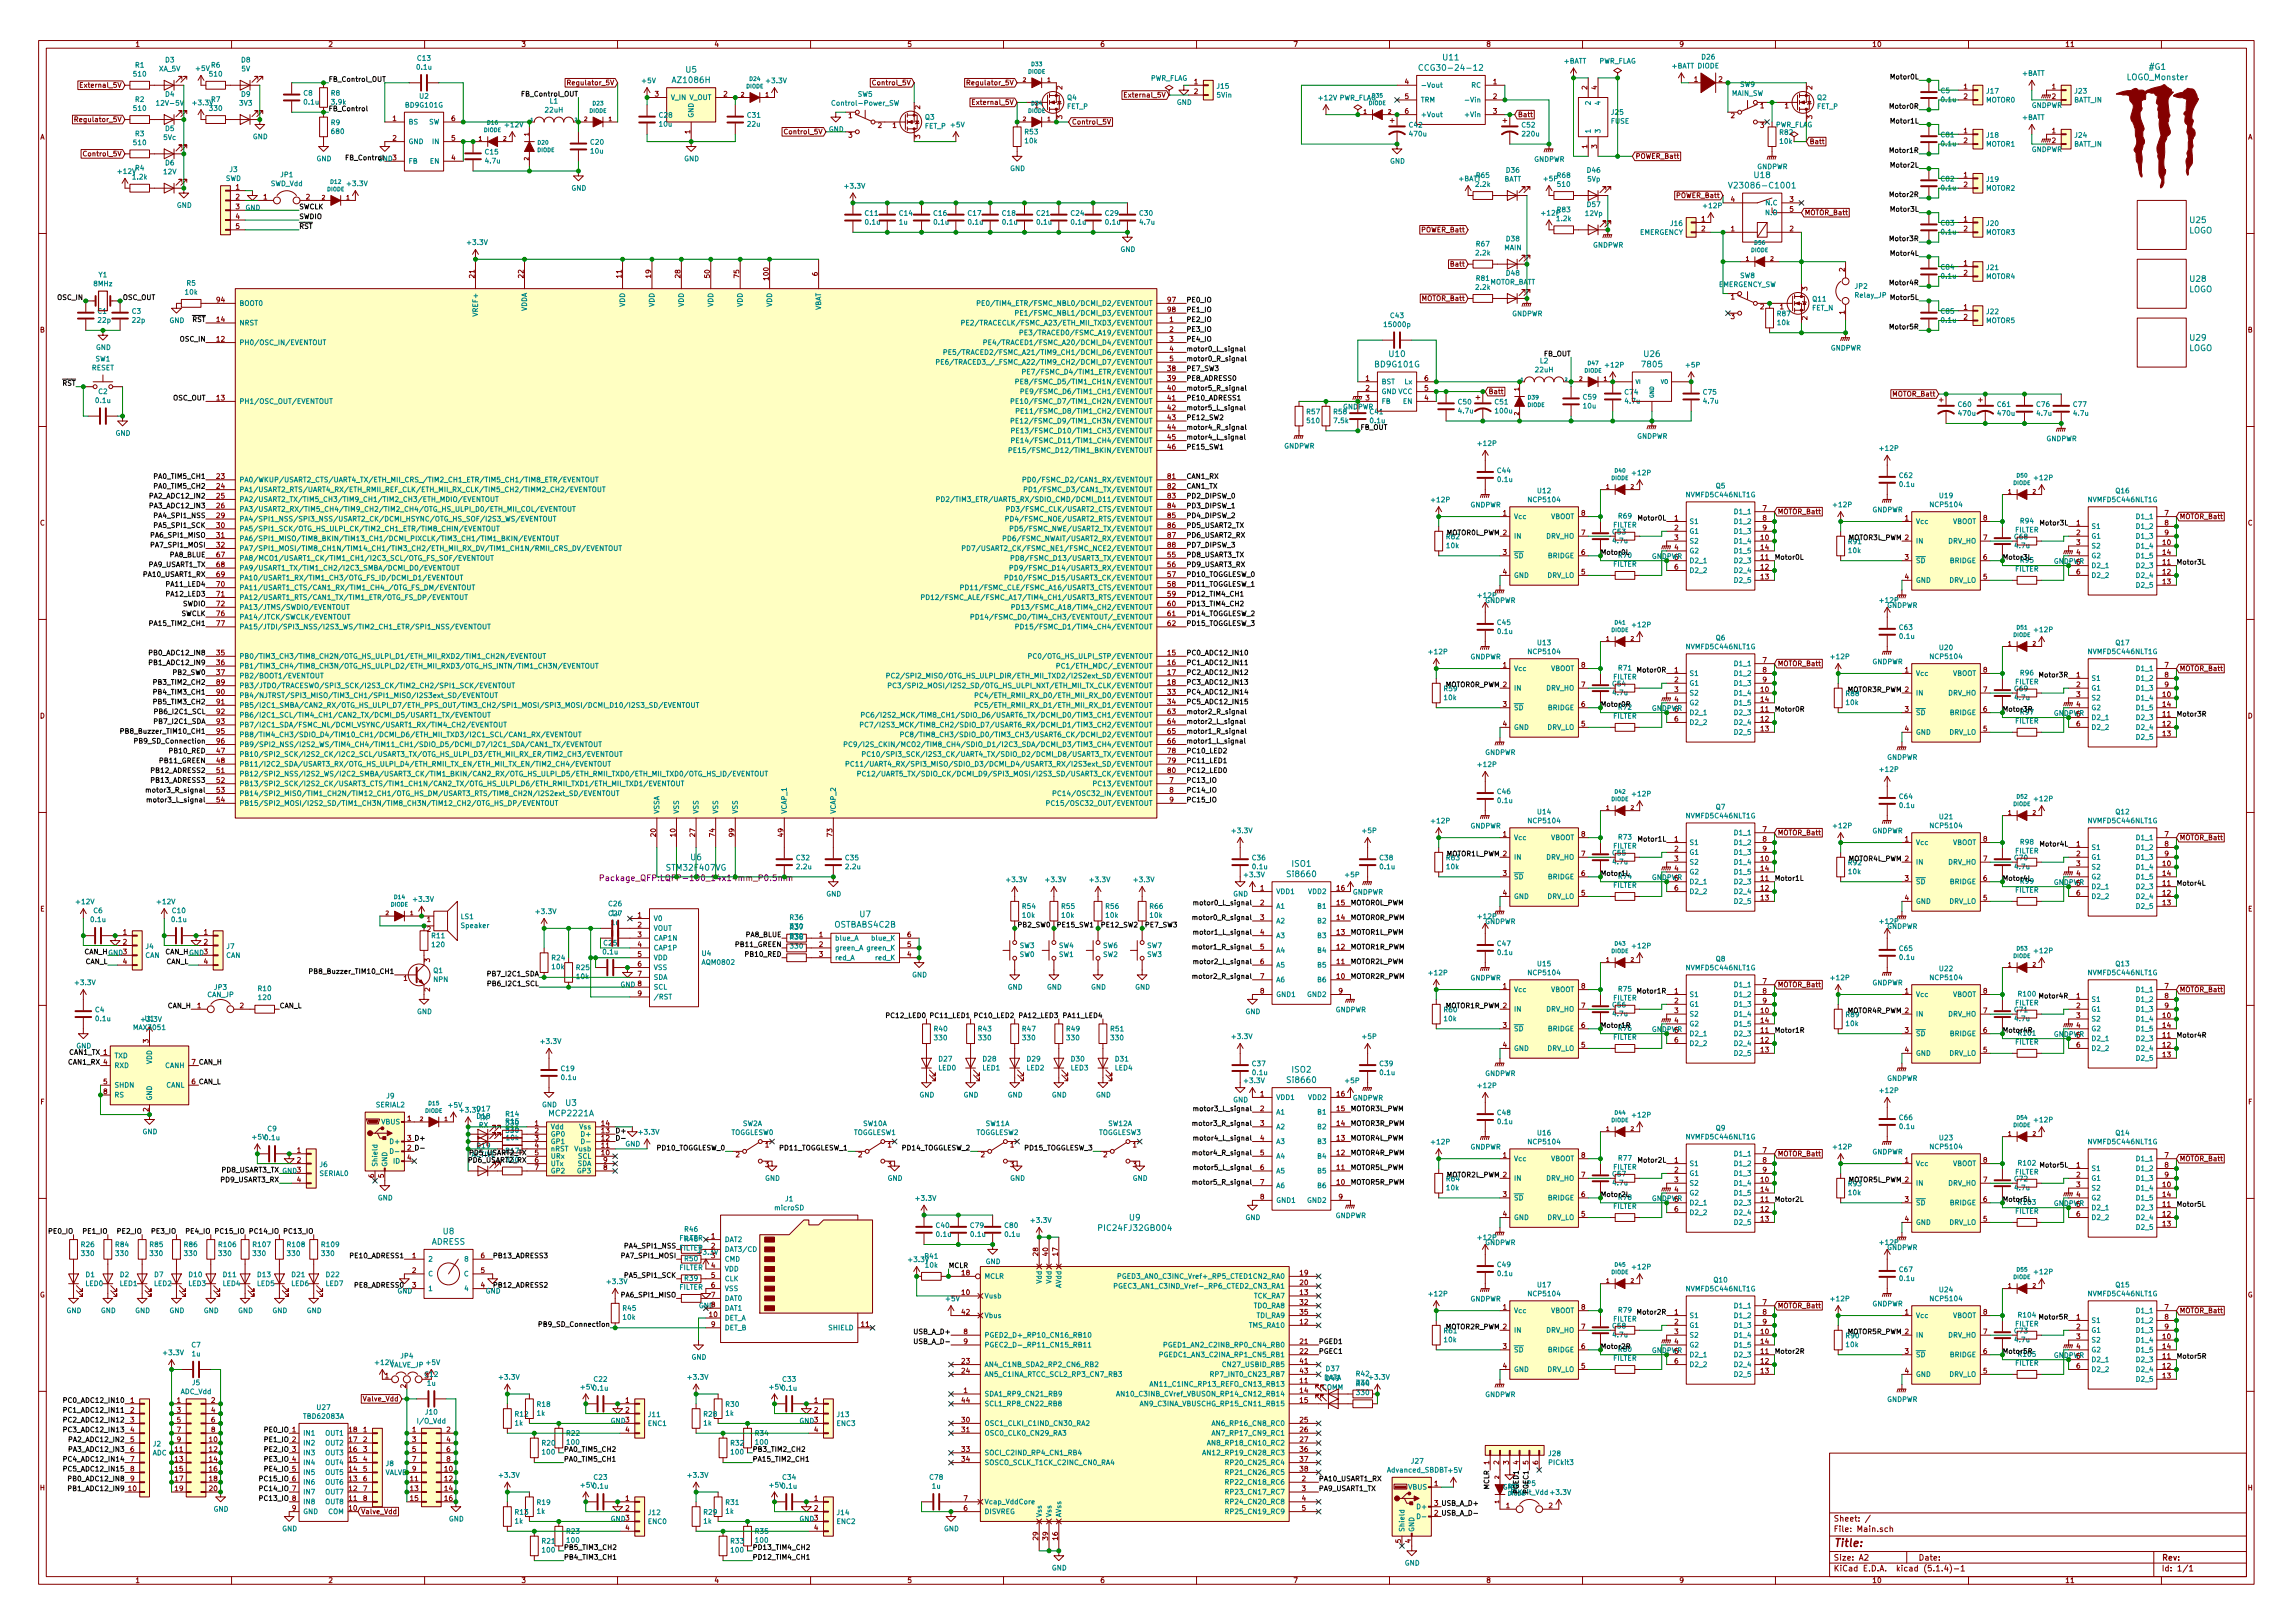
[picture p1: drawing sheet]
<svg xmlns="http://www.w3.org/2000/svg" width="297mm" height="210mm" viewBox="0 0 297 210" stroke-linecap="round" stroke-linejoin="round" font-family="sans-serif">
<defs><g id="words">
<text font-size="1.4" fill="#840000" x="237.5" y="200.4">Title:</text>
<g font-size="1.1" fill="#008484">
<text x="87.3" y="10.8">AZ1086H</text>
<text x="88.9" y="9.4">U5</text>
<text x="184.6" y="9.2">CCG30-24-12</text>
<text x="187" y="7.8">U11</text>
<text x="275.6" y="10.4">LOGO_Monster</text>
<text x="278.5" y="9">#G1</text>
<text x="227.3" y="23.1">U18</text>
<text x="224.7" y="24.4">V23086-C1001</text>
<text x="283.8" y="28.9">U25</text>
<text x="283.5" y="30.2">LOGO</text>
<text x="283.5" y="37.9">LOGO</text>
<text x="283.8" y="36.5">U28</text>
<text x="178.2" y="47.6">BD9G101G</text>
<text x="180" y="46.2">U10</text>
<text x="212.8" y="47.6">7805</text>
<text x="213" y="46.2">U26</text>
<text x="283.5" y="45.5">LOGO</text>
<text x="283.8" y="44.1">U29</text>
<text x="86.5" y="112.8">STM32F407VG</text>
<text x="89.5" y="111.4">U6</text>
<text x="166.9" y="113.6">Si8660</text>
<text x="167.4" y="112.3">ISO1</text>
<text x="111.4" y="118.8">U7</text>
<text x="108.1" y="120.2">OSTBABS4C2B</text>
<text x="73.3" y="143.3">U3</text>
<text x="166.9" y="140.3">Si8660</text>
<text x="167.4" y="138.9">ISO2</text>
<text x="71.2" y="144.6">MCP2221A</text>
<text x="55.9" y="161.2">ADRESS</text>
<text x="57.4" y="159.9">U8</text>
<text x="142.6" y="159.5">PIC24FJ32GB004</text>
<text x="146.3" y="158.1">U9</text>
</g>
<text font-size="1.1" fill="#008400" x="78.9" y="114.1">Package_QFP:LQFP-100_14x14mm_P0.5mm</text>
<g font-size="1" fill="#840000">
<text x="237.5" y="197.1">Sheet: /</text>
<text x="237.5" y="203.6">KiCad E.D.A. kicad (5.1.4)-1</text>
<text x="237.5" y="202.2">Size: A2</text>
<text x="237.5" y="198.5">File: Main.sch</text>
<text x="248.5" y="202.2">Date:</text>
<text x="280" y="202.2">Rev:</text>
<text x="280" y="203.6">Id: 1/1</text>
</g>
<g font-size=".9" fill="#840000">
<text x="10.7" y="11.4">External_5V</text>
<text x="17.5" y="6.1">1</text>
<text x="42.5" y="6.1">2</text>
<text x="67.5" y="6.1">3</text>
<text x="73.9" y="11">Regulator_5V</text>
<text x="92.5" y="6.1">4</text>
<text x="113.3" y="11">Control_5V</text>
<text x="117.5" y="6.1">5</text>
<text x="125.7" y="11">Regulator_5V</text>
<text x="137.6" y="11.6" transform="rotate(-90 137.6 11.6)">2</text>
<text x="142.5" y="6.1">6</text>
<text x="154.7" y="10.9">1</text>
<text x="167.5" y="6.1">7</text>
<text x="182" y="10.9">4</text>
<text x="192.5" y="6.1">8</text>
<text x="193.4" y="10.9">1</text>
<text x="205.6" y="11.6" transform="rotate(-90 205.6 11.6)">2</text>
<text x="206.9" y="11.6" transform="rotate(-90 206.9 11.6)">4</text>
<text x="217.5" y="6.1">9</text>
<text x="219.5" y="10.6">1</text>
<text x="222.6" y="10.6">2</text>
<text x="234.8" y="11.6" transform="rotate(-90 234.8 11.6)">2</text>
<text x="242.5" y="6.1">10</text>
<text x="254.4" y="11.6">1</text>
<text x="265.8" y="11.6">1</text>
<text x="267.5" y="6.1">11</text>
<text x="10.1" y="15.8">Regulator_5V</text>
<text x="50.9" y="15.7">1</text>
<text x="58.5" y="15.7">6</text>
<text x="84.8" y="12.5">3</text>
<text x="89.4" y="17.3" transform="rotate(-90 89.4 17.3)">1</text>
<text x="93.7" y="12.5">2</text>
<text x="101.9" y="17.4">Control_5V</text>
<text x="109.9" y="15.3">1</text>
<text x="109.9" y="17.8">3</text>
<text x="113.7" y="16.6">2</text>
<text x="115.6" y="16.6">1</text>
<text x="119.2" y="18" transform="rotate(-90 119.2 18)">3</text>
<text x="119.2" y="14.1" transform="rotate(-90 119.2 14.1)">2</text>
<text x="126.3" y="13.6">External_5V</text>
<text x="137.6" y="15.4" transform="rotate(-90 137.6 15.4)">3</text>
<text x="138.8" y="16.1">Control_5V</text>
<text x="146" y="12.6">External_5V</text>
<text x="154.7" y="12.2">2</text>
<text x="182" y="12.8">5</text>
<text x="182" y="14.7">6</text>
<text x="193.4" y="12.8">2</text>
<text x="193.4" y="14.7">3</text>
<text x="196.6" y="15.2">Batt</text>
<text x="224.2" y="15.3">2</text>
<text x="228" y="14">1</text>
<text x="228" y="16.6">3</text>
<text x="231.2" y="14">1</text>
<text x="234.8" y="15.4" transform="rotate(-90 234.8 15.4)">3</text>
<text x="254.4" y="12.8">2</text>
<text x="254.4" y="17.3">1</text>
<text x="265.8" y="12.8">2</text>
<text x="265.8" y="17.3">1</text>
<text x="5.2" y="18.1">A</text>
<text x="11.1" y="20.3">Control_5V</text>
<text x="50.9" y="18.2">2</text>
<text x="58.5" y="20.8">4</text>
<text x="58.5" y="18.2">5</text>
<text x="205.6" y="19.2" transform="rotate(-90 205.6 19.2)">1</text>
<text x="206.9" y="19.2" transform="rotate(-90 206.9 19.2)">3</text>
<text x="211.8" y="20.6">POWER_Batt</text>
<text x="234.4" y="18.7">Batt</text>
<text x="254.4" y="18.5">2</text>
<text x="254.4" y="23">1</text>
<text x="265.8" y="18.5">2</text>
<text x="291.2" y="18.1">A</text>
<text x="30.6" y="24.6">1</text>
<text x="30.6" y="25.8">2</text>
<text x="30.6" y="27.1">3</text>
<text x="30.6" y="28.4">4</text>
<text x="30.6" y="29.6">5</text>
<text x="34.1" y="25.8">1</text>
<text x="39.7" y="25.8">2</text>
<text x="217.3" y="25.6">POWER_Batt</text>
<text x="220.4" y="28.7">1</text>
<text x="220.4" y="30">2</text>
<text x="224.2" y="30">1</text>
<text x="224.2" y="26.2">4</text>
<text x="231.9" y="30">2</text>
<text x="231.9" y="26.2">3</text>
<text x="231.9" y="27.4">5</text>
<text x="233.8" y="27.9">MOTOR_Batt</text>
<text x="254.4" y="24.3">2</text>
<text x="254.4" y="28.7">1</text>
<text x="254.4" y="30">2</text>
<text x="61.5" y="36" transform="rotate(-90 61.5 36)">21</text>
<text x="67.8" y="36" transform="rotate(-90 67.8 36)">22</text>
<text x="80.5" y="36" transform="rotate(-90 80.5 36)">11</text>
<text x="84.3" y="36" transform="rotate(-90 84.3 36)">19</text>
<text x="88.1" y="36" transform="rotate(-90 88.1 36)">28</text>
<text x="91.9" y="36" transform="rotate(-90 91.9 36)">50</text>
<text x="95.8" y="36" transform="rotate(-90 95.8 36)">75</text>
<text x="105.9" y="35.7" transform="rotate(-90 105.9 35.7)">6</text>
<text x="184.2" y="30.1">POWER_Batt</text>
<text x="188.1" y="34.5">Batt</text>
<text x="239" y="35.2" transform="rotate(-90 239 35.2)">2</text>
<text x="254.4" y="34.4">1</text>
<text x="254.4" y="35.7">2</text>
<text x="28.1" y="41.7">14</text>
<text x="28.1" y="39.2">94</text>
<text x="99.6" y="36.2" transform="rotate(-90 99.6 36.2)">100</text>
<text x="151.3" y="39.2">97</text>
<text x="151.3" y="40.4">98</text>
<text x="151.5" y="41.7">1</text>
<text x="184.3" y="39">MOTOR_Batt</text>
<text x="224.2" y="38.8">1</text>
<text x="224.2" y="41.3">3</text>
<text x="228" y="40.1">2</text>
<text x="230.6" y="40.1">1</text>
<text x="234.1" y="41.4" transform="rotate(-90 234.1 41.4)">2</text>
<text x="234.1" y="37.6" transform="rotate(-90 234.1 37.6)">3</text>
<text x="239" y="40.7" transform="rotate(-90 239 40.7)">1</text>
<text x="254.4" y="40.1">1</text>
<text x="254.4" y="41.4">2</text>
<text x="5.2" y="43.1">B</text>
<text x="28.1" y="44.3">12</text>
<text x="151.5" y="43">2</text>
<text x="151.5" y="44.3">3</text>
<text x="151.5" y="45.5">4</text>
<text x="151.5" y="46.8">5</text>
<text x="291.2" y="43.1">B</text>
<text x="28.1" y="51.9">13</text>
<text x="151.3" y="48.1">38</text>
<text x="151.3" y="49.3">39</text>
<text x="151.3" y="50.6">40</text>
<text x="151.3" y="51.9">41</text>
<text x="151.3" y="53.1">42</text>
<text x="176.9" y="49.3">1</text>
<text x="176.9" y="50.6">2</text>
<text x="176.9" y="51.9">3</text>
<text x="184.5" y="51.9">4</text>
<text x="184.5" y="50.6">5</text>
<text x="184.5" y="49.3">6</text>
<text x="192.8" y="51">Batt</text>
<text x="245.2" y="51.4">MOTOR_Batt</text>
<text x="151.3" y="54.4">43</text>
<text x="151.3" y="55.7">44</text>
<text x="151.3" y="57">45</text>
<text x="151.3" y="58.2">46</text>
<text x="28.1" y="62">23</text>
<text x="28.1" y="63.3">24</text>
<text x="28.1" y="64.6">25</text>
<text x="28.1" y="65.8">26</text>
<text x="151.3" y="62">81</text>
<text x="151.3" y="63.3">82</text>
<text x="151.3" y="64.6">83</text>
<text x="151.3" y="65.8">84</text>
<text x="5.2" y="68.1">C</text>
<text x="28.1" y="67.1">29</text>
<text x="28.1" y="68.4">30</text>
<text x="28.1" y="69.7">31</text>
<text x="28.1" y="70.9">32</text>
<text x="151.3" y="67.1">85</text>
<text x="151.3" y="68.4">86</text>
<text x="151.3" y="69.7">87</text>
<text x="151.3" y="70.9">88</text>
<text x="194.7" y="66.8">1</text>
<text x="194.7" y="71.9">3</text>
<text x="204.9" y="71.9">6</text>
<text x="204.9" y="69.3">7</text>
<text x="204.9" y="66.8">8</text>
<text x="216.9" y="67.4">1</text>
<text x="216.9" y="68.7">2</text>
<text x="216.9" y="70">3</text>
<text x="216.9" y="71.2">4</text>
<text x="228.1" y="70">10</text>
<text x="228.1" y="71.2">14</text>
<text x="228.4" y="66.2">7</text>
<text x="228.4" y="67.4">8</text>
<text x="228.4" y="68.7">9</text>
<text x="230.3" y="66.6">MOTOR_Batt</text>
<text x="246.8" y="67.4">1</text>
<text x="256.9" y="70">7</text>
<text x="256.9" y="67.4">8</text>
<text x="269" y="68.1">1</text>
<text x="269" y="69.3">2</text>
<text x="269" y="70.6">3</text>
<text x="269" y="71.9">4</text>
<text x="280.2" y="70.6">10</text>
<text x="280.2" y="71.9">14</text>
<text x="280.4" y="66.8">7</text>
<text x="280.4" y="68.1">8</text>
<text x="280.4" y="69.3">9</text>
<text x="282.3" y="67.2">MOTOR_Batt</text>
<text x="291.2" y="68.1">C</text>
<text x="28.1" y="72.2">67</text>
<text x="28.1" y="73.5">68</text>
<text x="28.1" y="74.7">69</text>
<text x="28.1" y="76">70</text>
<text x="28.1" y="77.3">71</text>
<text x="151.3" y="72.2">55</text>
<text x="151.3" y="73.5">56</text>
<text x="151.3" y="74.7">57</text>
<text x="151.3" y="76">58</text>
<text x="151.3" y="77.3">59</text>
<text x="194.7" y="74.4">4</text>
<text x="204.9" y="74.4">5</text>
<text x="216.9" y="72.5">5</text>
<text x="216.9" y="73.8">6</text>
<text x="228.1" y="72.5">11</text>
<text x="228.1" y="73.8">12</text>
<text x="228.1" y="75.1">13</text>
<text x="246.8" y="72.5">3</text>
<text x="246.8" y="75.1">4</text>
<text x="256.9" y="75.1">5</text>
<text x="256.9" y="72.5">6</text>
<text x="269" y="73.1">5</text>
<text x="269" y="74.4">6</text>
<text x="280.2" y="73.1">11</text>
<text x="280.2" y="74.4">12</text>
<text x="280.2" y="75.7">13</text>
<text x="28.1" y="78.5">72</text>
<text x="28.1" y="79.8">76</text>
<text x="28.1" y="81.1">77</text>
<text x="151.3" y="78.5">60</text>
<text x="151.3" y="79.8">61</text>
<text x="151.3" y="81.1">62</text>
<text x="28.1" y="84.9">35</text>
<text x="28.1" y="86.2">36</text>
<text x="28.1" y="87.4">37</text>
<text x="28.1" y="88.7">89</text>
<text x="28.1" y="90">90</text>
<text x="151.3" y="84.9">15</text>
<text x="151.3" y="86.2">16</text>
<text x="151.3" y="87.4">17</text>
<text x="151.3" y="88.7">18</text>
<text x="151.3" y="90">33</text>
<text x="194.7" y="86.5">1</text>
<text x="204.9" y="89">7</text>
<text x="204.9" y="86.5">8</text>
<text x="216.9" y="87.1">1</text>
<text x="216.9" y="88.4">2</text>
<text x="216.9" y="89.7">3</text>
<text x="228.1" y="89.7">10</text>
<text x="228.4" y="85.8">7</text>
<text x="228.4" y="87.1">8</text>
<text x="228.4" y="88.4">9</text>
<text x="230.3" y="86.3">MOTOR_Batt</text>
<text x="246.8" y="87.1">1</text>
<text x="256.9" y="89.7">7</text>
<text x="256.9" y="87.1">8</text>
<text x="269" y="87.8">1</text>
<text x="269" y="89">2</text>
<text x="280.4" y="86.5">7</text>
<text x="280.4" y="87.8">8</text>
<text x="280.4" y="89">9</text>
<text x="282.3" y="86.9">MOTOR_Batt</text>
<text x="5.2" y="93.1">D</text>
<text x="28.1" y="91.2">91</text>
<text x="28.1" y="92.5">92</text>
<text x="28.1" y="93.8">93</text>
<text x="28.1" y="95.1">95</text>
<text x="151.3" y="91.2">34</text>
<text x="151.3" y="92.5">63</text>
<text x="151.3" y="93.8">64</text>
<text x="151.3" y="95.1">65</text>
<text x="194.7" y="91.6">3</text>
<text x="194.7" y="94.1">4</text>
<text x="204.9" y="94.1">5</text>
<text x="204.9" y="91.6">6</text>
<text x="216.9" y="90.9">4</text>
<text x="216.9" y="92.2">5</text>
<text x="216.9" y="93.5">6</text>
<text x="228.1" y="92.2">11</text>
<text x="228.1" y="93.5">12</text>
<text x="228.1" y="94.7">13</text>
<text x="228.1" y="90.9">14</text>
<text x="246.8" y="92.2">3</text>
<text x="246.8" y="94.7">4</text>
<text x="256.9" y="94.7">5</text>
<text x="256.9" y="92.2">6</text>
<text x="269" y="90.3">3</text>
<text x="269" y="91.6">4</text>
<text x="269" y="92.8">5</text>
<text x="269" y="94.1">6</text>
<text x="280.2" y="90.3">10</text>
<text x="280.2" y="92.8">11</text>
<text x="280.2" y="94.1">12</text>
<text x="280.2" y="95.4">13</text>
<text x="280.2" y="91.6">14</text>
<text x="291.2" y="93.1">D</text>
<text x="28.1" y="97.6">47</text>
<text x="28.1" y="98.9">48</text>
<text x="28.1" y="100.1">51</text>
<text x="28.1" y="101.4">52</text>
<text x="28.1" y="96.3">96</text>
<text x="151.3" y="96.3">66</text>
<text x="151.3" y="97.6">78</text>
<text x="151.3" y="98.9">79</text>
<text x="151.3" y="100.1">80</text>
<text x="151.5" y="101.4">7</text>
<text x="28.1" y="102.7">53</text>
<text x="28.1" y="103.9">54</text>
<text x="151.5" y="102.7">8</text>
<text x="151.5" y="103.9">9</text>
<text x="228.4" y="107.8">7</text>
<text x="85" y="108.4" transform="rotate(-90 85 108.4)">20</text>
<text x="87.5" y="108.4" transform="rotate(-90 87.5 108.4)">10</text>
<text x="90" y="108.4" transform="rotate(-90 90 108.4)">27</text>
<text x="92.6" y="108.4" transform="rotate(-90 92.6 108.4)">74</text>
<text x="95.1" y="108.4" transform="rotate(-90 95.1 108.4)">99</text>
<text x="101.5" y="108.4" transform="rotate(-90 101.5 108.4)">49</text>
<text x="107.8" y="108.4" transform="rotate(-90 107.8 108.4)">73</text>
<text x="194.7" y="108.4">1</text>
<text x="194.7" y="113.5">3</text>
<text x="204.9" y="113.5">6</text>
<text x="204.9" y="110.9">7</text>
<text x="204.9" y="108.4">8</text>
<text x="216.9" y="109">1</text>
<text x="216.9" y="110.3">2</text>
<text x="216.9" y="111.6">3</text>
<text x="216.9" y="112.8">4</text>
<text x="228.1" y="111.6">10</text>
<text x="228.1" y="112.8">14</text>
<text x="228.4" y="109">8</text>
<text x="228.4" y="110.3">9</text>
<text x="230.3" y="108.2">MOTOR_Batt</text>
<text x="246.8" y="109">1</text>
<text x="256.9" y="111.6">7</text>
<text x="256.9" y="109">8</text>
<text x="269" y="109.7">1</text>
<text x="269" y="110.9">2</text>
<text x="269" y="112.2">3</text>
<text x="269" y="113.5">4</text>
<text x="280.2" y="112.2">10</text>
<text x="280.2" y="113.5">14</text>
<text x="280.4" y="108.4">7</text>
<text x="280.4" y="109.7">8</text>
<text x="280.4" y="110.9">9</text>
<text x="282.3" y="108.8">MOTOR_Batt</text>
<text x="5.2" y="118.1">E</text>
<text x="55.3" y="119.4">1</text>
<text x="82.6" y="118.9">1</text>
<text x="163.3" y="115.4">1</text>
<text x="163.3" y="117.3">2</text>
<text x="163.3" y="119.2">3</text>
<text x="173.2" y="119.2">14</text>
<text x="173.2" y="117.3">15</text>
<text x="173.2" y="115.4">16</text>
<text x="194.7" y="116">4</text>
<text x="204.9" y="116">5</text>
<text x="216.9" y="114.1">5</text>
<text x="216.9" y="115.4">6</text>
<text x="228.1" y="114.1">11</text>
<text x="228.1" y="115.4">12</text>
<text x="228.1" y="116.6">13</text>
<text x="246.8" y="114.1">3</text>
<text x="246.8" y="116.6">4</text>
<text x="256.9" y="116.6">5</text>
<text x="256.9" y="114.1">6</text>
<text x="269" y="114.7">5</text>
<text x="269" y="116">6</text>
<text x="280.2" y="114.7">11</text>
<text x="280.2" y="116">12</text>
<text x="280.2" y="117.3">13</text>
<text x="291.2" y="118.1">E</text>
<text x="16" y="121.1">1</text>
<text x="16" y="122.4">2</text>
<text x="16" y="124.9">4</text>
<text x="26.4" y="121.1">1</text>
<text x="26.4" y="122.4">2</text>
<text x="26.4" y="124.9">4</text>
<text x="55.3" y="120.7">2</text>
<text x="55.7" y="124.6" transform="rotate(-90 55.7 124.6)">3</text>
<text x="82.6" y="120.1">2</text>
<text x="82.6" y="121.4">3</text>
<text x="82.6" y="122.7">4</text>
<text x="82.6" y="123.9">5</text>
<text x="82.6" y="125.2">6</text>
<text x="106.1" y="121.4">1</text>
<text x="106.1" y="122.7">2</text>
<text x="106.1" y="123.9">3</text>
<text x="117.6" y="123.9">4</text>
<text x="117.6" y="122.7">5</text>
<text x="117.6" y="121.4">6</text>
<text x="163.3" y="121.1">4</text>
<text x="163.3" y="123">5</text>
<text x="163.3" y="124.9">6</text>
<text x="173.2" y="124.9">11</text>
<text x="173.2" y="123">12</text>
<text x="173.2" y="121.1">13</text>
<text x="25.6" y="130.6">1</text>
<text x="31.1" y="130.6">2</text>
<text x="52.3" y="127.1">1</text>
<text x="55.7" y="128.4" transform="rotate(-90 55.7 128.4)">2</text>
<text x="82.6" y="126.5">7</text>
<text x="82.6" y="129">9</text>
<text x="163.3" y="126.8">7</text>
<text x="163.3" y="128.7">8</text>
<text x="173.2" y="126.8">10</text>
<text x="173.4" y="128.7">9</text>
<text x="194.7" y="128.1">1</text>
<text x="204.9" y="130.6">7</text>
<text x="204.9" y="128.1">8</text>
<text x="216.9" y="128.7">1</text>
<text x="216.9" y="130">2</text>
<text x="216.9" y="131.2">3</text>
<text x="228.1" y="131.2">10</text>
<text x="228.4" y="127.4">7</text>
<text x="228.4" y="128.7">8</text>
<text x="228.4" y="130">9</text>
<text x="230.3" y="127.9">MOTOR_Batt</text>
<text x="246.8" y="128.7">1</text>
<text x="256.9" y="131.2">7</text>
<text x="256.9" y="128.7">8</text>
<text x="269" y="129.3">1</text>
<text x="269" y="130.6">2</text>
<text x="269" y="131.9">3</text>
<text x="280.2" y="131.9">10</text>
<text x="280.4" y="128.1">7</text>
<text x="280.4" y="129.3">8</text>
<text x="280.4" y="130.6">9</text>
<text x="282.3" y="128.5">MOTOR_Batt</text>
<text x="19.2" y="135.1" transform="rotate(-90 19.2 135.1)">3</text>
<text x="194.7" y="133.2">3</text>
<text x="194.7" y="135.7">4</text>
<text x="204.9" y="135.7">5</text>
<text x="204.9" y="133.2">6</text>
<text x="216.9" y="132.5">4</text>
<text x="216.9" y="133.8">5</text>
<text x="216.9" y="135.1">6</text>
<text x="228.1" y="133.8">11</text>
<text x="228.1" y="135.1">12</text>
<text x="228.1" y="136.3">13</text>
<text x="228.1" y="132.5">14</text>
<text x="246.8" y="133.8">3</text>
<text x="246.8" y="136.3">4</text>
<text x="256.9" y="136.3">5</text>
<text x="256.9" y="133.8">6</text>
<text x="269" y="133.2">4</text>
<text x="269" y="134.4">5</text>
<text x="269" y="135.7">6</text>
<text x="280.2" y="134.4">11</text>
<text x="280.2" y="135.7">12</text>
<text x="280.2" y="137">13</text>
<text x="280.2" y="133.2">14</text>
<text x="5.2" y="143.1">F</text>
<text x="13.4" y="140.5">5</text>
<text x="13.4" y="141.7">8</text>
<text x="19.2" y="144" transform="rotate(-90 19.2 144)">2</text>
<text x="163.3" y="142">1</text>
<text x="163.3" y="143.9">2</text>
<text x="173.2" y="143.9">15</text>
<text x="173.2" y="142">16</text>
<text x="291.2" y="143.1">F</text>
<text x="38.5" y="149.3">1</text>
<text x="52.8" y="145.2">1</text>
<text x="61.8" y="148.7">D19</text>
<text x="69.3" y="145.9">1</text>
<text x="69.3" y="146.8">2</text>
<text x="69.3" y="147.8">3</text>
<text x="69.3" y="148.7">4</text>
<text x="69.3" y="149.7">5</text>
<text x="77.9" y="149.7">10</text>
<text x="77.9" y="148.7">11</text>
<text x="77.9" y="147.8">12</text>
<text x="77.9" y="146.8">13</text>
<text x="77.9" y="145.9">14</text>
<text x="95.3" y="149.9">2</text>
<text x="99.1" y="148.6">1</text>
<text x="111.2" y="149.9">2</text>
<text x="115" y="148.6">1</text>
<text x="127.1" y="149.9">2</text>
<text x="130.9" y="148.6">1</text>
<text x="143" y="149.9">2</text>
<text x="146.8" y="148.6">1</text>
<text x="163.3" y="145.9">3</text>
<text x="163.3" y="147.8">4</text>
<text x="163.3" y="149.7">5</text>
<text x="173.2" y="149.7">12</text>
<text x="173.2" y="147.8">13</text>
<text x="173.2" y="145.9">14</text>
<text x="194.7" y="150">1</text>
<text x="204.9" y="150">8</text>
<text x="228.4" y="149.3">7</text>
<text x="230.3" y="149.8">MOTOR_Batt</text>
<text x="280.4" y="150">7</text>
<text x="38.5" y="150.6">2</text>
<text x="38.5" y="153.2">4</text>
<text x="48.5" y="152.6" transform="rotate(-90 48.5 152.6)">6</text>
<text x="49.7" y="152.6" transform="rotate(-90 49.7 152.6)">5</text>
<text x="52.8" y="150.3">4</text>
<text x="69.3" y="150.6">6</text>
<text x="69.3" y="151.6">7</text>
<text x="78.2" y="151.6">8</text>
<text x="78.2" y="150.6">9</text>
<text x="99.1" y="151.2">3</text>
<text x="115" y="151.2">3</text>
<text x="130.9" y="151.2">3</text>
<text x="146.8" y="151.2">3</text>
<text x="163.3" y="151.6">6</text>
<text x="163.3" y="153.5">7</text>
<text x="163.3" y="155.4">8</text>
<text x="173.2" y="153.5">10</text>
<text x="173.2" y="151.6">11</text>
<text x="173.4" y="155.4">9</text>
<text x="194.7" y="155.1">3</text>
<text x="204.9" y="155.1">6</text>
<text x="204.9" y="152.5">7</text>
<text x="216.9" y="150.6">1</text>
<text x="216.9" y="151.9">2</text>
<text x="216.9" y="153.2">3</text>
<text x="216.9" y="154.4">4</text>
<text x="216.9" y="155.7">5</text>
<text x="228.1" y="153.2">10</text>
<text x="228.1" y="155.7">11</text>
<text x="228.1" y="154.4">14</text>
<text x="228.4" y="150.6">8</text>
<text x="228.4" y="151.9">9</text>
<text x="246.8" y="150.6">1</text>
<text x="246.8" y="155.7">3</text>
<text x="256.9" y="155.7">6</text>
<text x="256.9" y="153.2">7</text>
<text x="256.9" y="150.6">8</text>
<text x="269" y="151.3">1</text>
<text x="269" y="152.5">2</text>
<text x="269" y="153.8">3</text>
<text x="269" y="155.1">4</text>
<text x="280.2" y="153.8">10</text>
<text x="280.2" y="155.1">14</text>
<text x="280.4" y="151.3">8</text>
<text x="280.4" y="152.5">9</text>
<text x="282.3" y="150.4">MOTOR_Batt</text>
<text x="92.2" y="160.5">1</text>
<text x="92.2" y="161.7">2</text>
<text x="194.7" y="157.6">4</text>
<text x="204.9" y="157.6">5</text>
<text x="216.9" y="157">6</text>
<text x="228.1" y="157">12</text>
<text x="228.1" y="158.2">13</text>
<text x="246.8" y="158.2">4</text>
<text x="256.9" y="158.2">5</text>
<text x="269" y="156.3">5</text>
<text x="269" y="157.6">6</text>
<text x="280.2" y="156.3">11</text>
<text x="280.2" y="157.6">12</text>
<text x="280.2" y="158.9">13</text>
<text x="53.4" y="163">1</text>
<text x="53.4" y="164.9">2</text>
<text x="53.4" y="166.8">3</text>
<text x="62.3" y="166.8">4</text>
<text x="62.3" y="164.9">5</text>
<text x="62.3" y="163">6</text>
<text x="92.2" y="163">3</text>
<text x="92.2" y="164.3">4</text>
<text x="92.2" y="165.5">5</text>
<text x="92.2" y="166.8">6</text>
<text x="124.6" y="167.8">10</text>
<text x="124.6" y="165.2">18</text>
<text x="134.5" y="162.7" transform="rotate(-90 134.5 162.7)">28</text>
<text x="135.8" y="162.7" transform="rotate(-90 135.8 162.7)">40</text>
<text x="137" y="162.7" transform="rotate(-90 137 162.7)">17</text>
<text x="168.4" y="167.8">13</text>
<text x="168.4" y="165.2">19</text>
<text x="168.4" y="166.5">20</text>
<text x="5.2" y="168.1">G</text>
<text x="91.9" y="170.6">10</text>
<text x="92.2" y="168.1">7</text>
<text x="92.2" y="171.9">9</text>
<text x="111.6" y="171.9">11</text>
<text x="124.6" y="170.3">42</text>
<text x="124.9" y="172.8">8</text>
<text x="168.4" y="171.6">12</text>
<text x="168.4" y="169">32</text>
<text x="168.4" y="170.3">35</text>
<text x="194.7" y="169.7">1</text>
<text x="204.9" y="172.2">7</text>
<text x="204.9" y="169.7">8</text>
<text x="216.9" y="170.3">1</text>
<text x="216.9" y="171.6">2</text>
<text x="216.9" y="172.8">3</text>
<text x="228.1" y="172.8">10</text>
<text x="228.4" y="169">7</text>
<text x="228.4" y="170.3">8</text>
<text x="228.4" y="171.6">9</text>
<text x="230.3" y="169.5">MOTOR_Batt</text>
<text x="246.8" y="170.3">1</text>
<text x="256.9" y="172.8">7</text>
<text x="256.9" y="170.3">8</text>
<text x="269" y="170.9">1</text>
<text x="269" y="172.2">2</text>
<text x="269" y="173.5">3</text>
<text x="280.2" y="173.5">10</text>
<text x="280.4" y="169.7">7</text>
<text x="280.4" y="170.9">8</text>
<text x="280.4" y="172.2">9</text>
<text x="282.3" y="170.1">MOTOR_Batt</text>
<text x="291.2" y="168.1">G</text>
<text x="49.9" y="178.6">1</text>
<text x="52.6" y="179.8" transform="rotate(-90 52.6 179.8)">2</text>
<text x="55" y="178.6">3</text>
<text x="124.6" y="176.7">23</text>
<text x="124.6" y="177.9">24</text>
<text x="124.9" y="174.1">9</text>
<text x="168.4" y="179.2">11</text>
<text x="168.4" y="174.1">21</text>
<text x="168.4" y="175.4">22</text>
<text x="168.4" y="176.7">41</text>
<text x="168.4" y="177.9">43</text>
<text x="194.7" y="174.7">3</text>
<text x="194.7" y="177.3">4</text>
<text x="204.9" y="177.3">5</text>
<text x="204.9" y="174.7">6</text>
<text x="216.9" y="174.1">4</text>
<text x="216.9" y="175.4">5</text>
<text x="216.9" y="176.7">6</text>
<text x="228.1" y="175.4">11</text>
<text x="228.1" y="176.7">12</text>
<text x="228.1" y="177.9">13</text>
<text x="228.1" y="174.1">14</text>
<text x="246.8" y="175.4">3</text>
<text x="246.8" y="177.9">4</text>
<text x="256.9" y="177.9">5</text>
<text x="256.9" y="175.4">6</text>
<text x="269" y="174.7">4</text>
<text x="269" y="176">5</text>
<text x="269" y="177.3">6</text>
<text x="280.2" y="176">11</text>
<text x="280.2" y="177.3">12</text>
<text x="280.2" y="178.6">13</text>
<text x="280.2" y="174.7">14</text>
<text x="16.9" y="181.7">1</text>
<text x="16.9" y="183">2</text>
<text x="16.9" y="184.3">3</text>
<text x="16.9" y="185.5">4</text>
<text x="22.9" y="181.7">1</text>
<text x="22.9" y="183">3</text>
<text x="22.9" y="184.3">5</text>
<text x="22.9" y="185.5">7</text>
<text x="27.4" y="181.7">2</text>
<text x="27.4" y="183">4</text>
<text x="27.4" y="184.3">6</text>
<text x="27.4" y="185.5">8</text>
<text x="45.2" y="185.5">18</text>
<text x="47.1" y="185.5">1</text>
<text x="47.2" y="181.5">Valve_Vdd</text>
<text x="53.4" y="185.5">1</text>
<text x="57.9" y="185.5">2</text>
<text x="81" y="181.7">1</text>
<text x="81" y="183">2</text>
<text x="81" y="185.5">4</text>
<text x="105.5" y="181.7">1</text>
<text x="105.5" y="183">2</text>
<text x="105.5" y="185.5">4</text>
<text x="124.6" y="184.3">30</text>
<text x="124.6" y="185.5">31</text>
<text x="124.6" y="181.7">44</text>
<text x="124.9" y="180.5">1</text>
<text x="168.4" y="180.5">14</text>
<text x="168.4" y="181.7">15</text>
<text x="168.4" y="184.3">25</text>
<text x="168.4" y="185.5">26</text>
<text x="171.2" y="180.1">COMM</text>
<text x="16.9" y="186.8">5</text>
<text x="16.9" y="188.1">6</text>
<text x="16.9" y="189.4">7</text>
<text x="16.9" y="190.6">8</text>
<text x="16.9" y="191.9">9</text>
<text x="22.7" y="188.1">11</text>
<text x="22.7" y="189.4">13</text>
<text x="22.7" y="190.6">15</text>
<text x="22.7" y="191.9">17</text>
<text x="22.9" y="186.8">9</text>
<text x="27.1" y="186.8">10</text>
<text x="27.1" y="188.1">12</text>
<text x="27.1" y="189.4">14</text>
<text x="27.1" y="190.6">16</text>
<text x="27.1" y="191.9">18</text>
<text x="45.2" y="191.9">13</text>
<text x="45.2" y="190.6">14</text>
<text x="45.2" y="189.4">15</text>
<text x="45.2" y="188.1">16</text>
<text x="45.2" y="186.8">17</text>
<text x="47.1" y="186.8">2</text>
<text x="47.1" y="188.1">3</text>
<text x="47.1" y="189.4">4</text>
<text x="47.1" y="190.6">5</text>
<text x="47.1" y="191.9">6</text>
<text x="53.2" y="191.9">11</text>
<text x="53.4" y="186.8">3</text>
<text x="53.4" y="188.1">5</text>
<text x="53.4" y="189.4">7</text>
<text x="53.4" y="190.6">9</text>
<text x="57.6" y="190.6">10</text>
<text x="57.6" y="191.9">12</text>
<text x="57.9" y="186.8">4</text>
<text x="57.9" y="188.1">6</text>
<text x="57.9" y="189.4">8</text>
<text x="124.6" y="188.1">33</text>
<text x="124.6" y="189.4">34</text>
<text x="168.4" y="186.8">27</text>
<text x="168.4" y="188.1">36</text>
<text x="168.4" y="189.4">37</text>
<text x="168.4" y="190.6">38</text>
<text x="168.7" y="191.9">2</text>
<text x="192.9" y="189.7" transform="rotate(-90 192.9 189.7)">1</text>
<text x="194.2" y="189.7" transform="rotate(-90 194.2 189.7)">2</text>
<text x="195.5" y="189.7" transform="rotate(-90 195.5 189.7)">3</text>
<text x="196.7" y="189.7" transform="rotate(-90 196.7 189.7)">4</text>
<text x="198" y="189.7" transform="rotate(-90 198 189.7)">5</text>
<text x="199.3" y="189.7" transform="rotate(-90 199.3 189.7)">6</text>
<text x="5.2" y="193.1">H</text>
<text x="16.7" y="193.2">10</text>
<text x="22.7" y="193.2">19</text>
<text x="27.1" y="193.2">20</text>
<text x="37.9" y="195.7">9</text>
<text x="45.2" y="195.7">10</text>
<text x="45.2" y="194.4">11</text>
<text x="45.2" y="193.2">12</text>
<text x="46.7" y="196.1">Valve_Vdd</text>
<text x="47.1" y="193.2">7</text>
<text x="47.1" y="194.4">8</text>
<text x="53.2" y="193.2">13</text>
<text x="53.2" y="194.4">15</text>
<text x="57.6" y="193.2">14</text>
<text x="57.6" y="194.4">16</text>
<text x="81" y="194.4">1</text>
<text x="81" y="195.7">2</text>
<text x="105.5" y="194.4">1</text>
<text x="105.5" y="195.7">2</text>
<text x="124.9" y="195.7">6</text>
<text x="124.9" y="194.4">7</text>
<text x="168.7" y="193.2">3</text>
<text x="168.7" y="194.4">4</text>
<text x="168.7" y="195.7">5</text>
<text x="185.8" y="192.5">1</text>
<text x="195.1" y="195.4">1</text>
<text x="200.6" y="195.4">2</text>
<text x="291.2" y="193.1">H</text>
<text x="81" y="198.2">4</text>
<text x="105.5" y="198.2">4</text>
<text x="134.5" y="199.5" transform="rotate(-90 134.5 199.5)">29</text>
<text x="135.8" y="199.5" transform="rotate(-90 135.8 199.5)">39</text>
<text x="137" y="199.5" transform="rotate(-90 137 199.5)">16</text>
<text x="181.5" y="199.9" transform="rotate(-90 181.5 199.9)">5</text>
<text x="182.8" y="199.9" transform="rotate(-90 182.8 199.9)">4</text>
<text x="17.5" y="205.1">1</text>
<text x="42.5" y="205.1">2</text>
<text x="67.5" y="205.1">3</text>
<text x="92.5" y="205.1">4</text>
<text x="117.5" y="205.1">5</text>
<text x="142.5" y="205.1">6</text>
<text x="167.5" y="205.1">7</text>
<text x="192.5" y="205.1">8</text>
<text x="217.5" y="205.1">9</text>
<text x="242.5" y="205.1">10</text>
<text x="267.5" y="205.1">11</text>
</g>
<g font-size=".9" fill="#008484">
<text x="17.4" y="9.9">510</text>
<text x="17.5" y="8.8">R1</text>
<text x="20.6" y="9.2">XA_5V</text>
<text x="21.4" y="8.1">D3</text>
<text x="25.4" y="9.2">+5V</text>
<text x="27.2" y="9.9">510</text>
<text x="27.4" y="8.8">R6</text>
<text x="31.3" y="8.1">D8</text>
<text x="31.3" y="9.2">5V</text>
<text x="54.1" y="9">0.1u</text>
<text x="54.1" y="7.9">C13</text>
<text x="83.2" y="10.8">+5V</text>
<text x="99.4" y="10.8">+3.3V</text>
<text x="149" y="10.5">PWR_FLAG</text>
<text x="157.7" y="11.5">J15</text>
<text x="184" y="11.4">-Vout</text>
<text x="190.6" y="11.4">RC</text>
<text x="202.6" y="8.2">+BATT</text>
<text x="207.1" y="8.2">PWR_FLAG</text>
<text x="216.6" y="8.9">+BATT DIODE</text>
<text x="220.5" y="7.7">D26</text>
<text x="225.4" y="11.3">SW9</text>
<text x="262" y="9.8">+BATT</text>
<text x="17.4" y="14.4">510</text>
<text x="17.5" y="17.6">R3</text>
<text x="17.5" y="13.2">R2</text>
<text x="20.5" y="13.7">12V-5V</text>
<text x="21.4" y="17">D5</text>
<text x="21.4" y="12.5">D4</text>
<text x="25.1" y="13.6">+3.3V</text>
<text x="27.2" y="14.4">330</text>
<text x="27.4" y="13.2">R7</text>
<text x="31.1" y="13.7">3V3</text>
<text x="31.3" y="12.5">D9</text>
<text x="39.3" y="12.4">C8</text>
<text x="39.4" y="13.5">0.1u</text>
<text x="42.9" y="12.4">R8</text>
<text x="42.9" y="16.2">R9</text>
<text x="43" y="13.5">3.9k</text>
<text x="43" y="17.4">680</text>
<text x="52.6" y="13.9">BD9G101G</text>
<text x="52.9" y="16.1">BS</text>
<text x="54.4" y="12.8">U2</text>
<text x="55.5" y="16.1">SW</text>
<text x="65.5" y="16.5">+12V</text>
<text x="70.7" y="14.6">22uH</text>
<text x="71.2" y="13.4">L1</text>
<text x="85.4" y="15.2">C28</text>
<text x="85.4" y="16.4">10u</text>
<text x="86.9" y="12.9">V_IN V_OUT</text>
<text x="89.9" y="15.3" transform="rotate(-90 89.9 15.3)">GND</text>
<text x="96.9" y="15.2">C31</text>
<text x="96.9" y="16.4">22u</text>
<text x="107.4" y="17.1">GND</text>
<text x="108.1" y="13.7">Control-Power_SW</text>
<text x="111.1" y="12.5">SW5</text>
<text x="119.8" y="16.7">FET_P</text>
<text x="119.9" y="15.5">Q3</text>
<text x="123.2" y="16.5">+5V</text>
<text x="132.8" y="17.4">R53</text>
<text x="134.1" y="14">1</text>
<text x="138.2" y="14.1">FET_P</text>
<text x="138.3" y="13">Q4</text>
<text x="152.4" y="13.6">GND</text>
<text x="157.7" y="12.6">5Vin</text>
<text x="170.9" y="13">+12V PWR_FLAG</text>
<text x="182.6" y="16.5">C42</text>
<text x="182.7" y="17.7">470u</text>
<text x="184" y="13.3">TRM</text>
<text x="184" y="15.2">+Vout</text>
<text x="190" y="15.2">+Vin</text>
<text x="190.2" y="13.3">-Vin</text>
<text x="197.2" y="16.5">C52</text>
<text x="197.3" y="17.7">220u</text>
<text x="206.1" y="17.3" transform="rotate(-90 206.1 17.3)">1</text>
<text x="206.1" y="13.5" transform="rotate(-90 206.1 13.5)">2</text>
<text x="207.3" y="17.3" transform="rotate(-90 207.3 17.3)">3</text>
<text x="207.3" y="13.5" transform="rotate(-90 207.3 13.5)">4</text>
<text x="208.7" y="16">FUSE</text>
<text x="208.8" y="14.9">J25</text>
<text x="224.3" y="12.4">MAIN_SW</text>
<text x="229.9" y="16.5">PWR_FLAG</text>
<text x="230.6" y="17.5">R82</text>
<text x="235.4" y="14.1">FET_P</text>
<text x="235.4" y="13">Q2</text>
<text x="251.4" y="12.1">C5</text>
<text x="251.5" y="17.8">C81</text>
<text x="251.5" y="13.2">0.1u</text>
<text x="257.3" y="13.3">MOTOR0</text>
<text x="257.4" y="12.1">J17</text>
<text x="257.4" y="17.8">J18</text>
<text x="262" y="15.5">+BATT</text>
<text x="263.2" y="14">GNDPWR</text>
<text x="268.6" y="13.3">BATT_IN</text>
<text x="268.8" y="12.1">J23</text>
<text x="268.8" y="17.8">J24</text>
<text x="15.3" y="22.5">+12V</text>
<text x="17.2" y="23.2">1.2k</text>
<text x="17.4" y="18.8">510</text>
<text x="17.5" y="22.1">R4</text>
<text x="21.2" y="18.1">5Vc</text>
<text x="21.2" y="22.6">12V</text>
<text x="21.4" y="21.4">D6</text>
<text x="29.2" y="23.4">SWD</text>
<text x="29.8" y="22.3">J3</text>
<text x="32.7" y="18">GND</text>
<text x="36.4" y="23">JP1</text>
<text x="41" y="20.9">GND</text>
<text x="52.9" y="18.7">GND</text>
<text x="52.9" y="21.2">FB</text>
<text x="55.7" y="21.2">EN</text>
<text x="56.1" y="18.7">IN</text>
<text x="62.9" y="20">C15</text>
<text x="62.9" y="21.2">4.7u</text>
<text x="76.5" y="18.7">C20</text>
<text x="76.6" y="19.9">10u</text>
<text x="88.6" y="20.9">GND</text>
<text x="130.8" y="22.2">GND</text>
<text x="132.8" y="18.6">10k</text>
<text x="180.1" y="21.2">GND</text>
<text x="188.9" y="23.5">+BATT</text>
<text x="191.3" y="23">R65</text>
<text x="194.8" y="23.5">BATT</text>
<text x="195.2" y="22.4">D36</text>
<text x="198.7" y="21">GNDPWR</text>
<text x="200.1" y="23.5">+5P</text>
<text x="201.8" y="23">R68</text>
<text x="205.6" y="22.4">D46</text>
<text x="205.7" y="23.5">5Vp</text>
<text x="227.6" y="21.9">GNDPWR</text>
<text x="230.6" y="18.6">10k</text>
<text x="251.5" y="23.5">C82</text>
<text x="251.5" y="18.9">0.1u</text>
<text x="257.3" y="19">MOTOR1</text>
<text x="257.4" y="23.6">J19</text>
<text x="263.2" y="19.7">GNDPWR</text>
<text x="268.6" y="19">BATT_IN</text>
<text x="22.9" y="26.9">GND</text>
<text x="31.8" y="27.2">GND</text>
<text x="35" y="24.1">SWD_Vdd</text>
<text x="45.1" y="24.1">+3.3V</text>
<text x="74" y="24.7">GND</text>
<text x="109.5" y="24.4">+3.3V</text>
<text x="112.1" y="27.9">C11</text>
<text x="112.2" y="29.1">0.1u</text>
<text x="116.5" y="29.1">1u</text>
<text x="116.5" y="27.9">C14</text>
<text x="121" y="27.9">C16</text>
<text x="121" y="29.1">0.1u</text>
<text x="125.4" y="27.9">C17</text>
<text x="125.5" y="29.1">0.1u</text>
<text x="129.9" y="27.9">C18</text>
<text x="129.9" y="29.1">0.1u</text>
<text x="134.3" y="27.9">C21</text>
<text x="134.4" y="29.1">0.1u</text>
<text x="138.8" y="27.9">C24</text>
<text x="138.8" y="29.1">0.1u</text>
<text x="143.2" y="27.9">C29</text>
<text x="143.3" y="29.1">0.1u</text>
<text x="147.7" y="27.9">C30</text>
<text x="147.7" y="29.1">4.7u</text>
<text x="191.2" y="24.2">2.2k</text>
<text x="199.8" y="27.9">+12P</text>
<text x="201.7" y="28.6">1.2k</text>
<text x="201.8" y="27.5">R83</text>
<text x="201.8" y="24.2">510</text>
<text x="205.4" y="28">12Vp</text>
<text x="205.6" y="26.8">D57</text>
<text x="216.4" y="29.3">J16</text>
<text x="220.8" y="27">+12P</text>
<text x="228.7" y="27.9">N.O</text>
<text x="228.8" y="26.6">N.C</text>
<text x="251.5" y="29.2">C83</text>
<text x="251.5" y="24.7">0.1u</text>
<text x="257.3" y="24.7">MOTOR2</text>
<text x="257.4" y="29.3">J20</text>
<text x="12.8" y="35.9">Y1</text>
<text x="60.6" y="31.7">+3.3V</text>
<text x="145.1" y="32.6">GND</text>
<text x="191.2" y="33.1">2.2k</text>
<text x="191.3" y="31.9">R67</text>
<text x="194.9" y="32.4">MAIN</text>
<text x="195.2" y="35.7">D48</text>
<text x="195.2" y="31.3">D38</text>
<text x="206.3" y="32.1">GNDPWR</text>
<text x="212.4" y="30.4">EMERGENCY</text>
<text x="251.5" y="34.9">C84</text>
<text x="251.5" y="30.4">0.1u</text>
<text x="257.3" y="30.4">MOTOR3</text>
<text x="257.4" y="35">J21</text>
<text x="12.2" y="37.1">8MHz</text>
<text x="12.7" y="40.6">C1</text>
<text x="12.7" y="41.8">22p</text>
<text x="17.1" y="40.6">C3</text>
<text x="17.2" y="41.8">22p</text>
<text x="21.9" y="41.8">GND</text>
<text x="24" y="38.2">10k</text>
<text x="24.2" y="37">R5</text>
<text x="31" y="39.6">BOOT0</text>
<text x="61.9" y="40.8" transform="rotate(-90 61.9 40.8)">VREF+</text>
<text x="68.3" y="40.4" transform="rotate(-90 68.3 40.4)">VDDA</text>
<text x="81" y="39.8" transform="rotate(-90 81 39.8)">VDD</text>
<text x="84.8" y="39.8" transform="rotate(-90 84.8 39.8)">VDD</text>
<text x="88.6" y="39.8" transform="rotate(-90 88.6 39.8)">VDD</text>
<text x="92.4" y="39.8" transform="rotate(-90 92.4 39.8)">VDD</text>
<text x="96.2" y="39.8" transform="rotate(-90 96.2 39.8)">VDD</text>
<text x="100" y="39.8" transform="rotate(-90 100 39.8)">VDD</text>
<text x="106.4" y="40.3" transform="rotate(-90 106.4 40.3)">VBAT</text>
<text x="128.4" y="39.6">PE0/TIM4_ETR/FSMC_NBL0/DCMI_D2/EVENTOUT</text>
<text x="132.9" y="40.9">PE1/FSMC_NBL1/DCMI_D3/EVENTOUT</text>
<text x="180.2" y="41.2">C43</text>
<text x="191.2" y="37.5">2.2k</text>
<text x="191.3" y="36.4">R81</text>
<text x="192.9" y="36.9">MOTOR_BATT</text>
<text x="195.8" y="41">GNDPWR</text>
<text x="222.6" y="37.2">EMERGENCY_SW</text>
<text x="225.4" y="36">SW8</text>
<text x="230.3" y="41">R87</text>
<text x="234.7" y="40.2">FET_N</text>
<text x="234.8" y="39.1">Q11</text>
<text x="240.3" y="37.4">JP2</text>
<text x="240.3" y="38.6">Relay_JP</text>
<text x="251.5" y="40.6">C85</text>
<text x="251.5" y="36.1">0.1u</text>
<text x="251.5" y="41.8">0.1u</text>
<text x="257.3" y="36.1">MOTOR4</text>
<text x="257.3" y="41.9">MOTOR5</text>
<text x="257.4" y="40.7">J22</text>
<text x="11.9" y="48">RESET</text>
<text x="12.4" y="46.8">SW1</text>
<text x="12.4" y="45.3">GND</text>
<text x="31" y="44.7">PH0/OSC_IN/EVENTOUT</text>
<text x="31" y="42.2">NRST</text>
<text x="123.7" y="47.2">PE6/TRACED3_/_FSMC_A22/TIM9_CH2/DCMI_D7/EVENTOUT</text>
<text x="124.7" y="46">PE5/TRACED2/FSMC_A21/TIM9_CH1/DCMI_D6/EVENTOUT</text>
<text x="126.2" y="42.2">PE2/TRACECLK/FSMC_A23/ETH_MII_TXD3/EVENTOUT</text>
<text x="129.2" y="44.7">PE4/TRACED1/FSMC_A20/DCMI_D4/EVENTOUT</text>
<text x="133.3" y="43.4">PE3/TRACED0/FSMC_A19/EVENTOUT</text>
<text x="179.5" y="42.4">15000p</text>
<text x="199.5" y="47.1">L2</text>
<text x="208.1" y="47.6">+12P</text>
<text x="218.5" y="47.6">+5P</text>
<text x="230.3" y="42.1">10k</text>
<text x="237.1" y="45.4">GNDPWR</text>
<text x="12.5" y="52.2">0.1u</text>
<text x="12.8" y="51">C2</text>
<text x="31" y="52.3">PH1/OSC_OUT/EVENTOUT</text>
<text x="132.6" y="52.3">PE10/FSMC_D7/TIM1_CH2N/EVENTOUT</text>
<text x="133.1" y="49.8">PE8/FSMC_D5/TIM1_CH1N/EVENTOUT</text>
<text x="133.2" y="53.6">PE11/FSMC_D8/TIM1_CH2/EVENTOUT</text>
<text x="133.7" y="48.5">PE7/FSMC_D4/TIM1_ETR/EVENTOUT</text>
<text x="133.7" y="51">PE9/FSMC_D6/TIM1_CH1/EVENTOUT</text>
<text x="169.3" y="53.7">R57</text>
<text x="172.8" y="53.7">R58</text>
<text x="173.9" y="53">GNDPWR</text>
<text x="177.5" y="53.7">C41</text>
<text x="178.9" y="49.8">BST</text>
<text x="178.9" y="51">GND VCC</text>
<text x="178.9" y="52.3">FB</text>
<text x="181.8" y="52.3">EN</text>
<text x="182" y="49.8">Lx</text>
<text x="188.9" y="52.4">C50</text>
<text x="189" y="53.6">4.7u</text>
<text x="193.7" y="52.4">C51</text>
<text x="193.8" y="53.6">100u</text>
<text x="198.9" y="48.2">22uH</text>
<text x="205.1" y="51.8">C59</text>
<text x="205.1" y="52.9">10u</text>
<text x="210.5" y="51.1">C74</text>
<text x="210.6" y="52.3">4.7u</text>
<text x="220.7" y="51.1">C75</text>
<text x="220.7" y="52.3">4.7u</text>
<text x="253.7" y="52.7">C60</text>
<text x="253.8" y="53.9">470u</text>
<text x="258.8" y="52.7">C61</text>
<text x="258.9" y="53.9">470u</text>
<text x="263.9" y="52.7">C76</text>
<text x="263.9" y="53.9">4.7u</text>
<text x="268.6" y="52.7">C77</text>
<text x="268.7" y="53.9">4.7u</text>
<text x="15" y="56.4">GND</text>
<text x="132.3" y="58.7">PE15/FSMC_D12/TIM1_BKIN/EVENTOUT</text>
<text x="132.6" y="54.9">PE12/FSMC_D9/TIM1_CH3N/EVENTOUT</text>
<text x="132.7" y="56.1">PE13/FSMC_D10/TIM1_CH3/EVENTOUT</text>
<text x="132.7" y="57.4">PE14/FSMC_D11/TIM1_CH4/EVENTOUT</text>
<text x="166.3" y="58.1">GNDPWR</text>
<text x="169.4" y="54.8">510</text>
<text x="172.8" y="54.8">7.5k</text>
<text x="177.6" y="54.8">0.1u</text>
<text x="191.6" y="57.8">+12P</text>
<text x="212" y="56.8">GNDPWR</text>
<text x="243.6" y="58.4">+12P</text>
<text x="265.1" y="57.2">GNDPWR</text>
<text x="31" y="62.5">PA0/WKUP/USART2_CTS/UART4_TX/ETH_MII_CRS_/TIM2_CH1_ETR/TIM5_CH1/TIM8_ETR/EVENTOUT</text>
<text x="31" y="63.7">PA1/USART2_RTS/UART4_RX/ETH_RMII_REF_CLK/ETH_MII_RX_CLK/TIM5_CH2/TIMM2_CH2/EVENTOUT</text>
<text x="31" y="65">PA2/USART2_TX/TIM5_CH3/TIM9_CH1/TIM2_CH3/ETH_MDIO/EVENTOUT</text>
<text x="123.6" y="65">PD2/TIM3_ETR/UART5_RX/SDIO_CMD/DCMI_D11/EVENTOUT</text>
<text x="133.8" y="62.5">PD0/FSMC_D2/CAN1_RX/EVENTOUT</text>
<text x="133.9" y="63.7">PD1/FSMC_D3/CAN1_TX/EVENTOUT</text>
<text x="185.5" y="65.1">+12P</text>
<text x="190.4" y="65.7">GNDPWR</text>
<text x="194" y="61.3">C44</text>
<text x="194.1" y="62.4">0.1u</text>
<text x="198.1" y="65.1">NCP5104</text>
<text x="199.2" y="63.9">U12</text>
<text x="211.6" y="61.6">+12P</text>
<text x="218.6" y="64.4">NVMFD5C446NLT1G</text>
<text x="222.3" y="63.3">Q5</text>
<text x="237.6" y="65.7">+12P</text>
<text x="246.1" y="61.9">C62</text>
<text x="246.1" y="63.1">0.1u</text>
<text x="250.2" y="65.7">NCP5104</text>
<text x="251.3" y="64.5">U19</text>
<text x="263.6" y="62.2">+12P</text>
<text x="270.6" y="65.1">NVMFD5C446NLT1G</text>
<text x="274.1" y="63.9">Q16</text>
<text x="31" y="66.3">PA3/USART2_RX/TIM5_CH4/TIM9_CH2/TIM2_CH4/OTG_HS_ULPI_D0/ETH_MII_COL/EVENTOUT</text>
<text x="31" y="67.6">PA4/SPI1_NSS/SPI3_NSS/USART2_CK/DCMI_HSYNC/OTG_HS_SOF/I2S3_WS/EVENTOUT</text>
<text x="31" y="68.8">PA5/SPI1_SCK/OTG_HS_ULPI_CK/TIM2_CH1_ETR/TIM8_CHIN/EVENTOUT</text>
<text x="31" y="70.1">PA6/SPI1_MISO/TIM8_BKIN/TIM13_CH1/DCMI_PIXCLK/TIM3_CH1/TIM1_BKIN/EVENTOUT</text>
<text x="31" y="71.4">PA7/SPI1_MOSI/TIM8_CH1N/TIM14_CH1/TIM3_CH2/ETH_MII_RX_DV/TIM1_CH1N/RMII_CRS_DV/EVENTOUT</text>
<text x="126.5" y="71.4">PD7/USART2_CK/FSMC_NE1/FSMC_NCE2/EVENTOUT</text>
<text x="130.9" y="70.1">PD6/FSMC_NWAIT/USART2_RX/EVENTOUT</text>
<text x="131.4" y="67.6">PD4/FSMC_NOE/USART2_RTS/EVENTOUT</text>
<text x="131.5" y="66.3">PD3/FSMC_CLK/USART2_CTS/EVENTOUT</text>
<text x="131.9" y="68.8">PD5/FSMC_NWE/USART2_TX/EVENTOUT</text>
<text x="187.4" y="69.9">R62</text>
<text x="187.4" y="71">10k</text>
<text x="196.1" y="67.2">Vcc</text>
<text x="196.1" y="69.8">IN</text>
<text x="200.3" y="69.8">DRV_HO</text>
<text x="200.8" y="67.2">VBOOT</text>
<text x="208.9" y="69.2">C53</text>
<text x="209" y="68.3">FILTER</text>
<text x="209" y="70.4">4.7u</text>
<text x="209.7" y="67.2">R69</text>
<text x="218.8" y="67.9">S1</text>
<text x="218.8" y="69.1">G1</text>
<text x="218.8" y="70.4">S2</text>
<text x="218.8" y="71.7">G2</text>
<text x="224.8" y="70.4">D1_4</text>
<text x="224.8" y="66.6">D1_1</text>
<text x="224.8" y="67.9">D1_2</text>
<text x="224.8" y="69.1">D1_3</text>
<text x="224.8" y="71.7">D1_5</text>
<text x="239.5" y="70.5">R91</text>
<text x="239.5" y="71.6">10k</text>
<text x="242.5" y="66.4">GNDPWR</text>
<text x="248.2" y="67.9">Vcc</text>
<text x="248.2" y="70.4">IN</text>
<text x="252.3" y="70.4">DRV_HO</text>
<text x="252.9" y="67.9">VBOOT</text>
<text x="261" y="69.9">C68</text>
<text x="261" y="69">FILTER</text>
<text x="261.1" y="71">4.7u</text>
<text x="261.8" y="67.8">R94</text>
<text x="270.9" y="68.5">S1</text>
<text x="270.9" y="69.8">G1</text>
<text x="270.9" y="71.1">S2</text>
<text x="276.9" y="71.1">D1_4</text>
<text x="276.9" y="67.2">D1_1</text>
<text x="276.9" y="68.5">D1_2</text>
<text x="276.9" y="69.8">D1_3</text>
<text x="31" y="72.6">PA8/MCO1/USART1_CK/TIM1_CH1/I2C3_SCL/OTG_FS_SOF/EVENTOUT</text>
<text x="31" y="73.9">PA9/USART1_TX/TIM1_CH2/I2C3_SMBA/DCMI_D0/EVENTOUT</text>
<text x="31" y="75.2">PA10/USART1_RX/TIM1_CH3/OTG_FS_ID/DCMI_D1/EVENTOUT</text>
<text x="31" y="76.4">PA11/USART1_CTS/CAN1_RX/TIM1_CH4_/OTG_FS_DM/EVENTOUT</text>
<text x="31" y="77.7">PA12/USART1_RTS/CAN1_TX/TIM1_ETR/OTG_FS_DP/EVENTOUT</text>
<text x="121.6" y="77.7">PD12/FSMC_ALE/FSMC_A17/TIM4_CH1/USART3_RTS/EVENTOUT</text>
<text x="126.2" y="76.4">PD11/FSMC_CLE/FSMC_A16/USART3_CTS/EVENTOUT</text>
<text x="131.7" y="75.2">PD10/FSMC_D15/USART3_CK/EVENTOUT</text>
<text x="132.2" y="73.9">PD9/FSMC_D14/USART3_RX/EVENTOUT</text>
<text x="132.3" y="72.6">PD8/FSMC_D13/USART3_TX/EVENTOUT</text>
<text x="191.6" y="77.5">+12P</text>
<text x="196.1" y="72.3">SD</text>
<text x="196.1" y="74.9">GND</text>
<text x="200.4" y="74.9">DRV_LO</text>
<text x="200.5" y="72.3">BRIDGE</text>
<text x="209" y="73.4">FILTER</text>
<text x="213.9" y="72.4">GNDPWR</text>
<text x="218.8" y="73">D2_1</text>
<text x="218.8" y="74.2">D2_2</text>
<text x="224.8" y="73">D2_3</text>
<text x="224.8" y="74.2">D2_4</text>
<text x="224.8" y="75.5">D2_5</text>
<text x="248.2" y="73">SD</text>
<text x="248.2" y="75.5">GND</text>
<text x="252.5" y="75.5">DRV_LO</text>
<text x="252.6" y="73">BRIDGE</text>
<text x="261" y="74">FILTER</text>
<text x="266" y="73">GNDPWR</text>
<text x="270.9" y="72.3">G2</text>
<text x="270.9" y="73.6">D2_1</text>
<text x="270.9" y="74.9">D2_2</text>
<text x="276.9" y="73.6">D2_3</text>
<text x="276.9" y="74.9">D2_4</text>
<text x="276.9" y="76.1">D2_5</text>
<text x="276.9" y="72.3">D1_5</text>
<text x="31" y="79">PA13/JTMS/SWDIO/EVENTOUT</text>
<text x="31" y="80.3">PA14/JTCK/SWCLK/EVENTOUT</text>
<text x="31" y="81.5">PA15/JTDI/SPI3_NSS/I2S3_WS/TIM2_CH1_ETR/SPI1_NSS/EVENTOUT</text>
<text x="127.6" y="80.3">PD14/FSMC_D0/TIM4_CH3/EVENTOUT/_EVENTOUT</text>
<text x="132.7" y="79">PD13/FSMC_A18/TIM4_CH2/EVENTOUT</text>
<text x="133.2" y="81.5">PD15/FSMC_D1/TIM4_CH4/EVENTOUT</text>
<text x="192.4" y="78.1">GNDPWR</text>
<text x="194" y="81">C45</text>
<text x="194.1" y="82.1">0.1u</text>
<text x="199.2" y="83.6">U13</text>
<text x="211.6" y="81.3">+12P</text>
<text x="222.3" y="83">Q6</text>
<text x="243.6" y="78.1">+12P</text>
<text x="244.4" y="78.7">GNDPWR</text>
<text x="246.1" y="81.6">C63</text>
<text x="246.1" y="82.8">0.1u</text>
<text x="263.6" y="81.9">+12P</text>
<text x="274.1" y="83.6">Q17</text>
<text x="31" y="85.3">PB0/TIM3_CH3/TIM8_CH2N/OTG_HS_ULPI_D1/ETH_MII_RXD2/TIM1_CH2N/EVENTOUT</text>
<text x="31" y="86.6">PB1/TIM3_CH4/TIM8_CH3N/OTG_HS_ULPI_D2/ETH_MII_RXD3/OTG_HS_INTN/TIM1_CH3N/EVENTOUT</text>
<text x="31" y="87.9">PB2/BOOT1/EVENTOUT</text>
<text x="31" y="89.1">PB3/JTDO/TRACESWO/SPI3_SCK/I2S3_CK/TIM2_CH2/SPI1_SCK/EVENTOUT</text>
<text x="117.6" y="89.1">PC3/SPI2_MOSI/I2S2_SD/OTG_HS_ULPI_NXT/ETH_MII_TX_CLK/EVENTOUT</text>
<text x="117.7" y="87.9">PC2/SPI2_MISO/OTG_HS_ULPI_DIR/ETH_MII_TXD2/I2S2ext_SD/EVENTOUT</text>
<text x="134" y="85.3">PC0/OTG_HS_ULPI_STP/EVENTOUT</text>
<text x="137.6" y="86.6">PC1/ETH_MDC/_EVENTOUT</text>
<text x="185.2" y="84.8">+12P</text>
<text x="187.1" y="89.5">R59</text>
<text x="190.4" y="85.4">GNDPWR</text>
<text x="196.1" y="86.9">Vcc</text>
<text x="196.1" y="89.5">IN</text>
<text x="198.1" y="84.7">NCP5104</text>
<text x="200.3" y="89.5">DRV_HO</text>
<text x="200.8" y="86.9">VBOOT</text>
<text x="208.9" y="88.9">C54</text>
<text x="209" y="88">FILTER</text>
<text x="209.7" y="86.9">R71</text>
<text x="218.6" y="84.1">NVMFD5C446NLT1G</text>
<text x="218.8" y="87.6">S1</text>
<text x="218.8" y="88.8">G1</text>
<text x="224.8" y="86.3">D1_1</text>
<text x="224.8" y="87.6">D1_2</text>
<text x="224.8" y="88.8">D1_3</text>
<text x="237.3" y="85.4">+12P</text>
<text x="242.5" y="86">GNDPWR</text>
<text x="248.2" y="87.6">Vcc</text>
<text x="250.2" y="85.4">NCP5104</text>
<text x="251.3" y="84.2">U20</text>
<text x="252.9" y="87.6">VBOOT</text>
<text x="261" y="89.5">C69</text>
<text x="261" y="88.7">FILTER</text>
<text x="261.8" y="87.5">R96</text>
<text x="270.6" y="84.7">NVMFD5C446NLT1G</text>
<text x="270.9" y="88.2">S1</text>
<text x="270.9" y="89.5">G1</text>
<text x="276.9" y="86.9">D1_1</text>
<text x="276.9" y="88.2">D1_2</text>
<text x="276.9" y="89.5">D1_3</text>
<text x="31" y="90.4">PB4/NJTRST/SPI3_MISO/TIM3_CH1/SPI1_MISO/I2S3ext_SD/EVENTOUT</text>
<text x="31" y="91.7">PB5/I2C1_SMBA/CAN2_RX/OTG_HS_ULPI_D7/ETH_PPS_OUT/TIM3_CH2/SPI1_MOSI/SPI3_MOSI/DCMI_D10/I2S3_SD/EVENTOUT</text>
<text x="31" y="93">PB6/I2C1_SCL/TIM4_CH1/CAN2_TX/DCMI_D5/USART1_TX/EVENTOUT</text>
<text x="31" y="94.2">PB7/I2C1_SDA/FSMC_NL/DCMI_VSYNC/USART1_RX/TIM4_CH2/EVENTOUT</text>
<text x="31" y="95.5">PB8/TIM4_CH3/SDIO_D4/TIM10_CH1/DCMI_D6/ETH_MII_TXD3/I2C1_SCL/CAN1_RX/EVENTOUT</text>
<text x="115.3" y="94.2">PC7/I2S3_MCK/TIM8_CH2/SDIO_D7/USART6_RX/DCMI_D1/TIM3_CH2/EVENTOUT</text>
<text x="115.4" y="93">PC6/I2S2_MCK/TIM8_CH1/SDIO_D6/USART6_TX/DCMI_D0/TIM3_CH1/EVENTOUT</text>
<text x="119.8" y="95.5">PC8/TIM8_CH3/SDIO_D0/TIM3_CH3/USART6_CK/DCMI_D2/EVENTOUT</text>
<text x="127.8" y="90.4">PC4/ETH_RMII_RX_D0/ETH_MII_RX_D0/EVENTOUT</text>
<text x="127.8" y="91.7">PC5/ETH_RMII_RX_D1/ETH_MII_RX_D1/EVENTOUT</text>
<text x="187.1" y="90.7">10k</text>
<text x="196.1" y="92">SD</text>
<text x="196.1" y="94.5">GND</text>
<text x="200.4" y="94.5">DRV_LO</text>
<text x="200.5" y="92">BRIDGE</text>
<text x="209" y="93.1">FILTER</text>
<text x="209" y="90.1">4.7u</text>
<text x="213.9" y="92.1">GNDPWR</text>
<text x="218.8" y="90.1">S2</text>
<text x="218.8" y="91.4">G2</text>
<text x="218.8" y="92.6">D2_1</text>
<text x="218.8" y="93.9">D2_2</text>
<text x="224.8" y="90.1">D1_4</text>
<text x="224.8" y="92.6">D2_3</text>
<text x="224.8" y="93.9">D2_4</text>
<text x="224.8" y="95.2">D2_5</text>
<text x="224.8" y="91.4">D1_5</text>
<text x="239.2" y="90.2">R88</text>
<text x="239.2" y="91.3">10k</text>
<text x="248.2" y="90.1">IN</text>
<text x="248.2" y="92.6">SD</text>
<text x="248.2" y="95.2">GND</text>
<text x="252.3" y="90.1">DRV_HO</text>
<text x="252.5" y="95.2">DRV_LO</text>
<text x="252.6" y="92.6">BRIDGE</text>
<text x="261" y="93.7">FILTER</text>
<text x="261.1" y="90.7">4.7u</text>
<text x="266" y="92.7">GNDPWR</text>
<text x="270.9" y="90.7">S2</text>
<text x="270.9" y="92">G2</text>
<text x="270.9" y="93.3">D2_1</text>
<text x="270.9" y="94.5">D2_2</text>
<text x="276.9" y="90.7">D1_4</text>
<text x="276.9" y="93.3">D2_3</text>
<text x="276.9" y="94.5">D2_4</text>
<text x="276.9" y="95.8">D2_5</text>
<text x="276.9" y="92">D1_5</text>
<text x="31" y="98">PB10/SPI2_SCK/I2S2_CK/I2C2_SCL/USART3_TX/OTG_HS_ULPI_D3/ETH_MII_RX_ER/TIM2_CH3/EVENTOUT</text>
<text x="31" y="99.3">PB11/I2C2_SDA/USART3_RX/OTG_HS_ULPI_D4/ETH_RMII_TX_EN/ETH_MII_TX_EN/TIM2_CH4/EVENTOUT</text>
<text x="31" y="100.6">PB12/SPI2_NSS/I2S2_WS/I2C2_SMBA/USART3_CK/TIM1_BKIN/CAN2_RX/OTG_HS_ULPI_D5/ETH_RMII_TXD0/ETH_MII_TXD0/OTG_HS_ID/EVENTOUT</text>
<text x="31" y="101.8">PB13/SPI2_SCK/I2S2_CK/USART3_CTS/TIM1_CH1N/CAN2_TX/OTG_HS_ULPI_D6/ETH_RMII_TXD1/ETH_MII_TXD1/EVENTOUT</text>
<text x="31" y="96.8">PB9/SPI2_NSS/I2S2_WS/TIM4_CH4/TIM11_CH1/SDIO_D5/DCMI_D7/I2C1_SDA/CAN1_TX/EVENTOUT</text>
<text x="113.5" y="99.3">PC11/UART4_RX/SPI3_MISO/SDIO_D3/DCMI_D4/USART3_RX/I2S3ext_SD/EVENTOUT</text>
<text x="113.9" y="96.8">PC9/I2S_CKIN/MCO2/TIM8_CH4/SDIO_D1/I2C3_SDA/DCMI_D3/TIM3_CH4/EVENTOUT</text>
<text x="114.7" y="100.6">PC12/UART5_TX/SDIO_CK/DCMI_D9/SPI3_MOSI/I2S3_SD/USART3_CK/EVENTOUT</text>
<text x="115.3" y="98">PC10/SPI3_SCK/I2S3_CK/UART4_TX/SDIO_D2/DCMI_D8/USART3_TX/EVENTOUT</text>
<text x="142.1" y="101.8">PC13/EVENTOUT</text>
<text x="191.6" y="99.4">+12P</text>
<text x="192.4" y="97.8">GNDPWR</text>
<text x="243.6" y="100">+12P</text>
<text x="244.4" y="98.4">GNDPWR</text>
<text x="31" y="103.1">PB14/SPI2_MISO/TIM1_CH2N/TIM12_CH1/OTG_HS_DM/USART3_RTS/TIM8_CH2N/I2S2ext_SD/EVENTOUT</text>
<text x="31" y="104.4">PB15/SPI2_MOSI/I2S2_SD/TIM1_CH3N/TIM8_CH3N/TIM12_CH2/OTG_HS_DP/EVENTOUT</text>
<text x="85.4" y="105.5" transform="rotate(-90 85.4 105.5)">VSSA</text>
<text x="87.9" y="105.5" transform="rotate(-90 87.9 105.5)">VSS</text>
<text x="90.5" y="105.5" transform="rotate(-90 90.5 105.5)">VSS</text>
<text x="93" y="105.5" transform="rotate(-90 93 105.5)">VSS</text>
<text x="95.6" y="105.5" transform="rotate(-90 95.6 105.5)">VSS</text>
<text x="101.9" y="105.5" transform="rotate(-90 101.9 105.5)">VCAP_1</text>
<text x="108.3" y="105.5" transform="rotate(-90 108.3 105.5)">VCAP_2</text>
<text x="136.6" y="104.4">PC15/OSC32_OUT/EVENTOUT</text>
<text x="137.6" y="103.1">PC14/OSC32_IN/EVENTOUT</text>
<text x="159.7" y="107.9">+3.3V</text>
<text x="176.6" y="107.9">+5P</text>
<text x="185.5" y="106.7">+12P</text>
<text x="190.4" y="107.3">GNDPWR</text>
<text x="194" y="102.9">C46</text>
<text x="194.1" y="104">0.1u</text>
<text x="198.1" y="106.6">NCP5104</text>
<text x="199.2" y="105.5">U14</text>
<text x="211.6" y="103.2">+12P</text>
<text x="218.6" y="106">NVMFD5C446NLT1G</text>
<text x="222.3" y="104.9">Q7</text>
<text x="237.6" y="107.3">+12P</text>
<text x="242.5" y="108">GNDPWR</text>
<text x="246.1" y="103.5">C64</text>
<text x="246.1" y="104.7">0.1u</text>
<text x="250.2" y="107.3">NCP5104</text>
<text x="251.3" y="106.1">U21</text>
<text x="263.6" y="103.8">+12P</text>
<text x="270.6" y="106.6">NVMFD5C446NLT1G</text>
<text x="274.1" y="105.5">Q12</text>
<text x="103.2" y="111.4">C32</text>
<text x="103.3" y="112.6">2.2u</text>
<text x="109.6" y="111.4">C35</text>
<text x="109.6" y="112.6">2.2u</text>
<text x="161.3" y="113.6">+3.3V</text>
<text x="162.3" y="111.4">C36</text>
<text x="162.3" y="112.6">0.1u</text>
<text x="174.3" y="113.6">+5P</text>
<text x="178.8" y="111.4">C38</text>
<text x="178.8" y="112.6">0.1u</text>
<text x="187.4" y="111.4">R63</text>
<text x="187.4" y="112.6">10k</text>
<text x="196.1" y="108.8">Vcc</text>
<text x="196.1" y="111.4">IN</text>
<text x="196.1" y="113.9">SD</text>
<text x="200.3" y="111.4">DRV_HO</text>
<text x="200.5" y="113.9">BRIDGE</text>
<text x="200.8" y="108.8">VBOOT</text>
<text x="208.9" y="110.8">C55</text>
<text x="209" y="109.9">FILTER</text>
<text x="209" y="112">4.7u</text>
<text x="209.7" y="108.8">R73</text>
<text x="213.9" y="114">GNDPWR</text>
<text x="218.8" y="109.5">S1</text>
<text x="218.8" y="110.7">G1</text>
<text x="218.8" y="112">S2</text>
<text x="218.8" y="113.3">G2</text>
<text x="224.8" y="112">D1_4</text>
<text x="224.8" y="108.2">D1_1</text>
<text x="224.8" y="109.5">D1_2</text>
<text x="224.8" y="110.7">D1_3</text>
<text x="224.8" y="113.3">D1_5</text>
<text x="239.5" y="112.1">R92</text>
<text x="239.5" y="113.2">10k</text>
<text x="248.2" y="109.5">Vcc</text>
<text x="248.2" y="112">IN</text>
<text x="252.3" y="112">DRV_HO</text>
<text x="252.9" y="109.5">VBOOT</text>
<text x="261" y="111.4">C70</text>
<text x="261" y="110.6">FILTER</text>
<text x="261.1" y="112.6">4.7u</text>
<text x="261.8" y="109.4">R98</text>
<text x="270.9" y="110.1">S1</text>
<text x="270.9" y="111.4">G1</text>
<text x="270.9" y="112.6">S2</text>
<text x="270.9" y="113.9">G2</text>
<text x="276.9" y="112.6">D1_4</text>
<text x="276.9" y="108.8">D1_1</text>
<text x="276.9" y="110.1">D1_2</text>
<text x="276.9" y="111.4">D1_3</text>
<text x="276.9" y="113.9">D1_5</text>
<text x="9.9" y="117.1">+12V</text>
<text x="11.8" y="119.5">0.1u</text>
<text x="12.1" y="118.3">C6</text>
<text x="20.4" y="117.1">+12V</text>
<text x="22.3" y="119.5">0.1u</text>
<text x="22.4" y="118.3">C10</text>
<text x="53.6" y="116.8">+3.3V</text>
<text x="59.7" y="119.1">LS1</text>
<text x="69.5" y="118.4">+3.3V</text>
<text x="78.9" y="118.7">C27</text>
<text x="78.9" y="117.4">C26</text>
<text x="79.2" y="119.8">1u</text>
<text x="79.2" y="118.6">1u</text>
<text x="84.6" y="119.3">V0</text>
<text x="102.4" y="119.2">R36</text>
<text x="107" y="116.1">GND</text>
<text x="130.5" y="114.3">+3.3V</text>
<text x="132.5" y="117.7">R54</text>
<text x="132.5" y="118.9">10k</text>
<text x="135.5" y="114.3">+3.3V</text>
<text x="137.6" y="117.7">R55</text>
<text x="137.6" y="118.9">10k</text>
<text x="141.3" y="114.3">+3.3V</text>
<text x="143.3" y="117.7">R56</text>
<text x="143.3" y="118.9">10k</text>
<text x="147" y="114.3">+3.3V</text>
<text x="149" y="117.7">R66</text>
<text x="149" y="118.9">10k</text>
<text x="159.7" y="116.1">GND</text>
<text x="165.3" y="115.8">VDD1</text>
<text x="165.3" y="117.7">A1</text>
<text x="165.3" y="119.6">A2</text>
<text x="169.5" y="115.8">VDD2</text>
<text x="170.8" y="119.6">B2</text>
<text x="170.8" y="117.7">B1</text>
<text x="175.2" y="115.9">GNDPWR</text>
<text x="191.6" y="119">+12P</text>
<text x="192.4" y="119.7">GNDPWR</text>
<text x="196.1" y="116.5">GND</text>
<text x="200.4" y="116.5">DRV_LO</text>
<text x="209" y="115">FILTER</text>
<text x="218.8" y="114.5">D2_1</text>
<text x="218.8" y="115.8">D2_2</text>
<text x="224.8" y="114.5">D2_3</text>
<text x="224.8" y="115.8">D2_4</text>
<text x="224.8" y="117.1">D2_5</text>
<text x="243.6" y="119.7">+12P</text>
<text x="248.2" y="114.5">SD</text>
<text x="248.2" y="117.1">GND</text>
<text x="252.5" y="117.1">DRV_LO</text>
<text x="252.6" y="114.5">BRIDGE</text>
<text x="261" y="115.6">FILTER</text>
<text x="266" y="114.6">GNDPWR</text>
<text x="270.9" y="115.2">D2_1</text>
<text x="270.9" y="116.5">D2_2</text>
<text x="276.9" y="115.2">D2_3</text>
<text x="276.9" y="116.5">D2_4</text>
<text x="276.9" y="117.7">D2_5</text>
<text x="18.8" y="124.1">CAN</text>
<text x="18.9" y="122.9">J4</text>
<text x="29.3" y="124.1">CAN</text>
<text x="29.4" y="122.9">J7</text>
<text x="56" y="121.5">R11</text>
<text x="56" y="122.7">120</text>
<text x="59.8" y="120.2">Speaker</text>
<text x="71.5" y="124.4">R24</text>
<text x="71.5" y="125.6">10k</text>
<text x="74.7" y="125.7">R25</text>
<text x="78.2" y="123.6">0.1u</text>
<text x="78.2" y="122.5">C25</text>
<text x="84.6" y="120.6">VOUT</text>
<text x="84.6" y="121.9">CAP1N</text>
<text x="84.6" y="123.1">CAP1P</text>
<text x="84.6" y="124.4">VDD</text>
<text x="84.6" y="125.7">VSS</text>
<text x="91" y="123.8">U4</text>
<text x="91" y="125">AQM0802</text>
<text x="102.4" y="120.3">330</text>
<text x="102.4" y="122.9">330</text>
<text x="102.4" y="121.6">330</text>
<text x="108.1" y="121.9">blue_A</text>
<text x="108.1" y="123.1">green_A</text>
<text x="108.1" y="124.4">red_A</text>
<text x="112.5" y="123.1">green_K</text>
<text x="113.1" y="121.9">blue_K</text>
<text x="113.5" y="124.4">red_K</text>
<text x="132.1" y="122.8">SW3</text>
<text x="132.1" y="124">SW0</text>
<text x="137.2" y="122.8">SW4</text>
<text x="137.2" y="124">SW1</text>
<text x="142.9" y="122.8">SW6</text>
<text x="142.9" y="124">SW2</text>
<text x="148.6" y="122.8">SW7</text>
<text x="148.6" y="124">SW3</text>
<text x="165.3" y="121.5">A3</text>
<text x="165.3" y="123.4">A4</text>
<text x="165.3" y="125.3">A5</text>
<text x="170.8" y="125.3">B5</text>
<text x="170.8" y="123.4">B4</text>
<text x="170.8" y="121.5">B3</text>
<text x="194" y="122.6">C47</text>
<text x="194.1" y="123.7">0.1u</text>
<text x="199.2" y="125.2">U15</text>
<text x="211.6" y="122.9">+12P</text>
<text x="218.6" y="125.7">NVMFD5C446NLT1G</text>
<text x="222.3" y="124.5">Q8</text>
<text x="244.4" y="120.3">GNDPWR</text>
<text x="246.1" y="123.2">C65</text>
<text x="246.1" y="124.4">0.1u</text>
<text x="251.3" y="125.8">U22</text>
<text x="263.6" y="123.5">+12P</text>
<text x="274.1" y="125.2">Q13</text>
<text x="9.8" y="127.6">+3.3V</text>
<text x="12.4" y="131.1">C4</text>
<text x="26.8" y="129.2">CAN_JP</text>
<text x="27.8" y="128.2">JP3</text>
<text x="33.5" y="128.4">R10</text>
<text x="33.5" y="129.5">120</text>
<text x="54" y="131.4">GND</text>
<text x="56.2" y="126.1">Q1</text>
<text x="56.2" y="127.2">NPN</text>
<text x="74.7" y="126.8">10k</text>
<text x="80.4" y="127.9">GND 8</text>
<text x="84.6" y="126.9">SDA</text>
<text x="84.6" y="128.2">SCL</text>
<text x="84.6" y="129.5">/RST</text>
<text x="118.1" y="126.6">GND</text>
<text x="130.5" y="128.2">GND</text>
<text x="135.6" y="128.2">GND</text>
<text x="141.3" y="128.2">GND</text>
<text x="147" y="128.2">GND</text>
<text x="161.3" y="131.4">GND</text>
<text x="165.3" y="127.2">A6</text>
<text x="165.3" y="129.2">GND1</text>
<text x="169.4" y="129.2">GND2</text>
<text x="170.8" y="127.2">B6</text>
<text x="173" y="131.1">GNDPWR</text>
<text x="185.2" y="126.3">+12P</text>
<text x="187.1" y="131.1">R60</text>
<text x="190.4" y="127">GNDPWR</text>
<text x="196.1" y="128.5">Vcc</text>
<text x="196.1" y="131.1">IN</text>
<text x="198.1" y="126.3">NCP5104</text>
<text x="200.3" y="131.1">DRV_HO</text>
<text x="200.8" y="128.5">VBOOT</text>
<text x="208.9" y="130.5">C56</text>
<text x="209" y="129.6">FILTER</text>
<text x="209" y="131.7">4.7u</text>
<text x="209.7" y="128.5">R75</text>
<text x="218.8" y="129.2">S1</text>
<text x="218.8" y="130.4">G1</text>
<text x="218.8" y="131.7">S2</text>
<text x="224.8" y="131.7">D1_4</text>
<text x="224.8" y="127.9">D1_1</text>
<text x="224.8" y="129.2">D1_2</text>
<text x="224.8" y="130.4">D1_3</text>
<text x="237.3" y="127">+12P</text>
<text x="239.2" y="131.8">R89</text>
<text x="242.5" y="127.6">GNDPWR</text>
<text x="248.2" y="129.2">Vcc</text>
<text x="248.2" y="131.7">IN</text>
<text x="250.2" y="127">NCP5104</text>
<text x="252.3" y="131.7">DRV_HO</text>
<text x="252.9" y="129.2">VBOOT</text>
<text x="261" y="131.1">C71</text>
<text x="261" y="130.2">FILTER</text>
<text x="261.5" y="129.1">R100</text>
<text x="270.6" y="126.3">NVMFD5C446NLT1G</text>
<text x="270.9" y="129.8">S1</text>
<text x="270.9" y="131.1">G1</text>
<text x="276.9" y="128.5">D1_1</text>
<text x="276.9" y="129.8">D1_2</text>
<text x="276.9" y="131.1">D1_3</text>
<text x="9.9" y="135.8">GND</text>
<text x="12.5" y="132.3">0.1u</text>
<text x="14.8" y="137.1">TXD</text>
<text x="17.4" y="133.4">MAX3051</text>
<text x="18.4" y="132.4">+3.3V</text>
<text x="18.8" y="132.3">U1</text>
<text x="19.7" y="137.9" transform="rotate(-90 19.7 137.9)">VDD</text>
<text x="70.1" y="135.2">+3.3V</text>
<text x="121" y="133.6">R40</text>
<text x="121.1" y="134.8">330</text>
<text x="121.7" y="137.5">D27</text>
<text x="126.8" y="133.6">R43</text>
<text x="126.8" y="134.8">330</text>
<text x="127.4" y="137.5">D28</text>
<text x="132.5" y="133.6">R47</text>
<text x="132.5" y="134.8">330</text>
<text x="133.1" y="137.5">D29</text>
<text x="138.2" y="133.6">R49</text>
<text x="138.3" y="134.8">330</text>
<text x="138.8" y="137.5">D30</text>
<text x="143.9" y="133.6">R51</text>
<text x="144" y="134.8">330</text>
<text x="144.5" y="137.5">D31</text>
<text x="159.7" y="134.6">+3.3V</text>
<text x="176.6" y="134.6">+5P</text>
<text x="187.1" y="132.3">10k</text>
<text x="196.1" y="133.6">SD</text>
<text x="196.1" y="136.1">GND</text>
<text x="200.4" y="136.1">DRV_LO</text>
<text x="200.5" y="133.6">BRIDGE</text>
<text x="209" y="134.7">FILTER</text>
<text x="213.9" y="133.7">GNDPWR</text>
<text x="218.8" y="133">G2</text>
<text x="218.8" y="134.2">D2_1</text>
<text x="218.8" y="135.5">D2_2</text>
<text x="224.8" y="134.2">D2_3</text>
<text x="224.8" y="135.5">D2_4</text>
<text x="224.8" y="136.8">D2_5</text>
<text x="224.8" y="133">D1_5</text>
<text x="239.2" y="132.9">10k</text>
<text x="248.2" y="134.2">SD</text>
<text x="248.2" y="136.8">GND</text>
<text x="252.5" y="136.8">DRV_LO</text>
<text x="252.6" y="134.2">BRIDGE</text>
<text x="261" y="135.3">FILTER</text>
<text x="261.1" y="132.3">4.7u</text>
<text x="266" y="134.3">GNDPWR</text>
<text x="270.9" y="132.3">S2</text>
<text x="270.9" y="133.6">G2</text>
<text x="270.9" y="134.9">D2_1</text>
<text x="270.9" y="136.1">D2_2</text>
<text x="276.9" y="132.3">D1_4</text>
<text x="276.9" y="134.9">D2_3</text>
<text x="276.9" y="136.1">D2_4</text>
<text x="276.9" y="137.4">D2_5</text>
<text x="276.9" y="133.6">D1_5</text>
<text x="14.8" y="138.4">RXD</text>
<text x="14.8" y="140.9">SHDN</text>
<text x="14.8" y="142.2">RS</text>
<text x="19.7" y="142.6" transform="rotate(-90 19.7 142.6)">GND</text>
<text x="21.4" y="138.4">CANH</text>
<text x="21.5" y="140.9">CANL</text>
<text x="48.7" y="143.5">SERIAL2</text>
<text x="50.1" y="142.3">J9</text>
<text x="58.1" y="143.5">+5V</text>
<text x="70.2" y="143.4">GND</text>
<text x="72.7" y="138.8">C19</text>
<text x="72.8" y="139.9">0.1u</text>
<text x="119.1" y="142.2">GND</text>
<text x="121.6" y="138.7">LED0</text>
<text x="124.8" y="142.2">GND</text>
<text x="127.3" y="138.7">LED1</text>
<text x="130.5" y="142.2">GND</text>
<text x="133" y="138.7">LED2</text>
<text x="136.2" y="142.2">GND</text>
<text x="138.7" y="138.7">LED3</text>
<text x="142" y="142.2">GND</text>
<text x="144.4" y="138.7">LED4</text>
<text x="159.7" y="142.8">GND</text>
<text x="161.3" y="140.3">+3.3V</text>
<text x="162.3" y="138.1">C37</text>
<text x="162.3" y="139.3">0.1u</text>
<text x="165.3" y="142.5">VDD1</text>
<text x="169.5" y="142.5">VDD2</text>
<text x="174.3" y="140.3">+5P</text>
<text x="175.2" y="142.6">GNDPWR</text>
<text x="178.8" y="138.1">C39</text>
<text x="178.8" y="139.3">0.1u</text>
<text x="191.6" y="141">+12P</text>
<text x="192.4" y="139.4">GNDPWR</text>
<text x="243.6" y="141.6">+12P</text>
<text x="244.4" y="140">GNDPWR</text>
<text x="18.5" y="146.9">GND</text>
<text x="32.7" y="147.6">+5V0.1u</text>
<text x="34.7" y="146.6">C9</text>
<text x="49.4" y="145.7">VBUS</text>
<text x="50.7" y="148.2">D+</text>
<text x="59.7" y="144.1">+3.3VD17</text>
<text x="62" y="146.1">RX</text>
<text x="62.1" y="145.1">TX</text>
<text x="65.5" y="144.6">R14</text>
<text x="65.6" y="147.7">10k</text>
<text x="65.6" y="146.8">330</text>
<text x="65.6" y="145.8">330</text>
<text x="71.3" y="146.3">Vdd</text>
<text x="71.3" y="147.3">GP0</text>
<text x="71.3" y="148.2">GP1</text>
<text x="71.3" y="149.2">nRST</text>
<text x="74.5" y="149.2">Vusb</text>
<text x="75.1" y="146.3">Vss</text>
<text x="75.5" y="147.3">D+</text>
<text x="81" y="148.5">GND</text>
<text x="82.8" y="147">+3.3V</text>
<text x="94.7" y="147">TOGGLESW0</text>
<text x="96.2" y="145.9">SW2A</text>
<text x="110.5" y="147">TOGGLESW1</text>
<text x="111.8" y="145.9">SW10A</text>
<text x="126.4" y="147">TOGGLESW2</text>
<text x="127.7" y="145.9">SW11A</text>
<text x="142.3" y="147">TOGGLESW3</text>
<text x="143.6" y="145.9">SW12A</text>
<text x="165.3" y="144.4">A1</text>
<text x="165.3" y="146.3">A2</text>
<text x="165.3" y="148.2">A3</text>
<text x="170.8" y="148.2">B3</text>
<text x="170.8" y="146.3">B2</text>
<text x="170.8" y="144.4">B1</text>
<text x="185.5" y="148.3">+12P</text>
<text x="190.4" y="148.9">GNDPWR</text>
<text x="194" y="144.5">C48</text>
<text x="194.1" y="145.6">0.1u</text>
<text x="198.1" y="148.2">NCP5104</text>
<text x="199.2" y="147.1">U16</text>
<text x="211.6" y="144.8">+12P</text>
<text x="218.6" y="147.6">NVMFD5C446NLT1G</text>
<text x="222.3" y="146.5">Q9</text>
<text x="224.8" y="149.8">D1_1</text>
<text x="237.6" y="148.9">+12P</text>
<text x="242.5" y="149.5">GNDPWR</text>
<text x="246.1" y="145.1">C66</text>
<text x="246.1" y="146.3">0.1u</text>
<text x="250.2" y="148.9">NCP5104</text>
<text x="251.3" y="147.7">U23</text>
<text x="263.6" y="145.4">+12P</text>
<text x="270.6" y="148.2">NVMFD5C446NLT1G</text>
<text x="274.1" y="147.1">Q14</text>
<text x="41.4" y="152.3">SERIAL0</text>
<text x="41.4" y="151.2">J6</text>
<text x="48.9" y="151.2" transform="rotate(-90 48.9 151.2)">Shield</text>
<text x="48.9" y="155.5">GND</text>
<text x="50.2" y="151.2" transform="rotate(-90 50.2 151.2)">GND</text>
<text x="51" y="150.7">ID</text>
<text x="71.3" y="150.1">URx</text>
<text x="71.3" y="151.1">UTx</text>
<text x="71.3" y="152">GP2</text>
<text x="74.8" y="151.1">SDA</text>
<text x="74.9" y="150.1">SCL</text>
<text x="74.9" y="152">GP3</text>
<text x="99.1" y="153">GND</text>
<text x="101.8" y="155.6">J1</text>
<text x="115" y="153">GND</text>
<text x="118.7" y="155.6">+3.3V</text>
<text x="130.8" y="153">GND</text>
<text x="146.7" y="153">GND</text>
<text x="165.3" y="150.1">A4</text>
<text x="165.3" y="152">A5</text>
<text x="165.3" y="153.9">A6</text>
<text x="165.3" y="155.8">GND1</text>
<text x="169.4" y="155.8">GND2</text>
<text x="170.8" y="153.9">B6</text>
<text x="170.8" y="152">B5</text>
<text x="170.8" y="150.1">B4</text>
<text x="187.4" y="153">R64</text>
<text x="187.4" y="154.2">10k</text>
<text x="196.1" y="150.4">Vcc</text>
<text x="196.1" y="153">IN</text>
<text x="196.1" y="155.5">SD</text>
<text x="200.3" y="153">DRV_HO</text>
<text x="200.5" y="155.5">BRIDGE</text>
<text x="200.8" y="150.4">VBOOT</text>
<text x="208.9" y="152.4">C57</text>
<text x="209" y="151.5">FILTER</text>
<text x="209" y="153.6">4.7u</text>
<text x="209.7" y="150.4">R77</text>
<text x="213.9" y="155.6">GNDPWR</text>
<text x="218.8" y="151.1">S1</text>
<text x="218.8" y="152.3">G1</text>
<text x="218.8" y="153.6">S2</text>
<text x="218.8" y="154.9">G2</text>
<text x="224.8" y="153.6">D1_4</text>
<text x="224.8" y="151.1">D1_2</text>
<text x="224.8" y="152.3">D1_3</text>
<text x="224.8" y="154.9">D1_5</text>
<text x="239.5" y="153.7">R93</text>
<text x="239.5" y="154.8">10k</text>
<text x="248.2" y="151.1">Vcc</text>
<text x="248.2" y="153.6">IN</text>
<text x="252.3" y="153.6">DRV_HO</text>
<text x="252.9" y="151.1">VBOOT</text>
<text x="261" y="153">C72</text>
<text x="261" y="152.2">FILTER</text>
<text x="261.1" y="154.2">4.7u</text>
<text x="261.5" y="151">R102</text>
<text x="270.9" y="151.7">S1</text>
<text x="270.9" y="153">G1</text>
<text x="270.9" y="154.2">S2</text>
<text x="270.9" y="155.5">G2</text>
<text x="276.9" y="154.2">D1_4</text>
<text x="276.9" y="150.4">D1_1</text>
<text x="276.9" y="151.7">D1_2</text>
<text x="276.9" y="153">D1_3</text>
<text x="276.9" y="155.5">D1_5</text>
<text x="10.6" y="161.6">R26</text>
<text x="15" y="161.6">R84</text>
<text x="19.4" y="161.6">R85</text>
<text x="23.9" y="161.6">R86</text>
<text x="28.4" y="161.6">R106</text>
<text x="32.8" y="161.6">R107</text>
<text x="37.3" y="161.6">R108</text>
<text x="41.7" y="161.6">R109</text>
<text x="88" y="160.7">FILTER</text>
<text x="88" y="162">FILTER</text>
<text x="88.7" y="159.6">R46</text>
<text x="88.7" y="160.8">R48</text>
<text x="93.9" y="160.9">DAT2</text>
<text x="100.4" y="156.8">microSD</text>
<text x="121.3" y="159.1">C40</text>
<text x="121.4" y="160.2">0.1u</text>
<text x="125.7" y="159.1">C79</text>
<text x="125.8" y="160.2">0.1u</text>
<text x="130.2" y="159.1">C80</text>
<text x="130.3" y="160.2">0.1u</text>
<text x="133.6" y="158.4">+3.3V</text>
<text x="161.3" y="158">GND</text>
<text x="173" y="157.8">GNDPWR</text>
<text x="191.6" y="160.6">+12P</text>
<text x="192.4" y="161.3">GNDPWR</text>
<text x="196.1" y="158">GND</text>
<text x="200.4" y="158">DRV_LO</text>
<text x="209" y="156.6">FILTER</text>
<text x="218.8" y="156.1">D2_1</text>
<text x="218.8" y="157.4">D2_2</text>
<text x="224.8" y="156.1">D2_3</text>
<text x="224.8" y="157.4">D2_4</text>
<text x="224.8" y="158.7">D2_5</text>
<text x="243.6" y="161.3">+12P</text>
<text x="244.4" y="161.9">GNDPWR</text>
<text x="248.2" y="156.1">SD</text>
<text x="248.2" y="158.7">GND</text>
<text x="252.5" y="158.7">DRV_LO</text>
<text x="252.6" y="156.1">BRIDGE</text>
<text x="261" y="157.2">FILTER</text>
<text x="266" y="156.2">GNDPWR</text>
<text x="270.9" y="156.8">D2_1</text>
<text x="270.9" y="158">D2_2</text>
<text x="276.9" y="156.8">D2_3</text>
<text x="276.9" y="158">D2_4</text>
<text x="276.9" y="159.3">D2_5</text>
<text x="10.6" y="162.7">330</text>
<text x="11.1" y="166.6">LED0</text>
<text x="11.1" y="165.4">D1</text>
<text x="15.1" y="162.7">330</text>
<text x="15.5" y="166.6">LED1</text>
<text x="15.6" y="165.4">D2</text>
<text x="19.5" y="162.7">330</text>
<text x="20" y="166.6">LED2</text>
<text x="20" y="165.4">D7</text>
<text x="24" y="162.7">330</text>
<text x="24.4" y="166.6">LED3</text>
<text x="24.5" y="165.4">D10</text>
<text x="28.4" y="162.7">330</text>
<text x="28.9" y="166.6">LED4</text>
<text x="28.9" y="165.4">D11</text>
<text x="32.8" y="162.7">330</text>
<text x="33.3" y="166.6">LED5</text>
<text x="33.4" y="165.4">D13</text>
<text x="37.3" y="162.7">330</text>
<text x="37.8" y="166.6">LED6</text>
<text x="37.8" y="165.4">D21</text>
<text x="41.7" y="162.7">330</text>
<text x="42.2" y="166.6">LED7</text>
<text x="42.3" y="165.4">D22</text>
<text x="51.5" y="167.6">GND</text>
<text x="55.4" y="163.4">2</text>
<text x="55.4" y="165.3">C</text>
<text x="55.4" y="167.3">1</text>
<text x="60.1" y="165.3">C</text>
<text x="60.3" y="167.3">4</text>
<text x="60.3" y="163.4">8</text>
<text x="62.9" y="167.6">GND</text>
<text x="78.7" y="166.4">+3.3V</text>
<text x="88" y="167.1">FILTER</text>
<text x="88" y="164.5">FILTER</text>
<text x="88.7" y="165.9">R39</text>
<text x="88.7" y="163.4">R50</text>
<text x="90.5" y="162.5">+3.3V</text>
<text x="93.9" y="162.2">DAT3/CD</text>
<text x="93.9" y="163.4">CMD</text>
<text x="93.9" y="164.7">VDD</text>
<text x="93.9" y="166">CLK</text>
<text x="93.9" y="167.3">VSS</text>
<text x="117.8" y="163.5">+3.3V</text>
<text x="119.8" y="163.1">R41</text>
<text x="119.9" y="164.2">10k</text>
<text x="127.5" y="165.7">MCLR</text>
<text x="127.7" y="163.8">GND</text>
<text x="134.9" y="166.3" transform="rotate(-90 134.9 166.3)">Vdd</text>
<text x="136.2" y="166.3" transform="rotate(-90 136.2 166.3)">Vdd</text>
<text x="137.5" y="166.9" transform="rotate(-90 137.5 166.9)">AVdd</text>
<text x="145.5" y="166.9">PGEC3_AN1_C3IND_Vref-_RP6_CTED2_CN3_RA1</text>
<text x="145.7" y="165.7">PGED3_AN0_C3INC_Vref+_RP5_CTED1CN2_RA0</text>
<text x="185.2" y="167.9">+12P</text>
<text x="194" y="164.2">C49</text>
<text x="194.1" y="165.3">0.1u</text>
<text x="198.1" y="167.9">NCP5104</text>
<text x="199.2" y="166.8">U17</text>
<text x="211.6" y="164.4">+12P</text>
<text x="218.6" y="167.3">NVMFD5C446NLT1G</text>
<text x="222" y="166.1">Q10</text>
<text x="246.1" y="164.8">C67</text>
<text x="246.1" y="165.9">0.1u</text>
<text x="251.3" y="167.4">U24</text>
<text x="263.6" y="165.1">+12P</text>
<text x="270.6" y="167.9">NVMFD5C446NLT1G</text>
<text x="274.1" y="166.8">Q15</text>
<text x="8.6" y="170.1">GND</text>
<text x="13.1" y="170.1">GND</text>
<text x="17.5" y="170.1">GND</text>
<text x="21.9" y="170.1">GND</text>
<text x="26.4" y="170.1">GND</text>
<text x="30.8" y="170.1">GND</text>
<text x="35.3" y="170.1">GND</text>
<text x="39.7" y="170.1">GND</text>
<text x="80.7" y="169.8">R45</text>
<text x="80.7" y="171">10k</text>
<text x="93.9" y="171.1">DET_A</text>
<text x="93.9" y="168.5">DAT0</text>
<text x="93.9" y="169.8">DAT1</text>
<text x="93.9" y="172.3">DET_B</text>
<text x="107.4" y="172.3">SHIELD</text>
<text x="122.6" y="168.6">+5V</text>
<text x="127.5" y="168.2">Vusb</text>
<text x="127.5" y="170.7">Vbus</text>
<text x="127.5" y="173.3">PGED2_D+_RP10_CN16_RB10</text>
<text x="161.9" y="172">TMS_RA10</text>
<text x="162.4" y="169.5">TDO_RA8</text>
<text x="162.4" y="168.2">TCK_RA7</text>
<text x="162.8" y="170.7">TDI_RA9</text>
<text x="187.1" y="172.7">R61</text>
<text x="187.1" y="173.9">10k</text>
<text x="190.4" y="168.6">GNDPWR</text>
<text x="196.1" y="170.1">Vcc</text>
<text x="196.1" y="172.7">IN</text>
<text x="200.3" y="172.7">DRV_HO</text>
<text x="200.8" y="170.1">VBOOT</text>
<text x="208.9" y="172.1">C58</text>
<text x="209" y="171.2">FILTER</text>
<text x="209" y="173.2">4.7u</text>
<text x="209.7" y="170">R79</text>
<text x="218.8" y="170.7">S1</text>
<text x="218.8" y="172">G1</text>
<text x="218.8" y="173.3">S2</text>
<text x="224.8" y="173.3">D1_4</text>
<text x="224.8" y="169.5">D1_1</text>
<text x="224.8" y="170.7">D1_2</text>
<text x="224.8" y="172">D1_3</text>
<text x="237.3" y="168.6">+12P</text>
<text x="239.2" y="173.4">R90</text>
<text x="242.5" y="169.2">GNDPWR</text>
<text x="248.2" y="170.7">Vcc</text>
<text x="248.2" y="173.3">IN</text>
<text x="250.2" y="168.6">NCP5104</text>
<text x="252.3" y="173.3">DRV_HO</text>
<text x="252.9" y="170.7">VBOOT</text>
<text x="261" y="172.7">C73</text>
<text x="261" y="171.8">FILTER</text>
<text x="261.1" y="173.9">4.7u</text>
<text x="261.5" y="170.7">R104</text>
<text x="270.9" y="171.4">S1</text>
<text x="270.9" y="172.7">G1</text>
<text x="270.9" y="173.9">S2</text>
<text x="276.9" y="173.9">D1_4</text>
<text x="276.9" y="170.1">D1_1</text>
<text x="276.9" y="171.4">D1_2</text>
<text x="276.9" y="172.7">D1_3</text>
<text x="21.2" y="175.6">+3.3V</text>
<text x="24.8" y="174.6">C7</text>
<text x="24.9" y="175.7">1u</text>
<text x="24.9" y="179.4">J5</text>
<text x="48.7" y="176.8">+12V</text>
<text x="50.4" y="177.1">VALVE_JP</text>
<text x="51.9" y="176">JP4</text>
<text x="55.1" y="178.4">C12</text>
<text x="55.3" y="176.8">+5V</text>
<text x="55.4" y="179.5">1u</text>
<text x="64.7" y="178.7">+3.3V</text>
<text x="77" y="179">C22</text>
<text x="89.2" y="178.7">+3.3V</text>
<text x="89.6" y="176.1">GND</text>
<text x="101.4" y="179">C33</text>
<text x="127.5" y="177.1">AN4_C1NB_SDA2_RP2_CN6_RB2</text>
<text x="127.5" y="178.4">AN5_C1INA_RTCC_SCL2_RP3_CN7_RB3</text>
<text x="127.5" y="174.6">PGEC2_D-_RP11_CN15_RB11</text>
<text x="149.9" y="179.6">AN11_C1INC_RP13_REFO_CN13_RB13</text>
<text x="150.7" y="175.8">PGEDC1_AN3_C2INA_RP1_CN5_RB1</text>
<text x="151.4" y="174.6">PGED1_AN2_C2INB_RP0_CN4_RB0</text>
<text x="157.4" y="178.4">RP7_INT0_CN23_RB7</text>
<text x="158.7" y="177.1">CN27_USBID_RB5</text>
<text x="171.8" y="178.9">D49</text>
<text x="171.8" y="177.6">D37</text>
<text x="175.7" y="178.3">R42</text>
<text x="175.8" y="179.5">330</text>
<text x="177.5" y="178.7">+3.3V</text>
<text x="196.1" y="175.2">SD</text>
<text x="196.1" y="177.7">GND</text>
<text x="200.4" y="177.7">DRV_LO</text>
<text x="200.5" y="175.2">BRIDGE</text>
<text x="209" y="176.3">FILTER</text>
<text x="213.9" y="175.3">GNDPWR</text>
<text x="218.8" y="174.6">G2</text>
<text x="218.8" y="175.8">D2_1</text>
<text x="218.8" y="177.1">D2_2</text>
<text x="224.8" y="175.8">D2_3</text>
<text x="224.8" y="177.1">D2_4</text>
<text x="224.8" y="178.4">D2_5</text>
<text x="224.8" y="174.6">D1_5</text>
<text x="239.2" y="174.5">10k</text>
<text x="248.2" y="175.8">SD</text>
<text x="248.2" y="178.4">GND</text>
<text x="252.5" y="178.4">DRV_LO</text>
<text x="252.6" y="175.8">BRIDGE</text>
<text x="261" y="176.9">FILTER</text>
<text x="266" y="175.9">GNDPWR</text>
<text x="270.9" y="175.2">G2</text>
<text x="270.9" y="176.5">D2_1</text>
<text x="270.9" y="177.7">D2_2</text>
<text x="276.9" y="176.5">D2_3</text>
<text x="276.9" y="177.7">D2_4</text>
<text x="276.9" y="179">D2_5</text>
<text x="276.9" y="175.2">D1_5</text>
<text x="23.4" y="180.6">ADC_Vdd</text>
<text x="39.2" y="186">IN1</text>
<text x="39.5" y="183.8">TBD62083A</text>
<text x="41.1" y="182.6">U27</text>
<text x="42.2" y="186">OUT1</text>
<text x="54.2" y="184.4">I/O_Vdd</text>
<text x="55.1" y="183.3">J10</text>
<text x="66.7" y="184.7">1k</text>
<text x="66.8" y="183.5">R12</text>
<text x="69.6" y="183.4">1k</text>
<text x="69.6" y="182.3">R18</text>
<text x="73.4" y="186">R22</text>
<text x="75.3" y="180">+5V0.1u</text>
<text x="79.1" y="184.4">GND3</text>
<text x="84" y="184.7">ENC1</text>
<text x="84" y="183.6">J11</text>
<text x="91.2" y="184.7">1k</text>
<text x="91.2" y="183.5">R28</text>
<text x="94" y="183.4">1k</text>
<text x="94.1" y="182.3">R30</text>
<text x="97.9" y="186">R34</text>
<text x="99.7" y="180">+5V0.1u</text>
<text x="103.5" y="184.4">GND3</text>
<text x="108.4" y="184.7">ENC3</text>
<text x="108.5" y="183.6">J13</text>
<text x="127.5" y="180.9">SDA1_RP9_CN21_RB9</text>
<text x="127.5" y="184.7">OSC1_CLKI_C1IND_CN30_RA2</text>
<text x="127.5" y="186">OSC0_CLK0_CN29_RA3</text>
<text x="127.5" y="182.2">SCL1_RP8_CN22_RB8</text>
<text x="145.8" y="180.9">AN10_C3INB_CVref_VBUSON_RP14_CN12_RB14</text>
<text x="148.5" y="182.2">AN9_C3INA_VBUSCHG_RP15_CN11_RB15</text>
<text x="157.5" y="184.7">AN6_RP16_CN8_RC0</text>
<text x="157.5" y="186">AN7_RP17_CN9_RC1</text>
<text x="175.8" y="180.7">330</text>
<text x="192.4" y="181">GNDPWR</text>
<text x="244.4" y="181.6">GNDPWR</text>
<text x="19.7" y="188.5">ADC</text>
<text x="19.9" y="187.4">J2</text>
<text x="39.2" y="187.3">IN2</text>
<text x="39.2" y="188.5">IN3</text>
<text x="39.2" y="189.8">IN4</text>
<text x="39.2" y="191.1">IN5</text>
<text x="42.2" y="191.1">OUT5</text>
<text x="42.2" y="189.8">OUT4</text>
<text x="42.2" y="188.5">OUT3</text>
<text x="42.2" y="187.3">OUT2</text>
<text x="49.8" y="191.1">VALVE</text>
<text x="50" y="189.9">J8</text>
<text x="64.7" y="191.4">+3.3V</text>
<text x="70.2" y="187.3">R20</text>
<text x="70.3" y="188.4">100</text>
<text x="73.5" y="187.2">100</text>
<text x="77" y="191.7">C23</text>
<text x="89.2" y="191.4">+3.3V</text>
<text x="94.7" y="187.3">R32</text>
<text x="94.8" y="188.4">100</text>
<text x="97.9" y="187.2">100</text>
<text x="101.4" y="191.7">C34</text>
<text x="120.5" y="191.7">C78</text>
<text x="127.5" y="188.5">SOCI_C2IND_RP4_CN1_RB4</text>
<text x="127.5" y="189.8">SOSCO_SCLK_T1CK_C2INC_CN0_RA4</text>
<text x="156.5" y="188.5">AN12_RP19_CN28_RC3</text>
<text x="157" y="187.3">AN8_RP18_CN10_RC2</text>
<text x="159.3" y="189.8">RP20_CN25_RC4</text>
<text x="159.3" y="191.1">RP21_CN26_RC5</text>
<text x="179.7" y="190.8">Advanced_SBDBT +5V</text>
<text x="182.9" y="189.6">J27</text>
<text x="200.6" y="188.6">J28</text>
<text x="200.7" y="189.8">PICkit3</text>
<text x="27.7" y="195.8">GND</text>
<text x="39.2" y="192.3">IN6</text>
<text x="39.2" y="193.6">IN7</text>
<text x="39.2" y="194.9">IN8</text>
<text x="39.2" y="196.1">GND</text>
<text x="42.2" y="194.9">OUT8</text>
<text x="42.2" y="193.6">OUT7</text>
<text x="42.2" y="192.3">OUT6</text>
<text x="42.5" y="196.1">COM</text>
<text x="58.1" y="197.1">GND</text>
<text x="66.7" y="197.4">1k</text>
<text x="66.8" y="196.2">R13</text>
<text x="69.6" y="196.1">1k</text>
<text x="69.6" y="195">R19</text>
<text x="75.3" y="192.7">+5V0.1u</text>
<text x="79.1" y="197.1">GND3</text>
<text x="84" y="197.4">ENC0</text>
<text x="84" y="196.3">J12</text>
<text x="91.2" y="197.4">1k</text>
<text x="91.2" y="196.2">R29</text>
<text x="94" y="196.1">1k</text>
<text x="94.1" y="195">R31</text>
<text x="99.7" y="192.7">+5V0.1u</text>
<text x="103.5" y="197.1">GND3</text>
<text x="108.4" y="197.4">ENC2</text>
<text x="108.5" y="196.3">J14</text>
<text x="120.8" y="192.9">1u</text>
<text x="127.5" y="196.1">DISVREG</text>
<text x="127.5" y="194.9">Vcap_VddCore</text>
<text x="134.9" y="196.6" transform="rotate(-90 134.9 196.6)">Vss</text>
<text x="136.2" y="196.6" transform="rotate(-90 136.2 196.6)">Vss</text>
<text x="137.5" y="196.6" transform="rotate(-90 137.5 196.6)">AVss</text>
<text x="159.3" y="192.3">RP22_CN18_RC6</text>
<text x="159.3" y="193.6">RP23_CN17_RC7</text>
<text x="159.3" y="194.9">RP24_CN20_RC8</text>
<text x="159.3" y="196.1">RP25_CN19_RC9</text>
<text x="182.5" y="193">VBUS</text>
<text x="183.8" y="195.5">D+</text>
<text x="195.8" y="193.7">PIKkit_Vdd</text>
<text x="201" y="193.7">+3.3V</text>
<text x="36.6" y="198.4">GND</text>
<text x="70.2" y="200">R21</text>
<text x="70.3" y="201.1">100</text>
<text x="73.4" y="198.7">R23</text>
<text x="73.5" y="199.9">100</text>
<text x="94.7" y="200">R33</text>
<text x="94.8" y="201.1">100</text>
<text x="97.9" y="198.7">R35</text>
<text x="97.9" y="199.9">100</text>
<text x="122.3" y="198.4">GND</text>
<text x="136.2" y="203.4">GND</text>
<text x="181.9" y="198.5" transform="rotate(-90 181.9 198.5)">Shield</text>
<text x="182" y="202.8">GND</text>
<text x="183.2" y="198.5" transform="rotate(-90 183.2 198.5)">GND</text>
</g>
<g font-size=".9">
<text x="42.5" y="10.6">FB_Control_OUT</text>
<text x="245.1" y="10.3">Motor0L</text>
<text x="42.5" y="14.4">FB_Control</text>
<text x="67.8" y="12.5">FB_Control_OUT</text>
<text x="245" y="14.1">Motor0R</text>
<text x="245.1" y="16">Motor1L</text>
<text x="45" y="20.8">FB_Control</text>
<text x="48.9" y="20.9">GND3</text>
<text x="245" y="19.8">Motor1R</text>
<text x="245.1" y="21.7">Motor2L</text>
<text x="38.7" y="29.6">RST</text>
<text x="38.7" y="28.4">SWDIO</text>
<text x="38.7" y="27.1">SWCLK</text>
<text x="245" y="25.5">Motor2R</text>
<text x="245.1" y="27.4">Motor3L</text>
<text x="245" y="31.2">Motor3R</text>
<text x="245.1" y="33.1">Motor4L</text>
<text x="7.5" y="38.9">OSC_IN</text>
<text x="15.9" y="38.9">OSC_OUT</text>
<text x="24.9" y="41.7">RST</text>
<text x="153.7" y="41.7">PE2_IO</text>
<text x="153.7" y="40.4">PE1_IO</text>
<text x="153.7" y="39.2">PE0_IO</text>
<text x="245" y="37">Motor4R</text>
<text x="245.1" y="38.9">Motor5L</text>
<text x="23.4" y="44.3">OSC_IN</text>
<text x="153.7" y="43">PE3_IO</text>
<text x="153.7" y="46.8">motor0_R_signal</text>
<text x="153.7" y="45.5">motor0_L_signal</text>
<text x="153.7" y="44.3">PE4_IO</text>
<text x="200" y="46.2">FB_OUT</text>
<text x="245" y="42.7">Motor5R</text>
<text x="8.1" y="50">RST</text>
<text x="22.4" y="51.9">OSC_OUT</text>
<text x="153.7" y="51.9">PE10_ADRESS1</text>
<text x="153.7" y="49.3">PE8_ADRESS0</text>
<text x="153.7" y="48.1">PE7_SW3</text>
<text x="153.7" y="53.1">motor5_L_signal</text>
<text x="153.7" y="50.6">motor5_R_signal</text>
<text x="153.7" y="54.4">PE12_SW2</text>
<text x="153.7" y="58.2">PE15_SW1</text>
<text x="153.7" y="57">motor4_L_signal</text>
<text x="153.7" y="55.7">motor4_R_signal</text>
<text x="176.2" y="55.7">FB_OUT</text>
<text x="19.7" y="64.6">PA2_ADC12_IN2</text>
<text x="19.7" y="65.8">PA3_ADC12_IN3</text>
<text x="20.2" y="63.3">PA0_TIM5_CH2</text>
<text x="20.2" y="62">PA0_TIM5_CH1</text>
<text x="153.7" y="63.3">CAN1_TX</text>
<text x="153.7" y="62">CAN1_RX</text>
<text x="153.7" y="64.6">PD2_DIPSW_0</text>
<text x="153.7" y="65.8">PD3_DIPSW_1</text>
<text x="19.8" y="69.7">PA6_SPI1_MISO</text>
<text x="19.8" y="70.9">PA7_SPI1_MOSI</text>
<text x="20.2" y="68.4">PA5_SPI1_SCK</text>
<text x="20.2" y="67.1">PA4_SPI1_NSS</text>
<text x="153.7" y="68.4">PD5_USART2_TX</text>
<text x="153.7" y="69.7">PD6_USART2_RX</text>
<text x="153.7" y="67.1">PD4_DIPSW_2</text>
<text x="153.7" y="70.9">PD7_DIPSW_3</text>
<text x="187.3" y="69.3">MOTOR0L_PWM 2</text>
<text x="207.3" y="71.9">Motor0L</text>
<text x="212.4" y="67.4">Motor0L</text>
<text x="239.4" y="70">MOTOR3L_PWM 2</text>
<text x="264.5" y="68.1">Motor3L</text>
<text x="18.7" y="74.7">PA10_USART1_RX</text>
<text x="19.3" y="73.5">PA9_USART1_TX</text>
<text x="21.7" y="76">PA11_LED4</text>
<text x="21.7" y="77.3">PA12_LED3</text>
<text x="22" y="72.2">PA8_BLUE</text>
<text x="153.7" y="74.7">PD10_TOGGLESW_0</text>
<text x="153.7" y="76">PD11_TOGGLESW_1</text>
<text x="153.7" y="72.2">PD8_USART3_TX</text>
<text x="153.7" y="73.5">PD9_USART3_RX</text>
<text x="153.7" y="77.3">PD12_TIM4_CH1</text>
<text x="209.7" y="72.3">R70</text>
<text x="229.9" y="72.5">Motor0L</text>
<text x="259.4" y="72.5">Motor3L</text>
<text x="261.8" y="72.9">R95</text>
<text x="281.9" y="73.1">Motor3L</text>
<text x="19.7" y="81.1">PA15_TIM2_CH1</text>
<text x="23.4" y="79.8">SWCLK</text>
<text x="23.7" y="78.5">SWDIO</text>
<text x="153.7" y="81.1">PD15_TOGGLESW_3</text>
<text x="153.7" y="79.8">PD14_TOGGLESW_2</text>
<text x="153.7" y="78.5">PD13_TIM4_CH2</text>
<text x="19.7" y="84.9">PB0_ADC12_IN8</text>
<text x="19.7" y="86.2">PB1_ADC12_IN9</text>
<text x="20.2" y="88.7">PB3_TIM2_CH2</text>
<text x="20.2" y="90">PB4_TIM3_CH1</text>
<text x="22.5" y="87.4">PB2_SW0</text>
<text x="153.7" y="84.9">PC0_ADC12_IN10</text>
<text x="153.7" y="86.2">PC1_ADC12_IN11</text>
<text x="153.7" y="87.4">PC2_ADC12_IN12</text>
<text x="153.7" y="88.7">PC3_ADC12_IN13</text>
<text x="153.7" y="90">PC4_ADC12_IN14</text>
<text x="187.2" y="89">MOTOR0R_PWM 2</text>
<text x="212.3" y="87.1">Motor0R</text>
<text x="239.3" y="89.7">MOTOR3R_PWM 2</text>
<text x="264.4" y="87.8">Motor3R</text>
<text x="16.3" y="95.1">PB8_Buzzer_TIM10_CH1</text>
<text x="20.2" y="91.2">PB5_TIM3_CH2</text>
<text x="20.2" y="93.8">PB7_I2C1_SDA</text>
<text x="20.3" y="92.5">PB6_I2C1_SCL</text>
<text x="153.7" y="91.2">PC5_ADC12_IN15</text>
<text x="153.7" y="95.1">motor1_R_signal</text>
<text x="153.7" y="92.5">motor2_R_signal</text>
<text x="153.7" y="93.8">motor2_L_signal</text>
<text x="207.3" y="91.6">Motor0R</text>
<text x="209.7" y="91.9">R72</text>
<text x="229.9" y="92.2">Motor0R</text>
<text x="259.4" y="92.2">Motor3R</text>
<text x="261.8" y="92.6">R97</text>
<text x="281.9" y="92.8">Motor3R</text>
<text x="17.9" y="96.3">PB9_SD_Connection</text>
<text x="19.8" y="100.1">PB12_ADRESS2</text>
<text x="19.8" y="101.4">PB13_ADRESS3</text>
<text x="20.8" y="98.9">PB11_GREEN</text>
<text x="22.1" y="97.6">PB10_RED</text>
<text x="153.7" y="101.4">PC13_IO</text>
<text x="153.7" y="98.9">PC11_LED1</text>
<text x="153.7" y="100.1">PC12_LED0</text>
<text x="153.7" y="97.6">PC10_LED2</text>
<text x="153.7" y="96.3">motor1_L_signal</text>
<text x="19.5" y="102.7">motor3_R_signal</text>
<text x="19.6" y="103.9">motor3_L_signal</text>
<text x="153.7" y="103.9">PC15_IO</text>
<text x="153.7" y="102.7">PC14_IO</text>
<text x="187.3" y="110.9">MOTOR1L_PWM 2</text>
<text x="207.3" y="113.5">Motor1L</text>
<text x="209.7" y="113.8">R74</text>
<text x="212.4" y="109">Motor1L</text>
<text x="239.4" y="111.6">MOTOR4L_PWM 2</text>
<text x="264.5" y="109.7">Motor4L</text>
<text x="155.1" y="119.2">motor0_R_signal</text>
<text x="155.2" y="117.3">motor0_L_signal</text>
<text x="174.9" y="117.3">MOTOR0L_PWM</text>
<text x="174.9" y="119.2">MOTOR0R_PWM</text>
<text x="229.9" y="114.1">Motor1L</text>
<text x="259.4" y="114.1">Motor4L</text>
<text x="261.8" y="114.5">R99</text>
<text x="281.9" y="114.7">Motor4L</text>
<text x="10.9" y="123.6">CAN_HGND3</text>
<text x="11" y="124.9">CAN_L</text>
<text x="21.4" y="123.6">CAN_HGND3</text>
<text x="21.5" y="124.9">CAN_L</text>
<text x="95.4" y="122.7">PB11_GREEN</text>
<text x="96.7" y="121.4">PA8_BLUE</text>
<text x="96.7" y="123.9">PB10_RED</text>
<text x="131.8" y="120.1">PB2_SW0</text>
<text x="136.8" y="120.1">PE15_SW1</text>
<text x="142.6" y="120.1">PE12_SW2</text>
<text x="148.3" y="120.1">PE7_SW3</text>
<text x="155.1" y="123">motor1_R_signal</text>
<text x="155.2" y="121.1">motor1_L_signal</text>
<text x="155.2" y="124.9">motor2_L_signal</text>
<text x="174.9" y="121.1">MOTOR1L_PWM</text>
<text x="174.9" y="123">MOTOR1R_PWM</text>
<text x="174.9" y="124.9">MOTOR2L_PWM</text>
<text x="21.7" y="130.6">CAN_H</text>
<text x="36.2" y="130.6">CAN_L</text>
<text x="40.7" y="126.2">PB8_Buzzer_TIM10_CH1</text>
<text x="63.4" y="126.5">PB7_I2C1_SDA</text>
<text x="63.5" y="127.8">PB6_I2C1_SCL</text>
<text x="115" y="131.9">PC12_LED0</text>
<text x="120.8" y="131.9">PC11_LED1</text>
<text x="126.5" y="131.9">PC10_LED2</text>
<text x="132.2" y="131.9">PA12_LED3</text>
<text x="137.9" y="131.9">PA11_LED4</text>
<text x="155.1" y="126.8">motor2_R_signal</text>
<text x="174.9" y="126.8">MOTOR2R_PWM</text>
<text x="187.2" y="130.6">MOTOR1R_PWM 2</text>
<text x="212.3" y="128.7">Motor1R</text>
<text x="239.3" y="131.2">MOTOR4R_PWM 2</text>
<text x="264.4" y="129.3">Motor4R</text>
<text x="8.9" y="137.9">CAN1_RX 4</text>
<text x="9" y="136.6">CAN1_TX 1</text>
<text x="24.8" y="137.9">7 CAN_H</text>
<text x="207.3" y="133.2">Motor1R</text>
<text x="209.7" y="133.5">R76</text>
<text x="229.9" y="133.8">Motor1R</text>
<text x="259.4" y="133.8">Motor4R</text>
<text x="261.5" y="134.2">R101</text>
<text x="281.9" y="134.4">Motor4R</text>
<text x="24.8" y="140.5">6 CAN_L</text>
<text x="155.2" y="143.9">motor3_L_signal</text>
<text x="174.9" y="143.9">MOTOR3L_PWM</text>
<text x="52.8" y="149">2 D-</text>
<text x="52.8" y="147.8">3 D+</text>
<text x="60.9" y="149.7">PD5_USART2_TX</text>
<text x="61" y="149.9">ACTIVE</text>
<text x="65.5" y="149.4">R17</text>
<text x="79.7" y="146.8">D+</text>
<text x="85.1" y="149">PD10_TOGGLESW_0</text>
<text x="101" y="149">PD11_TOGGLESW_1</text>
<text x="116.9" y="149">PD14_TOGGLESW_2</text>
<text x="132.8" y="149">PD15_TOGGLESW_3</text>
<text x="155.1" y="145.9">motor3_R_signal</text>
<text x="155.1" y="149.7">motor4_R_signal</text>
<text x="155.2" y="147.8">motor4_L_signal</text>
<text x="174.9" y="149.7">MOTOR4R_PWM</text>
<text x="174.9" y="145.9">MOTOR3R_PWM</text>
<text x="174.9" y="147.8">MOTOR4L_PWM</text>
<text x="28.7" y="153.2">PD9_USART3_RX</text>
<text x="28.8" y="151.9">PD8_USART3_TX GND3</text>
<text x="60.8" y="150.6">PD6_USART2_RX</text>
<text x="65.6" y="150.6">330</text>
<text x="155.1" y="153.5">motor5_R_signal</text>
<text x="155.2" y="151.6">motor5_L_signal</text>
<text x="174.9" y="151.6">MOTOR5L_PWM</text>
<text x="174.9" y="153.5">MOTOR5R_PWM</text>
<text x="187.3" y="152.5">MOTOR2L_PWM 2</text>
<text x="207.3" y="155.1">Motor2L</text>
<text x="209.7" y="155.4">R78</text>
<text x="212.4" y="150.6">Motor2L</text>
<text x="229.9" y="155.7">Motor2L</text>
<text x="239.4" y="153.2">MOTOR5L_PWM 2</text>
<text x="259.4" y="155.7">Motor5L</text>
<text x="264.5" y="151.3">Motor5L</text>
<text x="6.4" y="159.8">PE0_IO</text>
<text x="10.9" y="159.8">PE1_IO</text>
<text x="15.3" y="159.8">PE2_IO</text>
<text x="19.8" y="159.8">PE3_IO</text>
<text x="24.2" y="159.8">PE4_IO</text>
<text x="28.1" y="159.8">PC15_IO</text>
<text x="32.6" y="159.8">PC14_IO</text>
<text x="37" y="159.8">PC13_IO</text>
<text x="81.2" y="161.7">PA4_SPI1_NSS</text>
<text x="261.5" y="156.1">R103</text>
<text x="281.9" y="156.3">Motor5L</text>
<text x="45.6" y="163">PE10_ADRESS1</text>
<text x="46.1" y="166.8">PE8_ADRESS0</text>
<text x="63.8" y="163">PB13_ADRESS3</text>
<text x="63.8" y="166.8">PB12_ADRESS2</text>
<text x="80.7" y="163">PA7_SPI1_MOSI</text>
<text x="81.1" y="165.5">PA5_SPI1_SCK</text>
<text x="122.9" y="164.3">MCLR</text>
<text x="70.3" y="171.9">PB9_SD_Connection</text>
<text x="80.7" y="168.1">PA6_SPI1_MISO</text>
<text x="118.5" y="172.8">USB_A_D+</text>
<text x="187.2" y="172.2">MOTOR2R_PWM 2</text>
<text x="212.3" y="170.3">Motor2R</text>
<text x="239.3" y="172.8">MOTOR5R_PWM 2</text>
<text x="264.4" y="170.9">Motor5R</text>
<text x="118.8" y="174.1">USB_A_D-</text>
<text x="170.8" y="175.4">PGEC1</text>
<text x="170.8" y="174.1">PGED1</text>
<text x="207.3" y="174.7">Motor2R</text>
<text x="209.7" y="175.1">R80</text>
<text x="229.9" y="175.4">Motor2R</text>
<text x="259.4" y="175.4">Motor5R</text>
<text x="261.5" y="175.8">R105</text>
<text x="281.9" y="176">Motor5R</text>
<text x="8.7" y="185.5">PC3_ADC12_IN13</text>
<text x="8.7" y="181.7">PC0_ADC12_IN10</text>
<text x="8.7" y="183">PC1_ADC12_IN11</text>
<text x="8.7" y="184.3">PC2_ADC12_IN12</text>
<text x="34.4" y="185.5">PE0_IO 1</text>
<text x="8.7" y="189.4">PC4_ADC12_IN14</text>
<text x="8.7" y="190.6">PC5_ADC12_IN15</text>
<text x="9.2" y="186.8">PA2_ADC12_IN2</text>
<text x="9.2" y="188.1">PA3_ADC12_IN3</text>
<text x="9.2" y="191.9">PB0_ADC12_IN8</text>
<text x="33.8" y="191.9">PC15_IO 6</text>
<text x="34.4" y="188.1">PE2_IO 3</text>
<text x="34.4" y="189.4">PE3_IO 4</text>
<text x="34.4" y="190.6">PE4_IO 5</text>
<text x="34.4" y="186.8">PE1_IO 2</text>
<text x="73" y="188.1">PA0_TIM5_CH2</text>
<text x="73" y="189.4">PA0_TIM5_CH1</text>
<text x="97.5" y="189.4">PA15_TIM2_CH1</text>
<text x="97.5" y="188.1">PB3_TIM2_CH2</text>
<text x="170.8" y="191.9">PA10_USART1_RX</text>
<text x="9.2" y="193.2">PB1_ADC12_IN9</text>
<text x="33.8" y="194.4">PC13_IO 8</text>
<text x="33.8" y="193.2">PC14_IO 7</text>
<text x="170.8" y="193.2">PA9_USART1_TX</text>
<text x="185.8" y="196.3">2 USB_A_D-</text>
<text x="185.8" y="195.1">3 USB_A_D+</text>
<text x="192.9" y="193" transform="rotate(-90 192.9 193)">MCLR</text>
<text x="196.7" y="193.4" transform="rotate(-90 196.7 193.4)">PGED1</text>
<text x="197.3" y="192.5">JP5</text>
<text x="198" y="193.4" transform="rotate(-90 198 193.4)">PGEC1</text>
<text x="73" y="200.8">PB5_TIM3_CH2</text>
<text x="73" y="202.1">PB4_TIM3_CH1</text>
<text x="97.5" y="202.1">PD12_TIM4_CH1</text>
<text x="97.5" y="200.8">PD13_TIM4_CH2</text>
</g>
<text font-size=".9" fill="#000084" x="90.5" y="169.5">GND8</text>
<g font-size=".7" fill="#008484">
<text x="96.7" y="11.4">DIODE</text>
<text x="97.1" y="10.5">D24</text>
<text x="133.2" y="9.5">DIODE</text>
<text x="133.7" y="8.6">D33</text>
<text x="62.7" y="17.1">DIODE</text>
<text x="63.2" y="16.1">D16</text>
<text x="76.4" y="14.6">DIODE</text>
<text x="76.8" y="13.6">D23</text>
<text x="133.2" y="14.6">DIODE</text>
<text x="133.7" y="13.6">D34</text>
<text x="177.3" y="13.6">DIODE</text>
<text x="177.8" y="12.6">D35</text>
<text x="42.8" y="23.8">D12</text>
<text x="69.6" y="19.7">DIODE</text>
<text x="69.7" y="18.7">D20</text>
<text x="42.4" y="24.8">DIODE</text>
<text x="226.8" y="32.7">DIODE</text>
<text x="227.3" y="31.7">D56</text>
<text x="205.7" y="47.3">D47</text>
<text x="197.9" y="52.7">DIODE</text>
<text x="198" y="51.7">D39</text>
<text x="205.3" y="48.3">DIODE</text>
<text x="211.8" y="49.7">VI</text>
<text x="214.2" y="51.6" transform="rotate(-90 214.2 51.6)">GND</text>
<text x="215.1" y="49.7">VO</text>
<text x="208.7" y="62.2">DIODE</text>
<text x="209.2" y="61.2">D40</text>
<text x="260.8" y="62.8">DIODE</text>
<text x="261.3" y="61.9">D50</text>
<text x="208.7" y="81.9">DIODE</text>
<text x="209.2" y="80.9">D41</text>
<text x="260.8" y="82.5">DIODE</text>
<text x="261.3" y="81.5">D51</text>
<text x="208.7" y="103.8">DIODE</text>
<text x="209.2" y="102.8">D42</text>
<text x="260.8" y="104.4">DIODE</text>
<text x="261.3" y="103.4">D52</text>
<text x="50.6" y="117.4">DIODE</text>
<text x="51.1" y="116.5">D14</text>
<text x="208.7" y="123.5">DIODE</text>
<text x="209.2" y="122.5">D43</text>
<text x="260.8" y="124.1">DIODE</text>
<text x="261.3" y="123.1">D53</text>
<text x="55.5" y="143.2">D15</text>
<text x="55.1" y="144.2">DIODE</text>
<text x="208.7" y="145.4">DIODE</text>
<text x="209.2" y="144.4">D44</text>
<text x="260.8" y="146">DIODE</text>
<text x="261.3" y="145">D54</text>
<text x="208.7" y="165.1">DIODE</text>
<text x="209.2" y="164.1">D45</text>
<text x="260.8" y="165.7">DIODE</text>
<text x="261.3" y="164.7">D55</text>
</g>
<g font-size=".7" fill="#840000">
<text x="132.5" y="10.6">2</text>
<text x="135.7" y="10.6">1</text>
<text x="68.5" y="17.6" transform="rotate(-90 68.5 17.6)">1</text>
<text x="75.7" y="15.7">2</text>
<text x="78.9" y="15.7">1</text>
<text x="96" y="12.5">2</text>
<text x="99.2" y="12.5">1</text>
<text x="132.5" y="15.7">2</text>
<text x="135.7" y="15.7">1</text>
<text x="176.7" y="14.7">1</text>
<text x="179.8" y="14.7">2</text>
<text x="62" y="18.2">1</text>
<text x="65.2" y="18.2">2</text>
<text x="68.5" y="20.8" transform="rotate(-90 68.5 20.8)">2</text>
<text x="41.7" y="25.8">2</text>
<text x="44.9" y="25.8">1</text>
<text x="226.2" y="33.8">1</text>
<text x="229.4" y="33.8">2</text>
<text x="196.7" y="53.8" transform="rotate(-90 196.7 53.8)">2</text>
<text x="196.7" y="50.6" transform="rotate(-90 196.7 50.6)">1</text>
<text x="204.6" y="49.3">2</text>
<text x="207.8" y="49.3">1</text>
<text x="208.1" y="63.3">1</text>
<text x="211.3" y="63.3">2</text>
<text x="260.2" y="63.9">1</text>
<text x="263.3" y="63.9">2</text>
<text x="208.1" y="83">1</text>
<text x="211.3" y="83">2</text>
<text x="260.2" y="83.6">1</text>
<text x="263.3" y="83.6">2</text>
<text x="208.1" y="104.9">1</text>
<text x="211.3" y="104.9">2</text>
<text x="260.2" y="105.5">1</text>
<text x="263.3" y="105.5">2</text>
<text x="50" y="118.5">2</text>
<text x="53.1" y="118.5">1</text>
<text x="208.1" y="124.6">1</text>
<text x="211.3" y="124.6">2</text>
<text x="260.2" y="125.2">1</text>
<text x="263.3" y="125.2">2</text>
<text x="54.4" y="145.2">2</text>
<text x="57.6" y="145.2">1</text>
<text x="208.1" y="146.5">1</text>
<text x="211.3" y="146.5">2</text>
<text x="260.2" y="147.1">1</text>
<text x="263.3" y="147.1">2</text>
<text x="208.1" y="166.2">1</text>
<text x="211.3" y="166.2">2</text>
<text x="260.2" y="166.8">1</text>
<text x="263.3" y="166.8">2</text>
<text x="194.2" y="191.6" transform="rotate(-90 194.2 191.6)">2</text>
<text x="194.2" y="194.7" transform="rotate(-90 194.2 194.7)">1</text>
</g>
<g font-size=".7">
<text x="195.3" y="193.7">DIODE</text>
<text x="195.4" y="192.8">D58</text>
</g>
<g font-size=".5" fill="#008484">
<text x="68.8" y="15.7">1</text>
<text x="74.5" y="15.7">2</text>
<text x="197" y="49.3">1</text>
<text x="202.7" y="49.3">2</text>
</g>
</g></defs>
<g fill="none" stroke="#840000" stroke-width=".13">
<path d="M5 5.3h287v199.9h-287zM6 6.2h285v198h-285zM9.4 14.9h6.5l.3 .6-.3 .5h-6.5zM9.7 15.5l.3-.1v-.2l-.3-.1v.7M9.9 15.5l.2 .3M10.1 10.5h5.8l.3 .5-.3 .6h-5.8zM10.4 11h.2M10.5 19.4h5.4l.3 .5-.3 .6h-5.4zM10.7 10.7h-.3v.6h.3M11.2 19.6a.28 .28 0 0 0-.4 .3 .28 .28 0 0 0 .4 .2M16.2 11h.6M16.2 15.5h.6"/>
<path d="M16.2 19.9h.6M16.8 19.4h2.6v1h-2.6zM16.8 15h2.6v1h-2.6zM16.8 10.5h2.6v1.1h-2.6zM19.4 11h4.4M19.4 15.5h4.4M19.4 19.9h4.4M21.3 19.3l1.2 .6-1.2 .7zM21.3 14.9l1.2 .6-1.2 .6zM21.3 10.4l1.2 .6-1.2 .7zM22.5 10.4v1.3M22.5 14.9v1.2"/>
<path d="M22.5 19.3v1.3M23.6 19.2v-.4h-.4h.4l-.8 .8M23.6 14.7v-.4h-.4h.4l-.8 .8M23.6 10.3v-.4h-.4h.4l-.8 .8M24.2 19.2v-.4h-.4h.4l-.8 .8M24.2 14.7v-.4h-.4h.4l-.8 .8M24.2 10.3v-.4h-.4h.4l-.8 .8M26 9.8v1.2h.7M26 9.8l-.3 .6M26 14.2v1.3h.7M26 9.8l.4 .6M26 14.2l-.3 .7"/>
<path d="M26 14.2l.4 .7M26.7 10.5h2.5v1.1h-2.5zM26.7 15h2.5v1h-2.5zM29.2 15.5h4.5v.6h.6l-.6 .7-.7-.7h.7M29.2 11h4.5M30 5.3v.9M31.1 10.4l1.3 .6-1.3 .7zM31.1 14.9l1.3 .6-1.3 .6zM32.4 10.4v1.3M32.4 14.9v1.2M33.4 10.3v-.4h-.4h.4l-.8 .8M33.4 14.7v-.4h-.4h.4l-.8 .8"/>
<path d="M34 10.3v-.4h-.3h.3l-.7 .8M34 14.7v-.4h-.3h.3l-.7 .8M37.8 10.7v1.4M37.8 13.1v1.4M41.4 11.4h1v2.5h-1zM41.4 15.2h1v2.5h-1zM41.9 17.7v1.3h.6l-.6 .6-.6-.6h.6M41.9 10.7v.7M41.9 13.9v1.3M49.8 15.8h2.6M52.4 14.5h5.1v7.7h-5.1zM52.4 18.3h-2.6v.7h.7l-.7 .6-.6-.6h.6"/>
<path d="M53 10.7h1.4M55 5.3v.9M55.4 10.7h1.4M57.5 15.8h2.5M57.5 18.3h2.5M63.2 18.3h-1.9v1.4M63.2 17.7v1.3M66.4 17.1v1.2h-1.9M66.4 17.1l-.4 .6M66.4 17.1l.3 .6M67.9 18.3h1.3M68.6 15.8h.6a.63 .63 0 0 1 .6-.6 .63 .63 0 0 1 .7 .6 .63 .63 0 0 1 .6-.6 .63 .63 0 0 1 .7 .6 .63 .63 0 0 1 .6-.6 .63 .63 0 0 1 .6 .6 .63 .63 0 0 1 .7-.6 .63 .63 0 0 1 .6 .6h2.5"/>
<path d="M68.6 16.4v1.9M68.6 19.6v1.9M73.2 10.2h6.5l.3 .5-.3 .6h-6.5zM73.5 10.7l.4-.1v-.2h-.4v.6M73.7 10.7l.2 .3M74.9 17.1v1.4M74.9 19.5v1.4M78.1 15.8h1.9M78.1 15.2v1.2M80 5.3v.9M83.8 11.4v1.2h2.6M83.8 13.6v1.4"/>
<path d="M83.8 16v1.4M83.8 11.4l-.4 .6M83.8 11.4l.4 .6M86.4 11.4h6.3v4.4h-6.3zM89.5 15.8v3.2h.7l-.7 .6-.6-.6h.6M92.7 12.6h4.5M95.2 13.6v1.4M95.2 16v1.4M98.4 12v1.3M100.3 11.4v1.2h-1.9M100.3 11.4l-.4 .6M100.3 11.4l.4 .6"/>
<path d="M101.3 16.5h5.4l.3 .6-.3 .5h-5.4zM102 16.8a.28 .28 0 0 0-.4 .2 .28 .28 0 0 0 .4 .3M105 5.3v.9M108.3 14.5v.7h.6l-.6 .6-.7-.6h.7M109.5 14.5h1.3M109.5 17.1h1.3M110.8 14.8l2 .9M112.1 14.3v1M112.7 10.2h5.4l.3 .5-.3 .6h-5.4zM113.3 15.8h4M113.4 10.4a.28 .28 0 0 0-.4 .3 .28 .28 0 0 0 .4 .2M117.3 14.9v1.9"/>
<path d="M117.5 14.9h1.3v1.8h-.4M117.5 14.7v.5M117.5 15.6v.5M117.5 16.4v.5M117.5 16.7h.9M118.4 13.3v2.5h-.9M118.4 16.7v1.6M118.6 15.7h.4l-.2 .3zM119.1 15.9l-.5 .2M123.8 17.1l-.4 .6M123.8 17.1v1.2M123.8 17.1l.4 .6"/>
<path d="M125 10.2h6.4l.4 .5-.4 .6h-6.4zM125.3 10.7l.3-.1v-.2h-.3v.6M125.4 10.7l.2 .3M125.7 12.7h5.7l.4 .6-.4 .5h-5.7zM126 13.2h.2M126.3 12.9h-.3v.6h.3M130 5.3v.9M131.3 16.4h1v2.6h-1zM131.8 19v1.3h.6l-.6 .6-.7-.6h.7M131.8 10.7h1.9M133 13.3h2.7M133.7 15.8h-1.9v.6"/>
<path d="M134.9 10.7h1.9v2.6h-.8M134.9 10.1v1.3M134.9 15.2v1.2M135.7 12.3v1.9M136 12.4h1.2v1.8h-.4M136 14.2h.8M136 12.1v.5M136 13v.5M136 13.9v.5M136.8 14.2v1.6h-1.9M137 13.1h.4l-.2 .4zM137.5 13.4l-.5 .1"/>
<path d="M138.7 15.2h5.4v1.2h-5.4l-.3-.6zM143.4 15.5l.3 .6 .2-.6M145.3 11.8h5.8l.3 .5-.3 .6h-5.8zM145.7 12.3h.2M146 12h-.3v.6h.3M151.4 11.7l.6-.3-.6-.4-.5 .4 .5 .3v.6M151.4 12.3h.1M153.4 11v.7h.6l-.6 .6-.7-.6h.7M154 11h1.9M154 12.3h1.9M155 5.3v.9M155.9 10.4h1.3v2.5h-1.3z"/>
<path d="M155.9 12.2h.6v.2h-.6zM155.9 11h.6v.1h-.6zM171.8 13.6l-.4 .6M171.8 13.6v1.3M171.8 13.6l.3 .6M175.9 14.2l.5-.3-.5-.3-.5 .3 .5 .3v.7M175.9 14.9h.1M175.9 14.9h1.9M177.8 14.2v1.3M179.1 14.9h4.4M180 5.3v.9M180.1 15.6h.5"/>
<path d="M180.3 15.4v.5M181 17v2.3h.6l-.6 .6-.7-.6h.7M181 11h2.5M181 12.9h2.5M181 14.9v1.4M183.5 9.8h8.9v6.3h-8.9zM192.4 11h2.5M192.4 12.9h2.5M192.4 14.9h2.5M194.7 15.6h.5M194.9 15.4v.5M195.6 14.9v1.4"/>
<path d="M195.6 17v1.7M196.5 14.3h2.3v1.1h-2.3l-.3-.5zM198.3 14.7h.2M198.4 14.5v.5l.1 .1M200 19.7l.2-.4h1l-.2 .4M200.4 19.3l-.1 .4M200.7 18.7v.6l-.2 .4M200.9 19.3l-.1 .4M203.8 8.8l-.3 .7M203.8 8.8v1.3M203.8 8.8l.4 .7M204.5 12.6h3.8v5.1h-3.8z"/>
<path d="M205 5.3v.9M205.7 10.1v2.5M205.7 17.7v2.6M207 10.1v2.5M207 17.7v2.6M209.5 9.5l.6-.4-.6-.3-.5 .3 .5 .4v.6M209.5 10.1h.1M211.8 19.7h5.9v1.1h-5.9l-.3-.5zM217.8 9.5l-.4 .6M217.8 9.5v1.2M217.8 9.5l.4 .6M218.8 10.7h1.9"/>
<path d="M221.9 10.7h1.9M222.2 9.5v2.5M223.8 14.5h1.3M226.4 13v1M227.6 15.8h1.3M227.6 13.3h1.3M227.6 13.5l-2 .9M229 16.4h1.1v2.6h-1.1zM229.6 19v1.3l-.2 .3M229.6 15.8v.6M230 5.3v.9M230.2 13.3h2.7"/>
<path d="M232.4 17.7l.5-.3-.5-.3-.5 .3 .5 .3v.6M232.4 18.3h.1M232.9 12.3v1.9M233.1 12.4h1.3v1.8h-.4M233.1 12.1v.5M233.1 13v.5M233.1 13.9v.5M233.1 14.2h.9M234 10.7v2.6h-.9M234 14.2v1.6M234.2 13.1h.4l-.2 .4zM234.3 17.8h2.2v1.1h-2.2l-.3-.6z"/>
<path d="M234.6 13.4l-.5 .1M236.1 18.2h.2M236.1 18v.5l.2 .1M249.9 10.4v1.4M249.9 12.8v1.4M249.9 16.1v1.4M249.9 18.5v1.4M253.7 12.9h1.9M253.7 11.7h1.9M253.7 17.4h1.9M253.7 18.7h1.9M255 5.3v.9"/>
<path d="M255.6 11h1.3v2.6h-1.3zM255.6 12.9h.6v.1h-.6zM255.6 11.6h.6v.1h-.6zM255.6 16.8h1.3v2.5h-1.3zM255.6 18.6h.6v.1h-.6zM255.6 17.3h.6v.2h-.6zM263.2 10.4l-.4 .6M263.2 10.4v1.3M263.2 16.1v1.3M263.2 10.4l.4 .6M263.2 16.1l-.4 .7M263.2 16.1l.4 .7"/>
<path d="M264.5 12.7l.1-.4h1l-.1 .4M264.5 18.4l.1-.4h1l-.1 .4M264.9 12.3l-.2 .4M264.9 18l-.2 .4M265.1 12.9h1.9M265.1 18.7h1.9M265.4 12.3l-.2 .4M265.4 18l-.2 .4M267 11h1.3v2.6h-1.3zM267 12.9h.7v.1h-.7zM267 11.6h.7v.1h-.7zM267 16.8h1.3v2.5h-1.3z"/>
<path d="M267 18.6h.7v.1h-.7zM267 17.3h.7v.2h-.7zM267 11.7h-1.9v.6l-.1 .4M267 17.4h-1.9v.6l-.1 .4M268.3 6h.3M280 5.3v.9M5 30.2h1M11.1 39v1.4M11.4 39h1M14.3 39h.9M15.6 39v1.4M16.2 23.1v1.3h.6"/>
<path d="M16.2 23.1l-.4 .6M16.2 23.1l.4 .6M16.8 23.9h2.6v1h-2.6zM19.4 24.4h4.4v.6h.6l-.6 .6-.6-.6h.6M21.3 23.7l1.2 .7-1.2 .6zM22.5 23.7v1.3M23.5 38.8h2.5v1h-2.5zM23.5 39.3h-.6v.6h.6l-.6 .7-.7-.7h.7M23.6 23.6v-.4h-.4h.4l-.8 .8M24.2 23.6v-.4h-.4h.4l-.8 .8M26 39.3h4.5M28.6 24.1h1.2v6.3h-1.2z"/>
<path d="M29.2 29.7h.6v.1h-.6zM29.2 28.4h.6v.2h-.6zM29.2 25.9h.6v.1h-.6zM29.2 24.6h.6v.2h-.6zM29.2 27.2h.6v.1h-.6zM29.8 24.7h1.9M29.8 26h1.9M29.8 27.2h1.9M29.8 28.5h1.9M29.8 29.8h1.9M30.5 37.4h119.4v68.6h-119.4zM32.7 24.7v.6h.6l-.6 .7-.6-.7h.6"/>
<path d="M33.3 26h2.1M35.9 25.3a1.58 1.58 0 0 1 2.5 0M38.9 26h4M44.1 25.3v1.3M46 24.7v1.3h-1.9M46 24.7l-.3 .6M46 24.7l.4 .6M49.8 20.9h2.6M57.5 20.9h2.5M61.3 20.8v1.4M61.6 32.3v5.1M61.6 32.3l-.4 .7"/>
<path d="M61.6 32.3l.4 .7M67.9 33.6v3.8M74.9 22.2v.6h.7l-.7 .6-.6-.6h.6M80.6 33.6v3.8M84.5 33.6v3.8M88.3 33.6v3.8M92.1 33.6v3.8M95.9 33.6v3.8M99.7 33.6v3.8M106 33.6v3.8M110.5 25v2.7M110.5 28.7v1.4"/>
<path d="M110.5 25l-.4 .6M110.5 25l.4 .6M114.9 26.3v1.4M114.9 28.7v1.4M119.4 26.3v1.4M119.4 28.7v1.4M123.8 26.3v1.4M123.8 28.7v1.4M128.3 26.3v1.4M128.3 28.7v1.4M132.7 26.3v1.4M132.7 28.7v1.4"/>
<path d="M137.2 26.3v1.4M137.2 28.7v1.4M141.6 26.3v1.4M141.6 28.7v1.4M146 28.7v2h.7l-.7 .7-.6-.7h.6M146 26.3v1.4M149.9 39.3h3.8M183.9 29.2h6l.3 .6-.3 .5h-6zM184 38.1h5.9l.3 .6-.3 .5h-5.9zM187.6 33.7h2.3l.3 .5-.3 .6h-2.3zM190.2 38.7h.6M190.2 24.1v1.2h.6"/>
<path d="M190.2 24.1l-.4 .6M190.2 24.1l.4 .6M190.2 34.2h.6M190.8 38.2h2.6v1h-2.6zM190.8 24.8h2.6v1h-2.6zM190.8 33.7h2.6v1h-2.6zM193.4 38.7h4.4v.6l-.1 .4M193.4 25.3h4.4M193.4 34.2h4.4M195.3 38l1.2 .7-1.2 .6zM195.3 24.7l1.2 .6-1.2 .7zM195.3 33.6l1.2 .6-1.2 .7z"/>
<path d="M196.5 24.7v1.3M196.5 33.6v1.3M196.5 38v1.3M197.2 39.7l.1-.4h1l-.1 .4M197.5 37.9v-.4h-.3h.3l-.7 .8M197.5 39.3l-.1 .4M197.5 24.6v-.4h-.3h.3l-.7 .7M197.5 33.5v-.4h-.3h.3l-.7 .7M198.1 39.3l-.2 .4M198.2 37.9v-.4h-.4h.4l-.8 .8M198.2 24.6v-.4h-.4h.4l-.8 .7M198.2 33.5v-.4h-.4h.4l-.8 .7"/>
<path d="M200.7 28.5v1.3h.6M200.7 28.5l-.4 .6M200.7 24.1v1.2h.6M200.7 28.5l.3 .6M200.7 24.1l-.4 .6M200.7 24.1l.3 .6M201.3 29.3h2.5v1h-2.5zM201.3 24.8h2.5v1h-2.5zM203.8 29.8h4.5v.6l-.1 .4M203.8 25.3h4.5M205.7 29.1l1.3 .7-1.3 .6zM205.7 24.7l1.3 .6-1.3 .7z"/>
<path d="M207 24.7v1.3M207 29.1v1.3M207.6 30.8l.2-.4h1l-.1 .4M208 29v-.4h-.4h.4l-.7 .8M208 30.4l-.1 .4M208 24.6v-.4h-.4h.4l-.7 .7M208.5 30.4l-.1 .4M208.7 29v-.4h-.4h.4l-.8 .8M208.7 24.6v-.4h-.4h.4l-.8 .7M216.9 24.8h6l.3 .5-.3 .6h-6zM218.4 28.2h1.3v2.5h-1.3zM219.1 30h.6v.2h-.6z"/>
<path d="M219.1 28.8h.6v.1h-.6zM219.7 30.1h1.9M221.6 27.6v1.2h-1.9M221.6 27.6l-.4 .6M221.6 27.6l.4 .6M223.2 30.1h4.4M223.8 38h1.3M225.1 38.3l2 .9M225.4 33.9h1.9M225.7 25h5.1v6.4h-5.1zM226.4 37.8v1M227.3 33.3v1.2"/>
<path d="M227.6 28.8h1.3v1.9h-1.3zM227.6 39.3h1.3M228.6 33.9h1.9M228.7 39.9h1v2.6h-1zM228.9 20.6l.1-.3h1.1l-.2 .3M228.9 30.1h4.5M228.9 28.8l-1.3 1.9M229.2 39.3v.6M229.3 20.3l-.1 .3M229.6 26.9v.7h3.8M229.6 39.3h2.6M229.6 25.6l-2 .7h-4.4"/>
<path d="M229.8 20.3l-.1 .3M230.8 26.3h2.6M232.2 38.3v2M232.5 39.3h.9v2.5M232.5 38.2v.5M232.5 39v.6M232.5 39.9v.5M232.5 38.4h.9M233.4 38.4h.3v1.8h-1.2M233.4 36.8v1.6M233.5 39l.5 .2M233.7 27h5.9v1.1h-5.9l-.3-.5z"/>
<path d="M233.7 39.1l.2 .3h-.3zM238.4 36.5a1.58 1.58 0 0 0 0 2.5M239.1 33.9v2.1M239.1 39.4v2.1M249.9 21.8v1.4M249.9 24.3v1.3M249.9 27.6v1.4M249.9 30v1.4M249.9 33.3v1.4M249.9 35.7v1.4M249.9 39v1.4M253.7 28.8h1.9"/>
<path d="M253.7 30.1h1.9M253.7 24.4h1.9M253.7 34.5h1.9M253.7 35.8h1.9M253.7 23.1h1.9M255.6 33.9h1.3v2.5h-1.3zM255.6 35.7h.6v.2h-.6zM255.6 34.5h.6v.1h-.6zM255.6 39.6h1.3v2.6h-1.3zM255.6 22.5h1.3v2.5h-1.3zM255.6 24.3h.6v.1h-.6zM255.6 23h.6v.2h-.6z"/>
<path d="M255.6 28.2h1.3v2.5h-1.3zM255.6 30h.6v.2h-.6zM255.6 28.8h.6v.1h-.6zM276.9 33.6h6.3v6.3h-6.3zM276.9 26h6.3v6.3h-6.3zM291 30.2h1M5 55.3h1M10.8 50.1h1.3M11.1 41.4v1.4M11.4 53.9h1.4M12.1 49.5h2.5M13.3 42.8v.6h.7l-.7 .7-.6-.7h.6"/>
<path d="M13.3 48.6v.9M13.8 53.9h1.4M14.6 50.1h1.3M15.6 41.4v1.4M15.9 53.9v.6h.6l-.6 .7-.7-.7h.7M26.7 41.8h3.8M26.7 44.4h3.8M26.7 52h3.8M149.9 49.5h3.8M149.9 41.8h3.8M149.9 44.4h3.8M149.9 52h3.8"/>
<path d="M149.9 43.1h3.8M149.9 48.2h3.8M149.9 45.7h3.8M149.9 50.7h3.8M149.9 53.3h3.8M149.9 54.5h3.8M149.9 55.8h3.8M149.9 57.1h3.8M149.9 58.4h3.8M149.9 46.9h3.8M149.9 40.6h3.8M167.6 56.8l.2-.4h1l-.1 .4"/>
<path d="M167.8 52.6h1v2.6h-1zM168 56.4l-.1 .4M168.3 55.2v1.2l-.2 .4M168.3 52v.6M168.5 56.4l-.1 .4M171.3 52.6h1v2.6h-1zM171.8 52v.6M171.8 55.2v.6M175.3 51.7l.1-.3h1l-.1 .3M175.6 51.4l-.1 .3M175.9 49.5h2.5M175.9 54.4v1.4"/>
<path d="M176.1 51.4l-.1 .3M178.4 48.2h5.1v5.1h-5.1zM178.4 50.7h-2.5v.7l-.1 .3M178.4 52h-2.5v1.4M179.1 44.1h1.4M181.5 44.1h1.4M183.5 49.5h2.6M183.5 52h2.6M183.5 50.7h2.6M187.3 50.7v1.4M187.3 53.1v1.4M191.2 51.5h.5"/>
<path d="M191.5 51.2v.5M192.1 50.7v1.4M192.1 52.9v1.6M192.4 58.4v2.6M192.4 58.4l-.4 .6M192.4 58.4l.4 .6M192.7 50.2h2.2v1.1h-2.2l-.3-.6zM194.5 50.6h.2M194.6 50.4v.5l.1 .1M196.2 51.4h1.3M196.8 52.6v1.9M203.2 49.5h-.6a.63 .63 0 0 0-.7-.7 .63 .63 0 0 0-.6 .7 .63 .63 0 0 0-.6-.7 .63 .63 0 0 0-.7 .7 .63 .63 0 0 0-.6-.7 .63 .63 0 0 0-.6 .7 .63 .63 0 0 0-.7-.7 .63 .63 0 0 0-.6 .7h-.7v1.9"/>
<path d="M203.5 50.1v1.4M203.5 52.5v1.4M203.8 49.5h1.9M207 49.5h4.5M207 48.8v1.3M208.9 48.2v2.7M208.9 51.9v1.4M208.9 48.2l-.4 .6M208.9 48.2l.4 .6M211.5 48.2h5v3.8h-5zM213.4 55.6l.1-.4h1l-.1 .4M213.7 55.2l-.1 .4"/>
<path d="M214 54.5v.7l-.1 .4M214 52v1.3M214.2 55.2l-.1 .4M216.5 49.5h2.6M219.1 48.2v2.7M219.1 51.9v1.4M219.1 48.2l-.4 .6M219.1 48.2l.4 .6M223.8 40.6h1.3M229.2 42.5v.6M238.4 44.1l.2-.4h1l-.1 .4M238.8 43.7l-.1 .4"/>
<path d="M239.1 43.1v.6l-.1 .4M239.3 43.7l-.1 .4M244.5 59v2.7M244.5 59l-.4 .6M244.5 59l.4 .6M244.9 50.5h5.9l.3 .5-.3 .6h-5.9zM249.9 41.4v1.4M251.2 51.8h.5M251.5 51.6v.5M252.1 51v1.4M252.1 53.2v1.7M253.7 40.3h1.9"/>
<path d="M253.7 41.5h1.9M255.6 41.5h.6v.1h-.6zM255.6 40.2h.6v.1h-.6zM256.3 51.8h.5M256.5 51.6v.5M257.2 51v1.4M257.2 53.2v1.7M262.3 51v1.4M262.3 53.5v1.4M266.4 55.9l.1-.4h1l-.1 .4M266.8 55.5l-.2 .4M267 53.5v2l-.1 .4"/>
<path d="M267 51v1.4M267.3 55.5l-.2 .4M276.9 41.2h6.3v6.4h-6.3zM291 55.3h1M26.7 62.2h3.8M26.7 63.4h3.8M26.7 64.7h3.8M26.7 66h3.8M26.7 67.2h3.8M26.7 68.5h3.8M26.7 69.8h3.8M26.7 71.1h3.8"/>
<path d="M26.7 72.3h3.8M26.7 73.6h3.8M26.7 74.9h3.8M26.7 76.1h3.8M26.7 77.4h3.8M26.7 78.7h3.8M26.7 79.9h3.8M149.9 62.2h3.8M149.9 63.4h3.8M149.9 64.7h3.8M149.9 66h3.8M149.9 67.2h3.8"/>
<path d="M149.9 68.5h3.8M149.9 69.8h3.8M149.9 71.1h3.8M149.9 72.3h3.8M149.9 73.6h3.8M149.9 74.9h3.8M149.9 76.1h3.8M149.9 77.4h3.8M149.9 78.7h3.8M149.9 79.9h3.8M185.9 68.8h1v2.6h-1zM186.4 65.7v1.2"/>
<path d="M186.4 68.2v.6M186.4 71.4v.6M186.4 65.7l-.4 .6M186.4 65.7l.4 .6M191.8 64.4l.1-.3h1l-.1 .3M192.2 64.1l-.2 .3M192.4 62v2.1l-.1 .3M192.4 78v2.7M192.4 78l-.4 .7M192.4 78l.4 .7M192.7 64.1l-.2 .3M193.7 76.8l.1-.4h1l-.1 .4"/>
<path d="M194.1 76.4l-.2 .4M194.3 75.8v.6l-.1 .4M194.3 74.5h1.3M194.3 69.5h1.3M194.3 72h1.3M194.3 66.9h1.3M194.6 76.4l-.2 .4M195.6 65.7h8.9v10.1h-8.9zM204.5 74.5h1.2M204.5 69.5h1.2M204.5 72h1.2M204.5 66.9h1.2"/>
<path d="M207.3 67.6v1.4M207.3 70v1.4M207.3 63.4h1.9M208.6 74.5h.6M208.6 69.5h.6M209.2 69h2.6v1h-2.6zM209.2 74h2.6v1.1h-2.6zM209.2 62.8v1.3M211.8 74.5h.6M211.8 69.5h.6M212.4 62.2l-.4 .6M212.4 62.2v1.2h-1.9"/>
<path d="M212.4 62.2l.4 .6M215.3 71.1l.1-.4h1l-.1 .4M215.6 70.7l-.1 .4M215.9 67.6h2.5M215.9 72.6h2.5M215.9 73.9h2.5M215.9 68.8h2.5M215.9 71.4h2.5M216.2 70.7l-.2 .4M218.4 65h8.9v11.4h-8.9zM218.4 70.1h-2.5v.6l-.1 .4M227.3 67.6h2.6"/>
<path d="M227.3 70.1h2.6M227.3 72.6h2.6M227.3 75.2h2.6M227.3 73.9h2.6M227.3 68.8h2.6M227.3 71.4h2.6M227.3 66.3h2.6M230.2 65.7h5.9v1.1h-5.9l-.3-.5zM237.9 69.5h1.1v2.5h-1.1zM238.4 66.3v1.3M238.4 68.8v.7M238.4 72v.6"/>
<path d="M238.4 66.3l-.3 .6M238.4 66.3l.4 .6M243.8 65.1l.2-.4h1l-.1 .4M244.2 64.7l-.1 .4M244.5 62.7v2l-.2 .4M244.5 78.7v2.6M244.5 78.7l-.4 .6M244.5 78.7l.4 .6M244.7 64.7l-.1 .4M245.7 77.5l.2-.4h1l-.1 .4M246.1 77.1l-.1 .4M246.4 76.4v.7l-.1 .4"/>
<path d="M246.4 67.6h1.2M246.4 70.1h1.2M246.4 72.6h1.2M246.4 75.2h1.2M246.6 77.1l-.1 .4M247.6 66.3h8.9v10.1h-8.9zM256.5 67.6h1.3M256.5 70.1h1.3M256.5 72.6h1.3M256.5 75.2h1.3M259.4 64.1h1.9M259.4 68.2v1.4"/>
<path d="M259.4 70.6v1.4M260.7 70.1h.6M260.7 75.2h.6M261.3 69.6h2.5v1h-2.5zM261.3 74.7h2.5v1h-2.5zM261.3 63.4v1.3M263.8 70.1h.7M263.8 75.2h.7M264.5 62.8v1.3h-1.9M264.5 62.8l-.4 .6M264.5 62.8l.4 .6M267.3 71.7l.2-.3h1l-.1 .3"/>
<path d="M267.7 71.4l-.1 .3M268 68.2h2.5M268 73.3h2.5M268 74.5h2.5M268 69.5h2.5M268 72h2.5M268.2 71.4l-.1 .3M270.5 65.7h8.9v11.4h-8.9zM270.5 70.7h-2.5v.7l-.2 .3M279.4 68.2h2.5M279.4 70.7h2.5M279.4 73.3h2.5"/>
<path d="M279.4 74.5h2.5M279.4 69.5h2.5M279.4 72h2.5M279.4 66.9h2.5M279.4 75.8h2.5M282.3 66.4h5.8v1.1h-5.8l-.4-.6zM5 80.2h1M26.7 85h3.8M26.7 86.3h3.8M26.7 87.6h3.8M26.7 88.8h3.8M26.7 90.1h3.8"/>
<path d="M26.7 91.4h3.8M26.7 97.7h3.8M26.7 99h3.8M26.7 81.2h3.8M26.7 92.6h3.8M26.7 93.9h3.8M26.7 95.2h3.8M26.7 96.5h3.8M149.9 85h3.8M149.9 86.3h3.8M149.9 87.6h3.8M149.9 88.8h3.8"/>
<path d="M149.9 90.1h3.8M149.9 91.4h3.8M149.9 97.7h3.8M149.9 99h3.8M149.9 81.2h3.8M149.9 92.6h3.8M149.9 93.9h3.8M149.9 95.2h3.8M149.9 96.5h3.8M185.5 88.5h1.1v2.6h-1.1zM186.1 85.3v1.3M186.1 87.9v.6"/>
<path d="M186.1 91.1v.6M186.1 85.3l-.4 .7M186.1 85.3l.3 .7M191.8 84.1l.1-.3h1l-.1 .3M192.2 83.8l-.2 .3M192.4 81.7v2.1l-.1 .3M192.4 99.9v2.7M192.4 99.9l-.4 .7M192.4 99.9l.4 .7M192.7 83.8l-.2 .3M193.7 96.5l.1-.4h1l-.1 .4M194.1 96.1l-.2 .4"/>
<path d="M194.3 95.5v.6l-.1 .4M194.3 94.2h1.3M194.3 89.1h1.3M194.3 91.7h1.3M194.3 86.6h1.3M194.6 96.1l-.2 .4M195.6 85.3h8.9v10.2h-8.9zM204.5 94.2h1.2M204.5 89.1h1.2M204.5 91.7h1.2M204.5 86.6h1.2M207.3 87.2v1.4"/>
<path d="M207.3 89.7v1.4M207.3 83.1h1.9M208.6 94.2h.6M208.6 89.1h.6M209.2 88.6h2.6v1.1h-2.6zM209.2 93.7h2.6v1h-2.6zM209.2 82.5v1.3M211.8 94.2h.6M211.8 89.1h.6M212.4 81.8v1.3h-1.9M212.4 81.8l-.4 .7M212.4 81.8l.4 .7"/>
<path d="M215.3 90.8l.1-.4h1l-.1 .4M215.6 90.4l-.1 .4M215.9 87.2h2.5M215.9 92.3h2.5M215.9 93.6h2.5M215.9 88.5h2.5M215.9 91.1h2.5M216.2 90.4l-.2 .4M218.4 84.7h8.9v11.4h-8.9zM218.4 89.8h-2.5v.6l-.1 .4M227.3 87.2h2.6M227.3 89.8h2.6"/>
<path d="M227.3 92.3h2.6M227.3 94.9h2.6M227.3 93.6h2.6M227.3 88.5h2.6M227.3 91.1h2.6M227.3 86h2.6M230.2 85.4h5.9v1.1h-5.9l-.3-.5zM237.6 89.1h1v2.6h-1zM238.1 86v1.2M238.1 88.5v.6M238.1 91.7v.6M238.1 86l-.4 .6"/>
<path d="M238.1 86l.4 .6M243.8 84.8l.2-.4h1l-.1 .4M244.2 84.4l-.1 .4M244.5 82.4v2l-.2 .4M244.7 84.4l-.1 .4M245.7 97.1l.2-.3h1l-.1 .3M246.1 96.8l-.1 .3M246.4 96.1v.7l-.1 .3M246.4 87.2h1.2M246.4 89.8h1.2M246.4 92.3h1.2M246.4 94.9h1.2"/>
<path d="M246.6 96.8l-.1 .3M247.6 86h8.9v10.1h-8.9zM256.5 87.2h1.3M256.5 89.8h1.3M256.5 92.3h1.3M256.5 94.9h1.3M259.4 87.9v1.4M259.4 90.3v1.4M259.4 83.8h1.9M260.7 89.8h.6M260.7 94.9h.6M261.3 89.3h2.5v1h-2.5z"/>
<path d="M261.3 94.4h2.5v1h-2.5zM261.3 83.1v1.3M263.8 89.8h.7M263.8 94.9h.7M264.5 82.5v1.3h-1.9M264.5 82.5l-.4 .6M264.5 82.5l.4 .6M267.3 91.4l.2-.3h1l-.1 .3M267.7 91.1l-.1 .3M268 87.9h2.5M268 93h2.5M268 94.2h2.5"/>
<path d="M268 89.1h2.5M268 91.7h2.5M268.2 91.1l-.1 .3M270.5 85.3h8.9v11.5h-8.9zM270.5 90.4h-2.5v.7l-.2 .3M279.4 87.9h2.5M279.4 90.4h2.5M279.4 93h2.5M279.4 94.2h2.5M279.4 89.1h2.5M279.4 91.7h2.5M279.4 86.6h2.5"/>
<path d="M279.4 95.5h2.5M282.3 86h5.8v1.2h-5.8l-.4-.6zM291 80.2h1M5 105.3h1M10.8 117.7l-.4 .7M10.8 117.7v1.3M10.8 117.7l.4 .7M21.3 117.7l-.4 .7M21.3 117.7v1.3M21.3 117.7l.4 .7M26.7 100.3h3.8M26.7 101.5h3.8"/>
<path d="M26.7 102.8h3.8M26.7 104.1h3.8M49.2 118.7h1.9M52.4 118.7h1.9M52.4 118v1.3M54.6 117.4l-.4 .6M54.6 117.4v1.3M54.6 117.4l.4 .6M54.9 118.7h1.3M56.2 118h1.8v2.6h-1.8zM56.2 119.9h-1.3v.7M58 118l1.2-1.2v5.1l-1.2-1.3"/>
<path d="M70.5 119l-.4 .6M70.5 119v1.3M70.5 119l.4 .6M81.6 119h2.5M84.1 117.7h6.4v12.7h-6.4zM85.1 106v3.8M87.6 106v3.8M90.2 106v3.8M92.7 106v3.8M95.2 106v3.8M101.6 106v5.2M101.6 112.2v1.4"/>
<path d="M107.9 112.2v2h.7l-.7 .7-.6-.7h.6M107.9 106v5.2M130.9 116.8h1.1v2.5h-1.1zM131.4 114.9v1.9M131.4 119.3v.6M131.4 114.9l-.3 .6M131.4 114.9l.4 .6M136 116.8h1v2.5h-1zM136.5 114.9v1.9M136.5 119.3v.6M136.5 114.9l-.4 .6M136.5 114.9l.4 .6"/>
<path d="M141.7 116.8h1v2.5h-1zM142.2 114.9v1.9M142.2 119.3v.6M142.2 114.9l-.3 .6M142.2 114.9l.4 .6M147.4 116.8h1.1v2.5h-1.1zM148 114.9v1.9M148 119.3v.6M148 114.9l-.4 .6M148 114.9l.3 .6M149.9 100.3h3.8M149.9 101.5h3.8"/>
<path d="M149.9 102.8h3.8M149.9 104.1h3.8M160.7 112.2v2h.6l-.6 .7-.7-.7h.7M160.7 108.5v2.7M160.7 108.5l-.4 .7M160.7 108.5l.3 .7M162.2 114.2v1.3h2.6M162.2 114.2l-.3 .7M162.2 114.2l.4 .7M162.2 117.4h2.6M162.2 119.3h2.6M164.8 114.2h7.6v15.9h-7.6z"/>
<path d="M172.4 117.4h2.5M172.4 119.3h2.5M174.9 114.2v1.3h-2.5M174.9 114.2l-.3 .7M174.9 114.2l.4 .7M176.5 114.6l.2-.4h1l-.2 .4M176.9 114.2l-.1 .4M177.2 112.2v2l-.2 .4M177.2 108.5v2.7M177.2 108.5l-.4 .7M177.2 108.5l.3 .7M177.4 114.2l-.1 .4"/>
<path d="M185.9 110.4h1v2.6h-1zM186.4 107.2v1.3M186.4 109.8v.6M186.4 113v.6M186.4 107.2l-.4 .7M186.4 107.2l.4 .7M191.8 106l.1-.3h1l-.1 .3M192.2 105.7l-.2 .3M192.4 103.6v2.1l-.1 .3M192.4 119.6v2.7M192.4 119.6l-.4 .7M192.4 119.6l.4 .7"/>
<path d="M192.7 105.7l-.2 .3M193.7 118.4l.1-.4h1l-.1 .4M194.1 118l-.2 .4M194.3 117.4v.6l-.1 .4M194.3 108.5h1.3M194.3 111.1h1.3M194.3 113.6h1.3M194.3 116.1h1.3M194.6 118l-.2 .4M195.6 107.2h8.9v10.2h-8.9zM204.5 108.5h1.2M204.5 111.1h1.2"/>
<path d="M204.5 113.6h1.2M204.5 116.1h1.2M207.3 109.2v1.3M207.3 111.6v1.4M207.3 105h1.9M208.6 111.1h.6M208.6 116.1h.6M209.2 110.5h2.6v1.1h-2.6zM209.2 115.6h2.6v1h-2.6zM209.2 104.4v1.3M211.8 111.1h.6M211.8 116.1h.6"/>
<path d="M212.4 103.8v1.2h-1.9M212.4 103.8l-.4 .6M212.4 103.8l.4 .6M215.3 112.7l.1-.4h1l-.1 .4M215.6 112.3l-.1 .4M215.9 109.2h2.5M215.9 114.2h2.5M215.9 115.5h2.5M215.9 110.4h2.5M215.9 113h2.5M216.2 112.3l-.2 .4M218.4 106.6h8.9v11.4h-8.9z"/>
<path d="M218.4 111.7h-2.5v.6l-.1 .4M227.3 109.2h2.6M227.3 111.7h2.6M227.3 114.2h2.6M227.3 116.8h2.6M227.3 115.5h2.6M227.3 110.4h2.6M227.3 113h2.6M227.3 107.9h2.6M230.2 107.3h5.9v1.1h-5.9l-.3-.5zM237.9 111.1h1.1v2.5h-1.1zM238.4 107.9v1.3"/>
<path d="M238.4 110.4v.7M238.4 113.6v.6M238.4 107.9l-.3 .6M238.4 107.9l.4 .6M243.8 106.7l.2-.4h1l-.1 .4M244.2 106.3l-.1 .4M244.5 104.3v2l-.2 .4M244.5 100.6v2.6M244.5 100.6l-.4 .6M244.5 100.6l.4 .6M244.7 106.3l-.1 .4M245.7 119.1l.2-.4h1l-.1 .4"/>
<path d="M246.1 118.7l-.1 .4M246.4 118v.7l-.1 .4M246.4 109.2h1.2M246.4 111.7h1.2M246.4 114.2h1.2M246.4 116.8h1.2M246.6 118.7l-.1 .4M247.6 107.9h8.9v10.1h-8.9zM256.5 109.2h1.3M256.5 111.7h1.3M256.5 114.2h1.3M256.5 116.8h1.3"/>
<path d="M259.4 109.8v1.4M259.4 112.2v1.4M259.4 105.7h1.9M260.7 111.7h.6M260.7 116.8h.6M261.3 111.2h2.5v1h-2.5zM261.3 116.3h2.5v1h-2.5zM261.3 105v1.3M263.8 111.7h.7M263.8 116.8h.7M264.5 104.4v1.3h-1.9M264.5 104.4l-.4 .6"/>
<path d="M264.5 104.4l.4 .6M267.3 113.3l.2-.3h1l-.1 .3M267.7 113l-.1 .3M268 111.1h2.5M268 113.6h2.5M268 116.1h2.5M268 109.8h2.5M268 114.9h2.5M268.2 113l-.1 .3M270.5 107.2h8.9v11.5h-8.9zM270.5 112.3h-2.5v.7l-.2 .3M279.4 108.5h2.5"/>
<path d="M279.4 111.1h2.5M279.4 113.6h2.5M279.4 116.1h2.5M279.4 109.8h2.5M279.4 112.3h2.5M279.4 114.9h2.5M279.4 117.4h2.5M282.3 108h5.8v1.1h-5.8l-.4-.6zM291 105.3h1M5 130.2h1M10.8 131.9v2h.6l-.6 .7-.6-.7h.6M10.8 128.2v2.7"/>
<path d="M10.8 121.2h1.4M10.8 128.2l-.4 .6M10.8 128.2l.4 .6M13 136.8h1.3M13 138h1.3M13.2 121.2h1.4M14.3 135.5h10.1v7.6h-10.1zM14.9 121.2v.7h.7l-.7 .6-.6-.6h.6M15.2 121.2h1.9M15.2 122.5h1.9M15.2 123.8h1.9M15.2 125h1.9"/>
<path d="M17.1 120.6h1.3v5.1h-1.3zM17.1 125h.7v.1h-.7zM17.1 123.7h.7v.1h-.7zM17.1 121.2h.7v.1h-.7zM17.1 122.4h.7v.1h-.7zM19.4 133v2.5M21.3 121.2h1.4M23.7 121.2h1.4M24.4 138h1.3M24.8 130.7h2.1M25.4 121.2v.7h.6l-.6 .6-.6-.6h.6M25.7 121.2h1.9"/>
<path d="M25.7 122.5h1.9M25.7 123.8h1.9M25.7 125h1.9M27.3 130.1a1.58 1.58 0 0 1 2.5 0M27.6 120.6h1.3v5.1h-1.3zM27.6 125h.7v.1h-.7zM27.6 123.7h.7v.1h-.7zM27.6 121.2h.7v.1h-.7zM27.6 122.4h.7v.1h-.7zM30.3 130.7h2.7M33 130.2h2.6v1h-2.6zM35.6 130.7h.6"/>
<path d="M51.1 126.3h2.9M54 126.6l.9 1v1.9h.7l-.7 .6-.6-.6h.6M54.4 120.6h1v2.5h-1zM54.9 123.1v1.9l-.9 1M70 123.4h1v2.6h-1zM70.5 122.8v.6M70.5 126v.6M71.1 139.5v2h.7l-.7 .7-.6-.7h.6M71.1 135.8v2.7M71.1 135.8l-.4 .7M71.1 135.8l.4 .7M73.2 124.7h1v2.5h-1z"/>
<path d="M73.7 124.1v.6M73.7 127.2v.7M77.2 125.3h1.3M77.8 120.3h1.4M77.8 121.5h1.4M79.6 125.3h1.4M80.2 120.3h3.9M80.2 121.5h3.9M81.3 125.3v.7h.6l-.6 .6-.7-.6h.7M81.6 125.3h2.5M81.6 122.8h2.5M81.6 124.1h2.5"/>
<path d="M81.6 126.6h2.5M81.6 127.9h2.5M81.6 129.2h2.5M101.3 121.5h.6M101.3 122.8h.6M101.3 124.1h.6M101.9 121h2.6v1h-2.6zM101.9 123.6h2.6v1h-2.6zM101.9 122.3h2.6v1h-2.6zM104.5 121.5h3.1M104.5 122.8h3.1M104.5 124.1h3.1"/>
<path d="M107.6 120.9h8.9v3.8h-8.9zM116.5 124.1h2.6v.6h.6l-.6 .6-.7-.6h.7M116.5 121.5h2.6M116.5 122.8h2.6M119.4 137.1h1.2l-.6 1.3zM119.4 138.4h1.2M119.5 132.6h1v2.6h-1zM120 135.2v5.1h.6l-.6 .6-.6-.6h.6M120 132v.6M120.4 139.2l.8 .8v-.4v.4h-.4M120.4 138.6l.8 .8v-.4v.4h-.4M125.1 137.1h1.3l-.7 1.3z"/>
<path d="M125.1 138.4h1.3M125.2 132.6h1v2.6h-1zM125.7 135.2v5.1h.7l-.7 .6-.6-.6h.6M125.7 132v.6M126.1 139.2l.8 .8v-.4v.4h-.4M126.1 138.6l.8 .8v-.4v.4h-.4M129.9 123.1h.9M130.8 137.1h1.3l-.7 1.3zM130.8 138.4h1.3M130.8 121.9v2.5M130.9 132.6h1.1v2.6h-1.1zM131.4 135.2v5.1h.7l-.7 .6-.6-.6h.6"/>
<path d="M131.4 124.4v1.9h.7l-.7 .6-.6-.6h.6M131.4 120.6v1.3M131.4 132v.6M131.8 139.2l.8 .8v-.4v.4h-.4M131.8 138.6l.8 .8v-.4v.4h-.4M135 123.1h.9M135.9 121.9v2.5M136.5 137.1h1.3l-.6 1.3zM136.5 124.4v1.9h.7l-.7 .6-.6-.6h.6M136.5 138.4h1.3M136.5 120.6v1.3M136.7 132.6h1v2.6h-1z"/>
<path d="M137.2 135.2v5.1h.6l-.6 .6-.7-.6h.7M137.2 132v.6M137.5 139.2l.8 .8v-.4v.4h-.4M137.5 138.6l.8 .8v-.4v.4h-.4M140.7 123.1h.9M141.6 121.9v2.5M142.2 137.1h1.3l-.6 1.3zM142.2 124.4v1.9h.7l-.7 .6-.6-.6h.6M142.2 120.6v1.3M142.2 138.4h1.3M142.4 132.6h1v2.6h-1zM142.9 135.2v5.1h.6l-.6 .6-.7-.6h.7"/>
<path d="M142.9 132v.6M143.3 139.2l.7 .8v-.4v.4h-.4M143.3 138.6l.7 .8v-.4v.4h-.4M146.4 123.1h.9M147.3 121.9v2.5M148 124.4v1.9h.6l-.6 .6-.7-.6h.7M148 120.6v1.3M160.7 138.9v2h.6l-.6 .6-.7-.6h.7M160.7 135.2v2.7M160.7 135.2l-.4 .6M160.7 135.2l.3 .6M162.2 123.1h2.6"/>
<path d="M162.2 121.2h2.6M162.2 125h2.6M162.2 126.9h2.6M164.8 128.8h-2.6v.7h.7l-.7 .6-.6-.6h.6M172.4 128.8h2.5v.7l-.1 .4M172.4 123.1h2.5M172.4 121.2h2.5M172.4 125h2.5M172.4 126.9h2.5M174.3 129.9l.1-.4h1.1l-.2 .4M174.7 129.5l-.1 .4M175.2 129.5l-.1 .4"/>
<path d="M177.2 138.9v2l-.2 .4M177.2 135.2v2.7M177.2 135.2l-.4 .6M177.2 135.2l.3 .6M185.5 130.1h1.1v2.5h-1.1zM186.1 126.9v1.3M186.1 129.5v.6M186.1 132.6v.7M186.1 126.9l-.4 .7M186.1 126.9l.3 .7M191.8 125.7l.1-.4h1l-.1 .4M192.2 125.3l-.2 .4"/>
<path d="M192.4 123.3v2l-.1 .4M192.7 125.3l-.2 .4M193.7 138.1l.1-.4h1l-.1 .4M194.1 137.7l-.2 .4M194.3 137.1v.6l-.1 .4M194.3 128.2h1.3M194.3 130.7h1.3M194.3 133.3h1.3M194.3 135.8h1.3M194.6 137.7l-.2 .4M195.6 126.9h8.9v10.2h-8.9zM204.5 128.2h1.2"/>
<path d="M204.5 130.7h1.2M204.5 133.3h1.2M204.5 135.8h1.2M207.3 128.8v1.4M207.3 131.2v1.4M207.3 124.7h1.9M208.6 130.7h.6M208.6 135.8h.6M209.2 130.2h2.6v1h-2.6zM209.2 135.3h2.6v1h-2.6zM209.2 124.1v1.2M211.8 130.7h.6"/>
<path d="M211.8 135.8h.6M212.4 123.4v1.3h-1.9M212.4 123.4l-.4 .7M212.4 123.4l.4 .7M215.3 132.4l.1-.4h1l-.1 .4M215.6 132l-.1 .4M215.9 128.8h2.5M215.9 133.9h2.5M215.9 135.2h2.5M215.9 130.1h2.5M215.9 132.6h2.5M216.2 132l-.2 .4"/>
<path d="M218.4 126.3h8.9v11.4h-8.9zM218.4 131.4h-2.5v.6l-.1 .4M227.3 128.8h2.6M227.3 131.4h2.6M227.3 133.9h2.6M227.3 136.5h2.6M227.3 135.2h2.6M227.3 130.1h2.6M227.3 132.6h2.6M227.3 127.6h2.6M230.2 127h5.9v1.1h-5.9l-.3-.5zM237.6 130.7h1v2.6h-1z"/>
<path d="M238.1 127.6v1.2M238.1 130.1v.6M238.1 133.3v.6M238.1 127.6l-.4 .6M238.1 127.6l.4 .6M243.8 126.4l.2-.4h1l-.1 .4M244.2 126l-.1 .4M244.5 123.9v2.1l-.2 .4M244.5 120.3v2.6M244.5 120.3l-.4 .6M244.5 120.3l.4 .6M244.7 126l-.1 .4"/>
<path d="M245.7 138.7l.2-.3h1l-.1 .3M246.1 138.4l-.1 .3M246.4 137.7v.7l-.1 .3M246.4 128.8h1.2M246.4 131.4h1.2M246.4 133.9h1.2M246.4 136.5h1.2M246.6 138.4l-.1 .3M247.6 127.6h8.9v10.1h-8.9zM256.5 128.8h1.3M256.5 131.4h1.3M256.5 133.9h1.3"/>
<path d="M256.5 136.5h1.3M259.4 129.5v1.4M259.4 131.9v1.4M259.4 125.3h1.9M260.7 131.4h.6M260.7 136.5h.6M261.3 130.9h2.5v1h-2.5zM261.3 135.9h2.5v1.1h-2.5zM261.3 124.7v1.3M263.8 131.4h.7M263.8 136.5h.7M264.5 124.1v1.2h-1.9"/>
<path d="M264.5 124.1l-.4 .6M264.5 124.1l.4 .6M267.3 133l.2-.4h1l-.1 .4M267.7 132.6l-.1 .4M268 130.7h2.5M268 133.3h2.5M268 135.8h2.5M268 129.5h2.5M268 134.6h2.5M268.2 132.6l-.1 .4M270.5 126.9h8.9v11.5h-8.9zM270.5 132h-2.5v.6l-.2 .4"/>
<path d="M279.4 128.2h2.5M279.4 130.7h2.5M279.4 133.3h2.5M279.4 135.8h2.5M279.4 129.5h2.5M279.4 132h2.5M279.4 134.6h2.5M279.4 137.1h2.5M282.3 127.6h5.8v1.2h-5.8l-.4-.6zM291 130.2h1M5 155.3h1M9.5 160v.6"/>
<path d="M13 140.6h1.3M13 141.9h1.3M14 160v.6M18.4 160v.6M19.4 143.1v1.9h.6l-.6 .7-.7-.7h.7M22.9 160v.6M24.4 140.6h1.3M27.3 160v.6M31.7 160v.6M33.3 148.2v1.3h1.4M33.3 148.2l-.3 .6M33.3 148.2l.4 .6"/>
<path d="M35.8 149.5h1.3M36.2 160v.6M37.5 149.5v.6h.6l-.6 .6-.7-.6h.7M37.8 150.7h1.9M37.8 153.3h1.9M37.8 152h1.9M37.8 149.5h1.9M39.7 148.8h1.3v5.1h-1.3zM39.7 153.2h.6v.1h-.6zM39.7 151.9h.6v.2h-.6zM39.7 149.4h.6v.1h-.6zM39.7 150.7h.6v.1h-.6z"/>
<path d="M40.6 160v.6M47.3 144.1h5.1v7.6h-5.1zM47.5 145h1.6v.1l-.1 .5h-1.4zM48.6 146.8h.3l.3 .6h.6M48.6 151.7v1.3M48.9 146.8h1.3M49.5 146.2h-.3l-.6 .6h-.3M49.8 151.3h.1v.4h-.1zM49.8 151.7v1.9h.7l-.7 .6-.6-.6h.6M52 150.4h.4v.1h-.4zM52 149.1h.4v.1h-.4zM52 147.8h.4v.1h-.4z"/>
<path d="M52 145.3h.4v.1h-.4zM52.4 147.9h1.3M52.4 149.2h1.3M52.4 150.4h1.3M52.4 145.3h3.2M56.8 144.7v1.3M58.7 144.1l-.3 .6M58.7 144.1v1.2h-1.9M58.7 144.1l.4 .6M60.6 151.7h4.5M60.6 147.9h1.3M60.6 146.9h4.5"/>
<path d="M60.6 144.7l-.3 .6M60.6 144.7v1.3M60.6 144.7l.4 .6M61.9 151.1l1.3 .6-1.3 .6zM61.9 147.3l1.3 .6-1.3 .6zM61.9 146.3l1.3 .6-1.3 .7zM63.2 147.9h1.9M63.2 146.3v2.2M63.2 151.1v1.2M64.2 150.9v-.3h-.4h.4l-.8 .7M64.2 147.1v-.4h-.4h.4l-.8 .8M64.2 146.2v-.4h-.4h.4l-.8 .8"/>
<path d="M64.8 150.9v-.3h-.3h.3l-.7 .7M64.8 147.1v-.4h-.3h.3l-.7 .8M64.8 146.2v-.4h-.3h.3l-.7 .8M65.1 148.3h2.5v1h-2.5zM65.1 151.2h2.5v1h-2.5zM65.1 147.4h2.5v1h-2.5zM65.1 146.4h2.5v1h-2.5zM67.6 151.7h3.2M67.6 147.9h3.2M67.6 146.9h3.2M68.3 149.8h2.5M68.3 146h2.5"/>
<path d="M68.3 150.7h2.5M68.3 148.8h2.5M70.8 145.3h6.4v7h-6.4zM77.2 151.7h2.5M77.2 149.8h2.5M77.2 147.9h2.5M77.2 146h2.5M77.2 150.7h2.5M77.2 148.8h2.5M77.2 146.9h2.5M81.9 146v.6h.6l-.6 .7-.6-.7h.6M83.8 147.6l-.4 .6"/>
<path d="M83.8 147.6v1.2M83.8 147.6l.4 .6M94.9 149.2h1.3M98.3 148l-1.6 1M98.4 160h3.8l1.9-2h.7v.7h1.2l.7-.7h6.3v12.1h-14.6zM98.7 150.4h1.3v.7h.6l-.6 .6-.6-.6h.6M98.7 147.9h1.3M110.8 149.2h1.3M111.1 158v-.6h-17.8v16.5h17.8v-3.8M114.2 148l-1.6 1M114.6 150.4h1.3v.7h.6l-.6 .6-.6-.6h.6M114.6 147.9h1.3"/>
<path d="M119.7 156.1l-.4 .7M119.7 156.1v2.7M119.7 159.8v1.4M119.7 156.1l.4 .7M124.1 157.4v1.4M124.1 159.8v1.4M126.7 149.2h1.3M128.6 159.8v2.1h.6l-.6 .6-.6-.6h.6M128.6 157.4v1.4M130 148l-1.5 1M130.5 150.4h1.3v.7h.6l-.6 .6-.7-.6h.7M130.5 147.9h1.3"/>
<path d="M134.6 159l-.4 .6M134.6 159v5.1M134.6 159l.4 .6M142.6 149.2h1.2M145.9 148l-1.6 1M146.4 150.4h1.2v.7h.7l-.7 .6-.6-.6h.6M146.4 147.9h1.2M162.2 140.9v1.3h2.6M162.2 153.6h2.6M162.2 151.7h2.6M162.2 149.8h2.6M162.2 147.9h2.6"/>
<path d="M162.2 146h2.6M162.2 144.1h2.6M162.2 140.9l-.3 .6M162.2 140.9l.4 .6M164.8 140.9h7.6v15.9h-7.6zM164.8 155.5h-2.6v.6h.7l-.7 .7-.6-.7h.6M172.4 155.5h2.5v.6l-.1 .4M172.4 153.6h2.5M172.4 151.7h2.5M172.4 149.8h2.5M172.4 147.9h2.5M172.4 146h2.5"/>
<path d="M172.4 144.1h2.5M174.3 156.5l.1-.4h1.1l-.2 .4M174.7 156.1l-.1 .4M174.9 140.9v1.3h-2.5M174.9 140.9l-.3 .6M174.9 140.9l.4 .6M175.2 156.1l-.1 .4M176.5 141.3l.2-.4h1l-.2 .4M176.9 140.9l-.1 .4M177.4 140.9l-.1 .4M185.9 152h1v2.6h-1zM186.4 148.8v1.3"/>
<path d="M186.4 151.4v.6M186.4 154.6v.6M186.4 148.8l-.4 .7M186.4 148.8l.4 .7M191.8 147.6l.1-.3h1l-.1 .3M192.2 147.3l-.2 .3M192.4 145.2v2.1l-.1 .3M192.4 141.5v2.7M192.4 141.5l-.4 .7M192.4 141.5l.4 .7M192.7 147.3l-.2 .3M194.1 159.6l-.2 .4"/>
<path d="M194.3 159v.6l-.1 .4M194.3 152.6h1.3M194.3 157.7h1.3M194.3 150.1h1.3M194.3 155.2h1.3M194.6 159.6l-.2 .4M195.6 148.8h8.9v10.2h-8.9zM204.5 152.6h1.2M204.5 157.7h1.2M204.5 150.1h1.2M204.5 155.2h1.2M207.3 146.6h1.9"/>
<path d="M207.3 150.7v1.4M207.3 153.2v1.4M208.6 152.6h.6M208.6 157.7h.6M209.2 152.1h2.6v1.1h-2.6zM209.2 157.2h2.6v1h-2.6zM209.2 146v1.3M211.8 152.6h.6M211.8 157.7h.6M212.4 145.3v1.3h-1.9M212.4 145.3l-.4 .7M212.4 145.3l.4 .7"/>
<path d="M215.3 154.3l.1-.4h1l-.1 .4M215.6 153.9l-.1 .4M215.9 150.7h2.5M215.9 155.8h2.5M215.9 157.1h2.5M215.9 152h2.5M215.9 154.6h2.5M216.2 153.9l-.2 .4M218.4 148.2h8.9v11.4h-8.9zM218.4 153.3h-2.5v.6l-.1 .4M227.3 158.4h2.6M227.3 150.7h2.6"/>
<path d="M227.3 153.3h2.6M227.3 155.8h2.6M227.3 157.1h2.6M227.3 152h2.6M227.3 154.6h2.6M227.3 149.5h2.6M230.2 148.9h5.9v1.1h-5.9l-.3-.5zM237.9 152.6h1.1v2.6h-1.1zM238.4 149.5v1.2M238.4 152v.6M238.4 155.2v.6M238.4 149.5l-.3 .6"/>
<path d="M238.4 149.5l.4 .6M243.8 148.3l.2-.4h1l-.1 .4M244.2 147.9l-.1 .4M244.5 145.9v2l-.2 .4M244.5 142.2v2.6M244.5 142.2l-.4 .6M244.5 142.2l.4 .6M244.7 147.9l-.1 .4M246.4 159.6v.7l-.1 .3M246.4 158.4h1.2M246.4 150.7h1.2M246.4 153.3h1.2"/>
<path d="M246.4 155.8h1.2M247.6 149.5h8.9v10.1h-8.9zM256.5 158.4h1.3M256.5 150.7h1.3M256.5 153.3h1.3M256.5 155.8h1.3M259.4 151.4v1.4M259.4 153.8v1.4M259.4 147.3h1.9M260.7 158.4h.6M260.7 153.3h.6M261.3 157.9h2.5v1h-2.5z"/>
<path d="M261.3 152.8h2.5v1h-2.5zM261.3 146.6v1.3M263.8 158.4h.7M263.8 153.3h.7M264.5 146v1.3h-1.9M264.5 146l-.4 .6M264.5 146l.4 .6M267.3 154.9l.2-.3h1l-.1 .3M267.7 154.6l-.1 .3M268 152.6h2.5M268 157.7h2.5M268 155.2h2.5"/>
<path d="M268 151.4h2.5M268 156.5h2.5M268.2 154.6l-.1 .3M270.5 148.8h8.9v11.5h-8.9zM270.5 153.9h-2.5v.7l-.2 .3M279.4 152.6h2.5M279.4 157.7h2.5M279.4 150.1h2.5M279.4 155.2h2.5M279.4 151.4h2.5M279.4 153.9h2.5M279.4 156.5h2.5"/>
<path d="M279.4 159h2.5M282.3 149.5h5.8v1.2h-5.8l-.4-.6zM291 155.3h1M8.9 165h1.3l-.7 1.3zM8.9 166.3h1.3M9 160.6h1v2.5h-1zM9.5 163.1v5.1h.7l-.7 .6-.6-.6h.6M9.9 167.2l.8 .8v-.4v.4h-.4M9.9 166.6l.8 .7v-.4v.4h-.4M13.3 165h1.3l-.6 1.3zM13.3 166.3h1.3M13.5 160.6h1v2.5h-1z"/>
<path d="M14 163.1v5.1h.6l-.6 .6-.7-.6h.7M14.4 167.2l.7 .8v-.4v.4h-.4M14.4 166.6l.7 .7v-.4v.4h-.4M17.8 165h1.2l-.6 1.3zM17.8 166.3h1.2M17.9 160.6h1v2.5h-1zM18.4 163.1v5.1h.6l-.6 .6-.6-.6h.6M18.8 167.2l.8 .8v-.4v.4h-.4M18.8 166.6l.8 .7v-.4v.4h-.4M22.2 165h1.3l-.6 1.3zM22.2 176.1l-.4 .7M22.2 176.1v1.3"/>
<path d="M22.2 176.1l.4 .7M22.2 166.3h1.3M22.4 160.6h1v2.5h-1zM22.9 163.1v5.1h.6l-.6 .6-.7-.6h.7M23.2 167.2l.8 .8v-.4v.4h-.4M23.2 166.6l.8 .7v-.4v.4h-.4M23.5 177.4h1.4M25.9 177.4h1.4M26.7 165h1.2l-.6 1.3zM26.7 166.3h1.2M26.8 160.6h1v2.5h-1zM27.3 163.1v5.1h.6l-.6 .6-.6-.6h.6"/>
<path d="M27.7 167.2l.7 .8v-.4v.4h-.3M27.7 166.6l.7 .7v-.4v.4h-.3M31.1 165h1.3l-.7 1.3zM31.1 166.3h1.3M31.2 160.6h1.1v2.5h-1.1zM31.7 163.1v5.1h.7l-.7 .6-.6-.6h.6M32.1 167.2l.8 .8v-.4v.4h-.4M32.1 166.6l.8 .7v-.4v.4h-.4M35.6 165h1.2l-.6 1.3zM35.6 166.3h1.2M35.7 160.6h1v2.5h-1zM36.2 163.1v5.1h.6l-.6 .6-.6-.6h.6"/>
<path d="M36.6 167.2l.7 .8v-.4v.4h-.3M36.6 166.6l.7 .7v-.4v.4h-.3M40 165h1.3l-.7 1.3zM40 166.3h1.3M40.1 160.6h1v2.5h-1zM40.6 163.1v5.1h.7l-.7 .6-.6-.6h.6M41 167.2l.8 .8v-.4v.4h-.4M41 166.6l.8 .7v-.4v.4h-.4M49.5 177.4l-.4 .6M49.5 177.4v1.3h1.2M49.5 177.4l.4 .6M51.3 178a.81 .81 0 0 1 1.3 0"/>
<path d="M52.4 163.1h2.5M52.4 166.9h2.5M52.8 178a.81 .81 0 0 1 1.3 0M54.7 178.7h1.2M54.9 161.9h6.4v6.3h-6.4zM54.9 165h-2.5v.7h.6l-.6 .6-.6-.6h.6M59.4 163.1l-1.3 1.9M61.3 165h2.5v.7h.7l-.7 .6-.6-.6h.6M61.3 163.1h2.5M61.3 166.9h2.5M65.7 179.3v1.3M65.7 179.3l-.4 .7"/>
<path d="M65.7 179.3l.4 .7M79.2 168.8h1v2.6h-1zM79.7 166.9v1.9M79.7 171.4v.6M79.7 166.9l-.4 .7M79.7 166.9l.4 .7M87.6 163.1h.7M87.6 168.2h.7M87.6 161.9h.7M87.6 165.7h.7M88.3 167.7h2.5v1h-2.5zM88.3 161.3h2.5v1.1h-2.5z"/>
<path d="M88.3 162.6h2.5v1h-2.5zM88.3 165.2h2.5v1h-2.5zM90.2 179.3v1.3M90.2 179.3l-.4 .7M90.2 179.3l.4 .7M90.5 173.6v.6h.6l-.6 .7-.6-.7h.6M90.8 163.1h2.5M90.8 168.2h2.5M90.8 165.7h2.5M91.4 163.1l-.3 .7M91.4 163.1v1.3h1.9M91.4 163.1l.4 .7"/>
<path d="M91.4 161.9h1.9M91.4 160.6h1.9M91.4 170.7h1.9M91.4 172h1.9M91.4 169.5h1.9M93.3 166.9h-1.9v.7h.7l-.7 .6-.6-.6h.6M111.1 172h1.9M118.7 164.1v1.2h.7M118.7 164.1l-.3 .6M118.7 164.1l.4 .6M119.4 164.8h2.5v1.1h-2.5zM121.9 165.3h.7"/>
<path d="M123.2 169.2v1.2h3.8M123.2 173h3.8M123.2 178h3.8M123.2 165.3h3.2M123.2 169.2l-.4 .6M123.2 169.2l.4 .6M123.2 167.9h3.8M123.2 174.2h3.8M123.2 176.8h3.8M126.7 167.6l.6 .6M126.7 170.1l.6 .6M127 164.1h40v33h-40z"/>
<path d="M127.3 167.6l-.6 .6M127.3 170.1l-.6 .6M134.3 163.8l.6 .6M134.9 163.8l-.6 .6M135.6 163.8l.6 .6M135.9 160.3v3.8M136.2 163.8l-.6 .6M136.8 163.8l.7 .6M137.2 160.3v3.8M137.5 163.8l-.7 .6M167 170.4h3.8M167 175.5h3.8"/>
<path d="M167 178h3.8M167 165.3h3.8M167 167.9h3.8M167 179.3h3.8M167 171.7h3.8M167 166.6h3.8M167 174.2h3.8M167 176.8h3.8M167 169.2h3.8M170.4 179.8v-.4h.4h-.4l.8 .8M172.1 180v2.5M178.4 179.3v1.3h-.6"/>
<path d="M178.4 179.3l-.3 .7M178.4 179.3l.4 .7M185.5 171.7h1.1v2.5h-1.1zM186.1 168.5v1.3M186.1 171.1v.6M186.1 174.2v.7M186.1 168.5l-.4 .7M186.1 168.5l.3 .7M191.8 167.3l.1-.4h1l-.1 .4M192.2 166.9l-.2 .4M192.4 164.9v2l-.1 .4M192.4 161.2v2.7"/>
<path d="M192.4 161.2l-.4 .7M192.4 161.2l.4 .7M192.7 166.9l-.2 .4M193.7 179.7l.1-.4h1l-.1 .4M193.7 160l.1-.4h1l-.1 .4M194.1 179.3l-.2 .4M194.3 178.7v.6l-.1 .4M194.3 177.4h1.3M194.3 169.8h1.3M194.3 172.3h1.3M194.3 174.9h1.3M194.6 179.3l-.2 .4"/>
<path d="M195.6 168.5h8.9v10.2h-8.9zM204.5 177.4h1.2M204.5 169.8h1.2M204.5 172.3h1.2M204.5 174.9h1.2M207.3 170.4v1.4M207.3 172.8v1.4M207.3 166.3h1.9M208.6 177.4h.6M208.6 172.3h.6M209.2 171.8h2.6v1h-2.6zM209.2 176.9h2.6v1h-2.6z"/>
<path d="M209.2 165.7v1.2M211.8 177.4h.6M211.8 172.3h.6M212.4 165v1.3h-1.9M212.4 165l-.4 .7M212.4 165l.4 .7M215.3 174l.1-.4h1l-.1 .4M215.6 173.6l-.1 .4M215.9 170.4h2.5M215.9 175.5h2.5M215.9 171.7h2.5M215.9 174.2h2.5"/>
<path d="M215.9 176.8h2.5M216.2 173.6l-.2 .4M218.4 167.9h8.9v11.4h-8.9zM218.4 173h-2.5v.6l-.1 .4M227.3 170.4h2.6M227.3 173h2.6M227.3 175.5h2.6M227.3 178h2.6M227.3 171.7h2.6M227.3 174.2h2.6M227.3 176.8h2.6M227.3 169.2h2.6"/>
<path d="M230.2 168.6h5.9v1.1h-5.9l-.3-.5zM237.6 172.3h1v2.6h-1zM238.1 169.2v1.2M238.1 171.7v.6M238.1 174.9v.6M238.1 169.2l-.4 .6M238.1 169.2l.4 .6M243.8 168l.2-.4h1l-.1 .4M244.2 167.6l-.1 .4M244.5 165.5v2.1l-.2 .4M244.5 161.9v2.6M244.5 161.9l-.4 .6"/>
<path d="M244.5 161.9l.4 .6M244.7 167.6l-.1 .4M245.7 160.6l.2-.3h1l-.1 .3M246.1 160.3l-.1 .3M246.1 180l-.1 .3M246.4 179.3v.7l-.1 .3M246.4 170.4h1.2M246.4 173h1.2M246.4 175.5h1.2M246.4 178h1.2M246.6 160.3l-.1 .3M246.6 180l-.1 .3"/>
<path d="M247.6 169.2h8.9v10.1h-8.9zM256.5 170.4h1.3M256.5 173h1.3M256.5 175.5h1.3M256.5 178h1.3M259.4 166.9h1.9M259.4 171.1v1.4M259.4 173.5v1.4M260.7 173h.6M260.7 178h.6M261.3 172.5h2.5v1h-2.5zM261.3 177.5h2.5v1.1h-2.5z"/>
<path d="M261.3 166.3v1.3M263.8 173h.7M263.8 178h.7M264.5 165.7v1.2h-1.9M264.5 165.7l-.4 .6M264.5 165.7l.4 .6M267.3 174.6l.2-.4h1l-.1 .4M267.7 174.2l-.1 .4M268 177.4h2.5M268 172.3h2.5M268 174.9h2.5M268 171.1h2.5"/>
<path d="M268 176.1h2.5M268.2 174.2l-.1 .4M270.5 168.5h8.9v11.5h-8.9zM270.5 173.6h-2.5v.6l-.2 .4M279.4 177.4h2.5M279.4 169.8h2.5M279.4 172.3h2.5M279.4 174.9h2.5M279.4 178.7h2.5M279.4 171.1h2.5M279.4 173.6h2.5M279.4 176.1h2.5"/>
<path d="M282.3 169.2h5.8v1.2h-5.8l-.4-.6zM5 180.2h1M16.2 181.9h1.9M16.2 183.1h1.9M16.2 184.4h1.9M16.2 185.7h1.9M16.2 192h1.9M16.2 186.9h1.9M16.2 193.3h1.9M16.2 188.2h1.9M16.2 189.5h1.9M16.2 190.7h1.9"/>
<path d="M18.1 181.2h1.3v12.7h-1.3zM18.1 189.4h.6v.1h-.6zM18.1 190.7h.6v.1h-.6zM18.1 192h.6v.1h-.6zM18.1 193.2h.6v.2h-.6zM18.1 188.1h.6v.2h-.6zM18.1 185.6h.6v.1h-.6zM18.1 184.3h.6v.2h-.6zM18.1 183.1h.6v.1h-.6zM18.1 181.8h.6v.1h-.6zM18.1 186.9h.6v.1h-.6zM22.2 181.9h1.9"/>
<path d="M22.2 183.1h1.9M22.2 184.4h1.9M22.2 185.7h1.9M22.2 192h1.9M22.2 186.9h1.9M22.2 193.3h1.9M22.2 188.2h1.9M22.2 189.5h1.9M22.2 190.7h1.9M24.1 181.2h2.6v12.7h-2.6zM24.1 189.4h.7v.1h-.7zM24.1 190.7h.7v.1h-.7z"/>
<path d="M24.1 192h.7v.1h-.7zM24.1 193.2h.7v.2h-.7zM24.1 188.1h.7v.2h-.7zM24.1 185.6h.7v.1h-.7zM24.1 184.3h.7v.2h-.7zM24.1 183.1h.7v.1h-.7zM24.1 181.8h.7v.1h-.7zM24.1 186.9h.7v.1h-.7zM26 189.4h.7v.1h-.7zM26 190.7h.7v.1h-.7zM26 192h.7v.1h-.7zM26 193.2h.7v.2h-.7z"/>
<path d="M26 188.1h.7v.2h-.7zM26 185.6h.7v.1h-.7zM26 184.3h.7v.2h-.7zM26 183.1h.7v.1h-.7zM26 181.8h.7v.1h-.7zM26 186.9h.7v.1h-.7zM26.7 193.3h1.9v.6h.6l-.6 .7-.7-.7h.7M26.7 181.9h1.9M26.7 183.1h1.9M26.7 184.4h1.9M26.7 185.7h1.9M26.7 192h1.9"/>
<path d="M26.7 186.9h1.9M26.7 188.2h1.9M26.7 189.5h1.9M26.7 190.7h1.9M37.5 194.6h1.2M37.5 185.7h1.2M37.5 192h1.2M37.5 186.9h1.2M37.5 193.3h1.2M37.5 188.2h1.2M37.5 189.5h1.2M37.5 190.7h1.2"/>
<path d="M38.7 184.4h6.4v12.7h-6.4zM38.7 195.8h-1.2v.7h.6l-.6 .6-.7-.6h.7M46.4 194.6h1.9M46.4 185.7h1.9M46.4 192h1.9M46.4 186.9h1.9M46.4 193.3h1.9M46.4 188.2h1.9M46.4 189.5h1.9M46.4 190.7h1.9M46.7 195.3h4.9v1.1h-4.9l-.3-.6zM46.8 180.7h5l.3 .5-.3 .6h-5z"/>
<path d="M48.3 185h1.2v10.2h-1.2zM48.3 192h.6v.1h-.6zM48.3 193.2h.6v.2h-.6zM48.3 194.5h.6v.1h-.6zM48.3 190.7h.6v.1h-.6zM48.3 188.1h.6v.2h-.6zM48.3 186.9h.6v.1h-.6zM48.3 185.6h.6v.1h-.6zM48.3 189.4h.6v.1h-.6zM52.7 194.6h1.9M52.7 185.7h1.9M52.7 192h1.9"/>
<path d="M52.7 186.9h1.9M52.7 193.3h1.9M52.7 188.2h1.9M52.7 189.5h1.9M52.7 190.7h1.9M54 181.2h1.4M54.6 185h2.5v10.2h-2.5zM54.6 192h.6v.1h-.6zM54.6 193.2h.6v.2h-.6zM54.6 194.5h.6v.1h-.6zM54.6 190.7h.6v.1h-.6zM54.6 188.1h.6v.2h-.6z"/>
<path d="M54.6 186.9h.6v.1h-.6zM54.6 185.6h.6v.1h-.6zM54.6 189.4h.6v.1h-.6zM56.4 181.2h1.4M56.5 192h.6v.1h-.6zM56.5 193.2h.6v.2h-.6zM56.5 194.5h.6v.1h-.6zM56.5 190.7h.6v.1h-.6zM56.5 188.1h.6v.2h-.6zM56.5 186.9h.6v.1h-.6zM56.5 185.6h.6v.1h-.6zM56.5 189.4h.6v.1h-.6z"/>
<path d="M57.1 194.6h2v.6h.6l-.6 .6-.7-.6h.7M57.1 185.7h2M57.1 192h2M57.1 186.9h2M57.1 193.3h2M57.1 188.2h2M57.1 189.5h2M57.1 190.7h2M65.2 182.5h1v2.5h-1zM65.2 195.2h1v2.5h-1zM65.7 181.9v.6M65.7 185v.7"/>
<path d="M65.7 192v1.3M65.7 194.6v.6M65.7 197.7v.7M65.7 192l-.4 .7M65.7 192l.4 .7M68.1 193.9h1v2.6h-1zM68.1 181.2h1v2.6h-1zM68.6 180.6v.6M68.6 183.8v.6M68.6 193.3v.6M68.6 196.5v.6M68.7 199h1v2.5h-1z"/>
<path d="M68.7 186.3h1v2.5h-1zM69.2 185.7v.6M69.2 188.8v.7M69.2 198.4v.6M71.9 197.7h1v2.6h-1zM71.9 185h1v2.6h-1zM72.4 184.4v.6M72.4 187.6v.6M72.4 197.1v.6M75.9 180.6v1.3h1.4M75.9 193.3v1.3h1.4M75.9 193.3l-.4 .6"/>
<path d="M75.9 193.3l.4 .6M75.9 180.6l-.4 .6M75.9 180.6l.4 .6M78.3 181.9h1.4M78.3 194.6h1.4M80 194.6v.6h.6l-.6 .6-.6-.6h.6M80 181.9v.6h.6l-.6 .6-.6-.6h.6M80.3 181.9h1.9M80.3 194.6h1.9M80.3 195.8h1.9M80.3 197.1h1.9M80.3 198.4h1.9"/>
<path d="M80.3 183.1h1.9M80.3 184.4h1.9M80.3 185.7h1.9M82.2 193.9h1.3v5.1h-1.3zM82.2 198.3h.7v.1h-.7zM82.2 197h.7v.2h-.7zM82.2 194.5h.7v.1h-.7zM82.2 195.8h.7v.1h-.7zM82.2 181.2h1.3v5.1h-1.3zM82.2 185.6h.7v.1h-.7zM82.2 184.3h.7v.2h-.7zM82.2 181.8h.7v.1h-.7z"/>
<path d="M82.2 183.1h.7v.1h-.7zM89.7 182.5h1v2.5h-1zM89.7 195.2h1v2.5h-1zM90.2 181.9v.6M90.2 185v.7M90.2 192v1.3M90.2 194.6v.6M90.2 197.7v.7M90.2 192l-.4 .7M90.2 192l.4 .7M92.5 181.2h1v2.6h-1zM92.5 193.9h1v2.6h-1z"/>
<path d="M93 180.6v.6M93 183.8v.6M93 193.3v.6M93 196.5v.6M93.2 186.3h1v2.5h-1zM93.2 199h1v2.5h-1zM93.7 185.7v.6M93.7 188.8v.7M93.7 198.4v.6M96.3 185h1v2.6h-1zM96.3 197.7h1v2.6h-1zM96.8 184.4v.6"/>
<path d="M96.8 187.6v.6M96.8 197.1v.6M100.3 180.6v1.3h1.4M100.3 193.3v1.3h1.4M100.3 180.6l-.4 .6M100.3 180.6l.4 .6M100.3 193.3l-.4 .6M100.3 193.3l.4 .6M102.7 181.9h1.4M102.7 194.6h1.4M104.5 181.9v.6h.6l-.6 .6-.7-.6h.7M104.5 194.6v.6h.6l-.6 .6-.7-.6h.7"/>
<path d="M104.8 181.9h1.9M104.8 194.6h1.9M104.8 195.8h1.9M104.8 197.1h1.9M104.8 198.4h1.9M104.8 183.1h1.9M104.8 184.4h1.9M104.8 185.7h1.9M106.7 181.2h1.2v5.1h-1.2zM106.7 185.6h.6v.1h-.6zM106.7 184.3h.6v.2h-.6zM106.7 181.8h.6v.1h-.6z"/>
<path d="M106.7 183.1h.6v.1h-.6zM106.7 193.9h1.2v5.1h-1.2zM106.7 198.3h.6v.1h-.6zM106.7 197h.6v.2h-.6zM106.7 194.5h.6v.1h-.6zM106.7 195.8h.6v.1h-.6zM119.4 194.6h1.4M121.8 194.6h5.2M123.2 181.9h3.8M123.2 184.4h3.8M123.2 185.7h3.8M123.2 180.6h3.8"/>
<path d="M123.2 188.2h3.8M123.2 189.5h3.8M126.7 194.2l.6 .7M127 195.8h-3.8v.7h.6l-.6 .6-.6-.6h.6M127.3 194.2l-.6 .7M134.3 196.8l.6 .6M134.6 197.1v3.8M134.9 196.8l-.6 .6M135.6 196.8l.6 .6M135.9 197.1v3.8M136.2 196.8l-.6 .6M136.8 196.8l.7 .6"/>
<path d="M137.2 197.1v4.4h.6l-.6 .7-.7-.7h.7M137.5 196.8l-.7 .6M167 181.9h8.3M167 194.6h3.8M167 195.8h3.8M167 184.4h3.8M167 185.7h3.8M167 180.6h8.3M167 192h3.8M167 186.9h3.8M167 193.3h3.8M167 188.2h3.8"/>
<path d="M167 189.5h3.8M167 190.7h3.8M170.4 181.1v-.4h.4h-.4l.8 .8M171.1 181.1v-.4h.3h-.3l.7 .8M172.1 181.9l1.3-.7v1.3zM172.1 180.6l1.3-.6v1.2zM175.3 181.4h2.5v1h-2.5zM175.3 180.1h2.5v1h-2.5zM177.8 181.9h.6M180.3 191.4h5.1v7.6h-5.1zM180.6 192.3h1.6v.6h-1.6zM181.6 194.1h.3l.3 .6h.7"/>
<path d="M181.6 199v1.3M181.9 194.1h1.3M182.6 193.5h-.4l-.6 .6h-.3M182.8 198.6h.1v.4h-.1zM182.9 199v1.9h.6l-.6 .6-.7-.6h.7M185 196.4h.4v.1h-.4zM185 195.1h.4v.2h-.4zM185 192.6h.4v.1h-.4zM185.4 192.7h1.3M185.4 196.5h1.3M185.4 195.2h1.3M188.3 191.4l-.4 .6"/>
<path d="M188.3 191.4v1.3M188.3 191.4l.4 .6M192.4 187.3h7.6v1.2h-7.6zM193 187.9h.1v.6h-.1zM193 188.5v1.9M193.7 193.6h1.2M194.2 187.9h.2v.6h-.2zM194.3 188.5v3.8M194.3 193.6v1.9h2.1M195.5 187.9h.1v.6h-.1zM195.6 188.5v2.6h.6l-.6 .6-.7-.6h.7M196.8 187.9h.1v.6h-.1z"/>
<path d="M196.8 188.5v1.9M196.9 194.9a1.58 1.58 0 0 1 2.5 0M198.1 187.9h.1v.6h-.1zM198.1 188.5v1.9M199.3 187.9h.2v.6h-.2zM199.4 188.5v1.9M201.9 194.2v1.3h-2.1M201.9 194.2l-.4 .7M201.9 194.2l.4 .7M237 188.2h54v16h-54zM237 199h54M237 196h54"/>
<path d="M242.3 196.3l-.7 1M244.5 198l-.2-.1-.1 .2v.3h.3M244.8 198h.3l.1 .4M244.8 197.7v.7M245.7 180.3l.2-.3h1l-.1 .3M291 180.2h1M30 204.2v1M55 204.2v1M69.2 201.5v.7M72.4 200.3v.6M80 204.2v1M93.7 201.5v.7"/>
<path d="M96.8 200.3v.6M105 204.2v1M130 204.2v1M155 204.2v1M180 204.2v1M205 204.2v1M230 204.2v1M237 202.5h54M237 201h54M241.6 201.5l.2-.1 .2 .2-.5 .5h.5M247 201v1.5M250.8 203.5h.5"/>
<path d="M251.6 203.5h.1M252.1 202.7l-.2 .6h.5M252.3 203v.5M252.6 202.7a.85 .85 0 0 1 0 1.1M253.2 203.2h.5M254.1 203l.2-.2v.7M254.1 203.5h.4M255 204.2v1M268.3 205h.3M279 201v3.2M280 204.2v1M283.4 202.7l-.6 1"/>
<path d="M283.6 203l.2-.2v.7M283.6 203.5h.5"/>
<circle cx="111.1" cy="14.5" r=".25"/>
<circle cx="111.1" cy="17.1" r=".25"/>
<circle cx="113.1" cy="15.8" r=".25"/>
<circle cx="118" cy="15.8" r="1.41"/>
<circle cx="136.4" cy="13.3" r="1.41"/>
<circle cx="225.4" cy="14.5" r=".25"/>
<circle cx="227.4" cy="15.8" r=".25"/>
<circle cx="227.4" cy="13.3" r=".25"/>
<circle cx="233.6" cy="13.3" r="1.41"/>
<circle cx="35.9" cy="26" r=".44"/>
<circle cx="38.4" cy="26" r=".44"/>
<circle cx="225.4" cy="38" r=".25"/>
<circle cx="227.4" cy="39.3" r=".25"/>
<circle cx="232.9" cy="39.3" r="1.41"/>
<circle cx="239.1" cy="36.4" r=".44"/>
<circle cx="239.1" cy="39" r=".44"/>
<circle cx="12.3" cy="50.1" r=".25"/>
<circle cx="14.4" cy="50.1" r=".25"/>
<circle cx="225.4" cy="40.6" r=".25"/>
<circle cx="27.3" cy="130.7" r=".44"/>
<circle cx="29.8" cy="130.7" r=".44"/>
<circle cx="54.3" cy="126.3" r="1.41"/>
<circle cx="131.4" cy="122.1" r=".25"/>
<circle cx="131.4" cy="124.1" r=".25"/>
<circle cx="136.5" cy="122.1" r=".25"/>
<circle cx="136.5" cy="124.1" r=".25"/>
<circle cx="142.2" cy="122.1" r=".25"/>
<circle cx="142.2" cy="124.1" r=".25"/>
<circle cx="148" cy="124.1" r=".25"/>
<circle cx="148" cy="122.1" r=".25"/>
<circle cx="96.5" cy="149.2" r=".25"/>
<circle cx="98.5" cy="150.4" r=".25"/>
<circle cx="98.5" cy="147.9" r=".25"/>
<circle cx="112.3" cy="149.2" r=".25"/>
<circle cx="114.4" cy="150.4" r=".25"/>
<circle cx="114.4" cy="147.9" r=".25"/>
<circle cx="128.2" cy="149.2" r=".25"/>
<circle cx="130.2" cy="150.4" r=".25"/>
<circle cx="130.2" cy="147.9" r=".25"/>
<circle cx="144.1" cy="149.2" r=".25"/>
<circle cx="146.1" cy="147.9" r=".25"/>
<circle cx="146.1" cy="150.4" r=".25"/>
<circle cx="51.2" cy="178.7" r=".44"/>
<circle cx="52.7" cy="178.7" r=".46"/>
<circle cx="54.2" cy="178.7" r=".44"/>
<circle cx="58.1" cy="165" r="1.42"/>
<circle cx="126.7" cy="165.3" r=".32"/>
<circle cx="196.8" cy="195.5" r=".44"/>
<circle cx="199.4" cy="195.5" r=".44"/>
</g>
<g fill="none" stroke="#840000" stroke-width=".25">
<path d="M36.8 13h2M36.8 12.2h2M54.5 9.7v2M55.3 9.7v2M60.3 19.9h2M73.9 19.4h2M73.9 18.6h2M82.8 15.9h2M82.8 15.1h2M94.2 15.9h2.1M94.2 15.1h2.1M180 17.4a1.63 1.63 0 0 1 2 0"/>
<path d="M180 16.4h2M194.6 17.4a1.63 1.63 0 0 1 2 0M194.6 16.4h2M248.9 12.7h2M248.9 11.9h2M248.9 18.4h2M248.9 17.6h2M12.4 38.3v1.3M14.3 38.3v1.3M60.3 20.6h2M109.5 28.6h2M109.5 27.8h2"/>
<path d="M113.9 28.6h2.1M113.9 27.8h2.1M118.4 28.6h2M118.4 27.8h2M122.8 28.6h2M122.8 27.8h2M127.3 28.6h2M127.3 27.8h2M131.7 28.6h2M131.7 27.8h2M136.1 28.6h2.1M136.1 27.8h2.1"/>
<path d="M140.6 28.6h2M140.6 27.8h2M145 28.6h2.1M145 27.8h2.1M248.9 24.1h2M248.9 23.4h2M248.9 29.8h2M248.9 29.1h2M248.9 35.6h2M248.9 34.8h2M10.1 41.3h2M10.1 40.5h2"/>
<path d="M13 52.9v2M13.7 52.9v2M14.5 41.3h2.1M14.5 40.5h2.1M174.9 54.3h2M174.9 53.5h2M180.6 43v2.1M181.4 43v2.1M186.3 53h2M186.3 52.3h2M191.1 53.3a1.63 1.63 0 0 1 2 0M191.1 52.3h2"/>
<path d="M202.5 52.4h2M202.5 51.6h2M207.9 51.7h2M207.9 51h2M218.1 51.7h2M218.1 51h2M248.9 41.3h2M248.9 40.5h2M251.1 53.6a1.63 1.63 0 0 1 2 0M251.1 52.6h2M256.2 53.6a1.63 1.63 0 0 1 2 0M256.2 52.6h2"/>
<path d="M261.2 53.3h2.1M261.2 52.6h2.1M266 53.3h2M266 52.6h2M191.4 61.9h2M191.4 61.1h2M206.3 69.8h2M206.3 69.1h2M243.5 62.5h2M243.5 61.8h2M258.4 70.5h2M258.4 69.7h2"/>
<path d="M191.4 81.6h2M191.4 80.8h2M206.3 89.5h2M206.3 88.8h2M243.5 82.2h2M243.5 81.5h2M258.4 90.2h2M258.4 89.4h2M79.3 119.2v3.3M80.1 119.2v3.3M100.6 112.1h2M100.6 111.3h2"/>
<path d="M106.9 112.1h2.1M106.9 111.3h2.1M159.6 112.1h2.1M159.6 111.3h2.1M176.1 112.1h2.1M176.1 111.3h2.1M191.4 103.5h2M191.4 102.7h2M206.3 111.4h2M206.3 110.7h2M243.5 104.1h2M243.5 103.4h2"/>
<path d="M258.4 112.1h2M258.4 111.3h2M9.8 131.8h2M9.8 131h2M12.3 120.2v2M13.1 120.2v2M22.8 120.2v2M23.6 120.2v2M54 125.3v1.9M70.1 139.4h2M70.1 138.6h2M78.7 124.3v2.1"/>
<path d="M79.4 124.3v2.1M159.6 138.7h2.1M159.6 138h2.1M176.1 138.7h2.1M176.1 138h2.1M191.4 123.2h2M191.4 122.4h2M206.3 131.1h2M206.3 130.4h2M243.5 123.8h2M243.5 123.1h2M258.4 131.8h2"/>
<path d="M258.4 131h2M34.9 148.5v2M35.6 148.5v2M118.7 159.7h2M118.7 158.9h2M123.1 159.7h2.1M123.1 158.9h2.1M127.6 159.7h2M127.6 158.9h2M191.4 145.1h2M191.4 144.3h2M206.3 153h2"/>
<path d="M206.3 152.3h2M243.5 145.7h2M243.5 145h2M258.4 153.7h2M258.4 152.9h2M25 176.4v2M25.8 176.4v2M191.4 164.8h2M191.4 164h2M206.3 172.7h2M206.3 172h2M243.5 165.4h2"/>
<path d="M243.5 164.6h2M258.4 173.3h2M258.4 172.6h2M55.5 180.2v2M56.3 180.2v2M77.4 180.8v2.1M77.4 193.5v2.1M78.2 180.8v2.1M78.2 193.5v2.1M101.9 180.8v2.1M101.9 193.5v2.1M102.6 180.8v2.1"/>
<path d="M102.6 193.5v2.1M120.9 193.5v2.1M121.7 193.5v2.1"/>
</g>
<g fill="#ffffc2" stroke="#ffffc2" stroke-width=".13">
<path d="M28.6 24.1h1.2v6.3h-1.2z"/>
<path d="M218.4 28.2h1.3v2.5h-1.3z"/>
<path d="M82.2 193.9h1.3v5.1h-1.3z"/>
<path d="M106.7 181.2h1.2v5.1h-1.2z"/>
<path d="M106.7 193.9h1.2v5.1h-1.2z"/>
<path d="M82.2 181.2h1.3v5.1h-1.3z"/>
<path d="M195.6 168.5h8.9v10.2h-8.9z"/>
<path d="M195.6 148.8h8.9v10.2h-8.9z"/>
<path d="M247.6 66.3h8.9v10.1h-8.9z"/>
<path d="M195.6 107.2h8.9v10.2h-8.9z"/>
<path d="M195.6 126.9h8.9v10.2h-8.9z"/>
<path d="M247.6 86h8.9v10.1h-8.9z"/>
<path d="M247.6 149.5h8.9v10.1h-8.9z"/>
<path d="M247.6 169.2h8.9v10.1h-8.9z"/>
<path d="M247.6 107.9h8.9v10.1h-8.9z"/>
<path d="M247.6 127.6h8.9v10.1h-8.9z"/>
<path d="M192.4 187.3h7.6v1.2h-7.6z"/>
<path d="M127 164.1h40v33h-40z"/>
<path d="M180.3 191.4h5.1v7.6h-5.1z"/>
<path d="M70.8 145.3h6.4v7h-6.4z"/>
<path d="M98.4 160h3.8l1.9-2h.7v.7h1.2l.7-.7h6.3v12.1h-14.6z"/>
<path d="M18.1 181.2h1.3v12.7h-1.3z"/>
<path d="M24.1 181.2h2.6v12.7h-2.6z"/>
<path d="M30.5 37.4h119.4v68.6h-119.4z"/>
<path d="M48.3 185h1.2v10.2h-1.2z"/>
<path d="M54.6 185h2.5v10.2h-2.5z"/>
<path d="M27.6 120.6h1.3v5.1h-1.3z"/>
<path d="M195.6 85.3h8.9v10.2h-8.9z"/>
<path d="M267 11h1.3v2.6h-1.3z"/>
<path d="M86.4 11.4h6.3v4.4h-6.3z"/>
<path d="M195.6 65.7h8.9v10.1h-8.9z"/>
<path d="M267 16.8h1.3v2.5h-1.3z"/>
<path d="M255.6 33.9h1.3v2.5h-1.3z"/>
<path d="M255.6 39.6h1.3v2.6h-1.3z"/>
<path d="M47.3 144.1h5.1v7.6h-5.1z"/>
<path d="M39.7 148.8h1.3v5.1h-1.3z"/>
<path d="M255.6 11h1.3v2.6h-1.3z"/>
<path d="M255.6 16.8h1.3v2.5h-1.3z"/>
<path d="M255.6 22.5h1.3v2.5h-1.3z"/>
<path d="M255.6 28.2h1.3v2.5h-1.3z"/>
<path d="M17.1 120.6h1.3v5.1h-1.3z"/>
<path d="M14.3 135.5h10.1v7.6h-10.1z"/>
<path d="M155.9 10.4h1.3v2.5h-1.3z"/>
</g>
<g fill="#840000" stroke="#840000" stroke-width=".13">
<path d="M42.9 25.3l1.2 .7-1.2 .6z"/>
<path d="M63.2 18.3l1.3-.6v1.3z"/>
<path d="M68.6 18.3l.6 1.3h-1.3z"/>
<path d="M76.8 15.2l1.3 .6-1.3 .6z"/>
<path d="M209.2 146.6l1.3-.6v1.3z"/>
<path d="M209.2 166.3l1.3-.6v1.2z"/>
<path d="M261.3 64.1l1.3-.7v1.3z"/>
<path d="M209.2 124.7l1.3-.6v1.2z"/>
<path d="M209.2 105l1.3-.6v1.3z"/>
<path d="M261.3 147.3l1.3-.7v1.3z"/>
<path d="M261.3 166.9l1.3-.6v1.3z"/>
<path d="M261.3 83.8l1.3-.7v1.3z"/>
<path d="M261.3 105.7l1.3-.7v1.3z"/>
<path d="M261.3 125.3l1.3-.6v1.3z"/>
<path d="M193.7 192.3h1.2l-.6 1.3z"/>
<path d="M220.3 9.5l1.9 1.2-1.9 1.3z"/>
<path d="M180.7 192.5h1.4v.3h-1.4z"/>
<path d="M182.6 194.6h.4v.3h-.4z"/>
<path d="M183.2 193.8l.6 .3-.6 .3z"/>
<path d="M233.2 13.3l.5-.2v.4z"/>
<path d="M136.1 13.3l.5-.2v.4z"/>
<path d="M117.7 15.8l.5-.2v.4z"/>
<path d="M232.6 39.3l.5-.2v.4z"/>
<path d="M99.1 169.2h1.2v.6h-1.2z"/>
<path d="M99.1 167.9h1.2v.6h-1.2z"/>
<path d="M99.1 166.6h1.2v.7h-1.2z"/>
<path d="M99.1 165.3h1.2v.7h-1.2z"/>
<path d="M99.1 164.1h1.2v.6h-1.2z"/>
<path d="M99.1 162.8h1.2v.6h-1.2z"/>
<path d="M99.1 161.5h1.2v.7h-1.2z"/>
<path d="M99.1 160.3h1.2v.6h-1.2z"/>
<path d="M54.3 127.2l.2-.3 .3 .5z"/>
<path d="M281.6 12.4l.8-.4a.72 .72 0 0 0 .7-.3l.1-.1a.37 .37 0 0 1 .6-.1 .83 .83 0 0 1 .8 .7v.4a.37 .37 0 0 1 0 .6 2.83 2.83 0 0 0-.6 2.2 .36 .36 0 0 1 0 .6 .58 .58 0 0 0 .3 .9 .59 .59 0 0 1-.1 .8v.2a1.05 1.05 0 0 0-.1 1l-.2 .3 .1 .6a2.33 2.33 0 0 1-.4 2.1l-.2 .8-.2-.5 .1-.6a1.48 1.48 0 0 1 .1-1.3 .97 .97 0 0 1 .1-1v-1.1l-.1-.8a1.19 1.19 0 0 1 0-1v-.1a.98 .98 0 0 1-.3-1.3v-.1a.24 .24 0 0 1-.2-.2 .24 .24 0 0 1 .2-.2l.1-.1v-1a.41 .41 0 0 0-.1-.6l-.4-.2h-.6l-.5-.1z"/>
<path d="M274.2 12.2l1.2-.4a2.15 2.15 0 0 0 1.3-.4 1.21 1.21 0 0 0 .9 .3 .39 .39 0 0 0 .6 0l2.2-.7 .6 .5a.34 .34 0 0 1 .3 .4h.2l-.2 .3a1.51 1.51 0 0 0-.4 1.7l.1 .9 .1 .1-.1 .3a1.79 1.79 0 0 0 .1 1.7 .62 .62 0 0 1-.4 .8l-.3 .8v1.2l-.1 1.5 .1 .6 .1 .2a.73 .73 0 0 1-.2 .7v1.1l-.2 .3-.2 .3v-.4v-.2a.72 .72 0 0 0-.1-.9l-.1-.6v-1.6l-.2-.3 .1-.4-.1-.3a3.7 3.7 0 0 1 .4-2l-.1-.6a3.5 3.5 0 0 1 0-1.7 .54 .54 0 0 1-.2-.6l-.1-.7a.52 .52 0 0 0-.2-.8l.1-.2a.78 .78 0 0 0 0-.7l-.2-.1-.1-.2-.6-.1a.39 .39 0 0 0-.5 .2l-.1 .7-.5 .2 .1 1.1a1.05 1.05 0 0 0-.2 1.2l.5 1.3-.2 .4v.6a.89 .89 0 0 1 0 1.2 3 3 0 0 0-.1 1.7l-.1 1.2v1.1l-.2-.4-.2-1.3a1.82 1.82 0 0 1-.3-1.4 .54 .54 0 0 1 0-.9 1.76 1.76 0 0 0-.1-1.4v-.9l-.3-.7a1.11 1.11 0 0 1-.1-1.4l.1-.5a1.04 1.04 0 0 0-.4-1v-.3a.37 .37 0 0 0-.3-.4z"/>
<path d="M227.3 33.9l1.3-.6v1.2z"/>
<path d="M205.7 48.8l1.3 .7-1.3 .6z"/>
<path d="M209.2 83.1l1.3-.6v1.3z"/>
<path d="M97.2 12l1.2 .6-1.2 .7z"/>
<path d="M196.8 51.4l.7 1.2h-1.3z"/>
<path d="M209.2 63.4l1.3-.6v1.3z"/>
<path d="M55.6 144.7l1.2 .6-1.2 .7z"/>
<path d="M49.6 147.3h.4v.3h-.4z"/>
<path d="M50.2 146.5l.6 .3-.6 .3z"/>
<path d="M47.7 145.1h1.3l-.2 .4h-1z"/>
<path d="M177.8 14.9l1.3-.7v1.3z"/>
<path d="M51.1 118l1.3 .7-1.3 .6z"/>
<path d="M133.7 15.2l1.2 .6-1.2 .6z"/>
<path d="M133.7 10.1l1.2 .6-1.2 .7z"/>
<circle cx="181" cy="194.1" r=".32"/>
<circle cx="182.6" cy="193.5" r=".19"/>
<circle cx="234" cy="12.4" r=".14"/>
<circle cx="234" cy="14.2" r=".14"/>
<circle cx="136.8" cy="12.4" r=".14"/>
<circle cx="136.8" cy="14.2" r=".14"/>
<circle cx="118.4" cy="14.9" r=".14"/>
<circle cx="118.4" cy="16.7" r=".14"/>
<circle cx="233.4" cy="40.2" r=".14"/>
<circle cx="233.4" cy="38.4" r=".14"/>
<circle cx="47.9" cy="146.8" r=".32"/>
<circle cx="49.5" cy="146.2" r=".19"/>
</g>
<g fill="none" stroke="#008484" stroke-width=".13">
<path d="M20.3 13.2l.1-.2v.6M20.3 13.6h.3M23.4 13l.2 .6 .2-.6M108.2 13.1a.28 .28 0 0 0-.4 .2 .28 .28 0 0 0 .4 .3M115.9 13l.1 .6 .1-.4 .2 .4 .1-.6M184.3 8.4a.34 .34 0 0 0-.5 .3 .34 .34 0 0 0 .5 .3M186.6 10.9h.2M186.6 14.7h.2M186.7 10.7v.5l.1 .1M186.7 14.5v.5l.1 .1M189.8 13h.5M191.6 8.4h.3l.2 .2-.5 .5h.5"/>
<path d="M126.6 39.3l.3-.1v-.2l-.3-.1v.7M127.2 39.3h.2M127.5 38.9h-.3v.7h.3M127.8 39l.1-.1a.31 .31 0 0 1 .3 .4 .31 .31 0 0 1-.3 .3l-.1-.3zM223.9 23.6l.3 .8 .2-.8M232.1 23.8l.3-.2v.8M232.1 24.4h.5M41.3 44v.5l.1 .2 .2-.2v-.5M41.8 44h.4M42 44v.7M42.7 51.6h.4M42.9 51.6v.7"/>
<path d="M121.3 46.9h.3v-.3h-.3v.6M121.9 46.9h.2M122.3 46.6h-.4v.6h.4M122.3 45.6h.3v-.2l-.3-.1v.6M122.8 46.6l-.3 .1v.4l.1 .1 .2-.1v-.2l-.1-.1-.2 .1M122.9 45.6h.2M123.2 45.3h-.3v.6h.3M123.6 46.5l-.6 .9M123.8 45.3h-.3v.3h.3v.3h-.3M124.5 45.3l-.5 .8M124.6 41.8h.3v-.3h-.3v.6M125.2 41.8h.2"/>
<path d="M125.5 41.5h-.3v.6h.3M125.8 41.5h.2l.1 .2-.4 .4h.4M127.4 44.4l.3-.1 .1-.2-.4-.1v.7M128.1 44.3h.2M128.4 44h-.3v.7h.3M128.8 44l-.2 .4h.4M128.9 44.2v.5M130.7 58.3h.3v-.2l-.3-.1v.6M131 52l.3-.1v-.2l-.3-.1v.7M131 54.5h.3v-.3h-.3v.6M131 55.8l.4-.1v-.2h-.4v.6M131 57.1l.4-.1v-.2l-.4-.1v.7"/>
<path d="M131.3 58.3h.3M131.6 40.5h.3v-.2l-.3-.1v.7M131.6 49.4h.3v-.2l-.3-.1v.6M131.6 52h.2M131.6 54.5h.2M131.6 53.2h.4v-.2l-.4-.1v.7M131.6 58h-.3v.6h.3M131.7 55.8h.2M131.7 57h.2M131.9 58.2l.2-.2v.6M131.9 58.6h.4M131.9 51.6h-.3v.7h.3"/>
<path d="M131.9 54.2h-.3v.6h.3M132 55.5h-.3v.6h.3M132 56.7h-.3v.7h.3M132.1 43.1h.3l.1-.3h-.4v.6M132.2 51.8l.1-.2v.7M132.2 54.4l.1-.2v.6M132.2 52.3h.3M132.2 54.8h.3M132.2 40.5h.2M132.2 55.6l.2-.1v.6M132.2 56.9l.2-.2v.7M132.2 49.4h.2"/>
<path d="M132.2 56.1h.4M132.2 57.4h.4M132.3 50.7h.3v-.3h-.3v.6M132.3 53.2h.2M132.5 48.2l.3-.1v-.2l-.3-.1v.7M132.5 40.2h-.3v.7h.3M132.5 49.1h-.3v.6h.3M132.6 52.9h-.3v.7h.3M132.8 43.1h.2M132.8 53.1l.2-.2v.7M132.8 53.6h.4M132.9 49.4l-.1-.2 .2-.1 .1 .1v.1l-.3 .2 .1 .2 .2-.1-.1-.2"/>
<path d="M132.9 50.7h.2M133.1 42.8h-.3v.6h.3M133.1 48.1h.2M133.2 50.4h-.3v.6h.3M133.4 47.8h-.3v.7h.3M133.8 50.7l-.1 .1-.2-.1v-.3h.2l.1 .1v.4l-.1 .1h-.2M44.3 78.3v.5l.1 .2 .3-.2v-.5M44.4 79.6v.5l.1 .1 .3-.1v-.5M44.9 78.3h.3M45 79.6h.4M45 78.3v.7M45.2 79.6v.6"/>
<path d="M57.3 73.2h.4M57.5 73.2v.7M57.8 74.5h.3M57.9 73.3l.1-.1 .3 .1v.4l-.1 .1h-.3zM58 74.5v.6M58.4 74.6l.1-.1 .2 .1 .1 .3-.1 .2h-.3zM58.6 73.2v.6l.1 .1 .2-.1v-.6M59 77.1l.1-.1 .2 .1v.5l-.1 .1-.2-.1zM59 74.5v.5l.1 .1 .3-.1v-.5M59.1 73.2h.4M59.3 73.2v.7M59.3 75.8h.4"/>
<path d="M59.5 75.8v.6M59.6 74.5h.4M59.6 77v.6l.1 .1 .3-.1v-.6M59.8 74.5v.6M59.9 75.9l.1-.1 .3 .1v.3l-.1 .2-.3-.1zM60.2 77h.4M60.4 77v.7M60.6 75.8v.5l.1 .1 .2-.1v-.5M61.1 75.8h.4M61.3 75.8v.6M61.5 72v.6l-.3-.6v.6M61.7 72h.4"/>
<path d="M61.9 72v.6M62.2 64.3v.7l-.4-.7v.7M62.3 68.2v.6l-.4-.6v.6M62.3 72.1l.1-.1 .3 .1v.3l-.1 .2-.3-.1zM62.4 64.3h.3M62.5 68.2h.4M62.6 64.3v.7M62.7 68.2v.6M63 64.4l.1-.1 .2 .1v.4v.2l-.3-.1zM63 72v.5l.1 .1 .2-.1v-.5M63.1 68.2h.1h.2l.1 .4-.1 .2-.3-.1zM63.6 72h.3"/>
<path d="M63.6 64.3v.6l.1 .1 .3-.1v-.6M63.7 68.2v.5l.2 .1 .2-.1v-.5M63.7 72v.6M64.2 64.3h.4M64.3 68.2h.4M64.4 64.3v.7M64.5 68.2v.6M68.4 69.4l.2 .7 .2-.7M68.7 67.2h.2M69 66.9h-.3v.6h.3M69.1 69.7h.2M69.4 69.4h-.3v.7h.3"/>
<path d="M69.6 66.9v.6l-.3-.6v.6M69.8 66.9h.4M70 69.4v.7l-.4-.7v.7M70 66.9v.6M70.2 69.4h.4M70.4 69.4v.7M70.4 67l.1-.1 .3 .1v.3l-.1 .2-.3-.1zM70.8 69.5l.1-.1 .2 .1 .1 .3-.1 .2h-.3zM71.1 66.9v.5l.1 .1 .3-.1v-.5M71.2 65.9h.2M71.5 69.4v.5l.1 .2 .2-.2v-.5M71.5 65.6h-.3v.7h.3"/>
<path d="M71.7 66.9h.3M71.8 66.9v.6M72 69.4h.4M72.1 65.6v.7l-.3-.7v.7M72.2 69.4v.7M72.4 65.6h.3M72.5 65.6v.7M72.9 65.7l.2-.1 .2 .1v.3l-.1 .2h-.3zM73.6 65.6v.5l.1 .2 .3-.2v-.5M74.2 62.1h.2M74.2 65.6h.3M74.3 65.6v.7"/>
<path d="M74.5 61.8h-.3v.6h.3M75.1 63.4h.2M75.1 61.8v.6l-.4-.6v.6M75.3 61.8h.4M75.4 63.1h-.3v.6h.3M75.5 61.8v.6M75.9 61.9l.1-.1 .3 .1v.3l-.1 .2h-.3zM76 63.1v.6l-.3-.6v.6M76.1 71h.2M76.2 63.1h.4M76.4 70.7h-.3v.6h.3M76.4 63.1v.6"/>
<path d="M76.6 61.8v.5l.1 .1 .2-.1v-.5M76.6 70.7l.2 .6 .2-.6M76.8 63.2l.1-.1 .3 .1v.3l-.1 .2-.3-.1zM77.1 61.8h.4M77.2 71h.2M77.3 61.8v.6M77.5 63.1v.5l.1 .1 .2-.1v-.5M77.5 70.7h-.3v.6h.3M78 63.1h.4M78.1 70.7v.6l-.3-.6v.6M78.2 63.1v.6M78.3 70.7h.4"/>
<path d="M78.5 70.7v.6M78.9 70.8l.1-.1 .3 .1v.3l-.1 .2-.3-.1zM79.6 70.7v.5l.1 .1 .2-.1v-.5M80.2 70.7h.3M80.3 70.7v.6M119.4 77.4l.3-.1v-.2l-.3-.1v.7M120 77a.32 .32 0 0 1 .4 .4 .32 .32 0 0 1-.4 .3zM120.6 77.2l.2-.2v.7M120.6 77.7h.4M121.2 77.1l.3-.1 .1 .2-.4 .5h.4M121.3 64.7h.3l.1-.3-.4-.1v.7M122 64.3a.32 .32 0 0 1 .3 .4 .32 .32 0 0 1-.3 .3z"/>
<path d="M122.6 64.4l.2-.1 .1 .2-.4 .5h.4M123.7 64.3l-.6 .8M124.4 76.1h.4v-.3h-.4v.6M124.7 71h.3v-.2l-.3-.1v.6M125.1 75.8a.32 .32 0 0 1 .4 .3 .32 .32 0 0 1-.4 .3zM125.3 70.7a.32 .32 0 0 1 .4 .3 .32 .32 0 0 1-.4 .3zM125.7 76l.2-.2v.6M125.7 76.4h.4M125.8 79.9h.3v-.3h-.3v.6M125.9 70.7h.4l-.3 .6M126.4 79.6a.32 .32 0 0 1 .4 .3 .32 .32 0 0 1-.4 .3zM127 79.8l.2-.2v.6"/>
<path d="M130 69.8l.3-.1v-.2l-.3-.1v.7M130.2 74.8h.3v-.2l-.3-.1v.6M130.3 67.2h.3v-.3h-.3v.6M130.4 65.9h.3v-.2l-.3-.1v.7M130.6 69.4a.32 .32 0 0 1 .4 .3 .32 .32 0 0 1-.4 .4zM130.8 73.6l.3-.1 .1-.2-.4-.1v.7M130.8 74.5a.32 .32 0 0 1 .4 .3 .32 .32 0 0 1-.4 .3zM130.9 68.5h.3v-.3h-.3v.6M130.9 66.9a.32 .32 0 0 1 .4 .3 .32 .32 0 0 1-.4 .3zM131 72.3l.3-.1v-.2h-.3v.6M131 65.6a.32 .32 0 0 1 .4 .3 .32 .32 0 0 1-.4 .4zM131.1 78.6h.3v-.2l-.3-.1v.7"/>
<path d="M131.5 73.2a.32 .32 0 0 1 .3 .4 .32 .32 0 0 1-.3 .3zM131.5 68.2a.32 .32 0 0 1 .4 .3 .32 .32 0 0 1-.4 .3zM131.6 72a.32 .32 0 0 1 .4 .3 .32 .32 0 0 1-.4 .3zM131.7 78.3a.32 .32 0 0 1 .4 .3 .32 .32 0 0 1-.4 .4zM132.3 78.5l.2-.2v.7M132.3 79h.4M132.5 62.1h.3l.1-.2-.4-.1v.6M132.7 63.4h.3v-.3h-.3v.6M133.2 61.8a.32 .32 0 0 1 .3 .3 .32 .32 0 0 1-.3 .3zM133.3 63.1a.32 .32 0 0 1 .4 .3 .32 .32 0 0 1-.4 .3zM40.9 87.2v.5l.2 .1 .2-.1v-.5M41.5 87.2h.4"/>
<path d="M41.7 87.2v.6M60.2 81.2h.2M60.5 80.9h-.3v.6h.3M61.1 80.9v.6l-.3-.6v.6M61.1 92.3v.6l-.3-.6v.6M61.1 90.1h.3M61.4 80.9h.3M61.4 92.3h.3M61.4 89.7h-.3v.7h.3M61.5 80.9v.6M61.5 92.3v.6M61.9 80.9h.1h.3v.4l-.1 .2-.3-.1z"/>
<path d="M61.9 92.4l.1-.1 .3 .1v.3l-.1 .2-.3-.1zM62.1 89.7v.7l-.4-.7v.7M62.3 89.7h.3M62.5 89.7v.7M62.6 80.9v.5l.1 .1 .3-.1v-.5M62.6 92.3v.5l.1 .1 .3-.1v-.5M62.9 89.8l.1-.1 .2 .1 .1 .4-.2 .2-.2-.1zM63.2 80.9h.3M63.2 92.3h.3M63.2 93.6v.6l-.3-.6v.6M63.3 80.9v.6M63.3 92.3v.6"/>
<path d="M63.3 88.8h.3M63.4 93.6h.4M63.5 89.7v.6l.2 .1 .2-.1v-.6M63.6 93.6v.6M63.7 88.5h-.4v.6h.4M64 93.6h.1h.3v.4l-.1 .2-.3-.1zM64.1 89.7h.4M64.3 88.5v.6l-.4-.6v.6M64.3 89.7v.7M64.5 88.5h.4M64.7 93.6v.5l.1 .1 .2-.1v-.5M64.7 88.5v.6"/>
<path d="M65.1 88.6l.1-.1 .2 .1 .1 .3-.1 .2-.3-.1zM65.3 93.6h.3M65.4 93.6v.6M65.7 88.5v.5l.1 .1 .3-.1v-.5M66.3 88.5h.4M66.5 88.5v.6M67.4 85h.2M67.7 84.7h-.3v.6h.3M68.3 84.7v.6l-.4-.6v.6M68.5 84.7h.4M68.7 84.7v.6M69.1 84.8l.1-.1 .3 .1v.3l-.1 .2-.3-.1z"/>
<path d="M69.8 84.7v.5l.1 .1 .2-.1v-.5M70.3 84.7h.4M70.5 84.7v.6M70.8 95.1h.3M71.1 94.8h-.3v.7h.3M71.3 94.8l.2 .7 .3-.7M72 95.1h.2M72.3 94.8h-.3v.7h.3M72.9 94.8v.7l-.4-.7v.7M73.1 94.8h.4M73.3 96.1l-.6 .8M73.3 94.8v.7"/>
<path d="M73.5 96.4h.2M73.5 85.9l.2 .7 .3-.7M73.7 94.9l.1-.1 .3 .1v.3l-.1 .2h-.3zM73.8 96.1h-.3v.6h.3M74 96.1l.2 .6 .2-.6M74.2 86.2h.2M74.3 94.8v.5l.2 .2 .2-.2v-.5M74.5 85.9h-.3v.7h.3M74.6 96.4h.2M74.9 96.1h-.3v.6h.3M74.9 94.8h.4M75.1 85.9v.7l-.4-.7v.7"/>
<path d="M75.1 94.8v.7M75.3 85.9h.4M75.5 85.9v.7M75.5 96.1v.6l-.3-.6v.6M75.7 96.1h.4M75.8 98.9h.2M75.9 86l.1-.1 .3 .1v.4l-.1 .1h-.3zM75.9 96.1v.6M76.1 98.6h-.3v.7h.3M76.2 97.7h.2M76.3 96.2l.1-.1 .3 .1v.3l-.1 .2-.3-.1zM76.5 97.4h-.3v.6h.3"/>
<path d="M76.6 85.9v.6l.1 .1 .2-.1v-.6M76.6 97.4l.3 .6 .2-.6M76.7 98.6v.7l-.3-.7v.7M76.9 98.6h.4M77 96.1v.5l.1 .1 .2-.1v-.5M77.1 98.6v.7M77.1 85.9h.4M77.3 97.7h.2M77.3 85.9v.7M77.5 98.7l.1-.1 .3 .1v.4l-.1 .1h-.3zM77.6 96.1h.3M77.6 97.4h-.3v.6h.3"/>
<path d="M77.7 96.1v.6M78.2 98.6v.6l.1 .1 .2-.1v-.6M78.2 97.4v.6l-.3-.6v.6M78.4 97.4h.4M78.6 97.4v.6M78.7 98.6h.4M78.9 98.6v.7M79 97.5l.1-.1 .3 .1v.3l-.1 .2-.3-.1zM79.7 97.4v.5l.1 .1 .2-.1v-.5M80.3 97.4h.3M80.4 97.4v.6M84.8 91a.32 .32 0 0 1 .3 .3 .32 .32 0 0 1-.3 .4z"/>
<path d="M85.9 91l-.6 .8M86.1 91.3h.2M86.4 91h-.3v.7h.3M86.6 91l.2 .7 .2-.7M87.2 91.3h.2M87.5 91h-.3v.7h.3M88.1 91v.7l-.3-.7v.7M88.4 91h.3M88.5 91v.7M88.9 91.1l.2-.1 .2 .1v.3l-.1 .2h-.3zM89.6 91v.5l.1 .2 .3-.2v-.5M90.2 91h.3"/>
<path d="M90.3 91v.7M93.7 99.9a.32 .32 0 0 1 .4 .3 .32 .32 0 0 1-.4 .3zM94.8 99.9l-.6 .8M95.3 99.9h-.3v.6h.3M95.5 99.9l.2 .6 .2-.6M96.4 99.9h-.3v.6h.3M97.1 99.9v.6l-.4-.6v.6M97.3 99.9h.3M97.4 99.9v.6M97.8 100l.2-.1 .2 .1v.3l-.1 .2h-.3zM98.5 99.9v.5l.1 .1 .3-.1v-.5M99.1 99.9h.4"/>
<path d="M99.3 99.9v.6M109.4 96.4h.3v-.2l-.3-.1v.6M109.6 99l.3-.1v-.2l-.3-.1v.7M110.4 96.2a.28 .28 0 0 0-.4 .2 .28 .28 0 0 0 .4 .3M110.6 98.7a.28 .28 0 0 0-.4 .3 .28 .28 0 0 0 .4 .2M110.8 98.8l.2-.2v.7M110.8 99.3h.4M111 96.4l-.2 .1h-.1l-.1-.3 .2-.1 .2 .1-.1 .4-.1 .1h-.1M111.5 93.9l.3-.1v-.2h-.3v.6M111.5 98.8l.1-.2v.7M111.5 99.3h.3M111.6 92.6h.3v-.3h-.3v.6"/>
<path d="M111.7 96.1l-.5 .8M111.7 97.7h.3l.1-.3h-.4v.6M111.9 96.1v.6M112.1 100a.28 .28 0 0 0-.4 .2 .28 .28 0 0 0 .4 .3M112.2 96.2l.2-.1 .1 .2-.4 .4h.4M112.4 93.6a.28 .28 0 0 0-.4 .3 .28 .28 0 0 0 .4 .2M112.5 98.6l-.5 .8M112.6 92.3a.28 .28 0 0 0-.4 .3 .28 .28 0 0 0 .4 .3M112.7 93.6h.4l-.3 .6M112.7 97.4a.28 .28 0 0 0-.4 .3 .28 .28 0 0 0 .4 .2M112.8 98.6v.6l.1 .1 .2-.1v-.6M113 97.5l.1-.1v.6"/>
<path d="M113 100l.2-.1 .1 .2-.4 .4h.4M113 98h.3M113.1 92.3h-.2l-.1 .3 .1 .3h.2v-.3l-.1-.1-.2 .2M113.1 96.1h-.3v.2a.25 .25 0 0 1 .3 .1 .25 .25 0 0 1 0 .3h-.3M113.3 96.8h.5M113.6 97.4h.1a.31 .31 0 0 1 .2 .3 .31 .31 0 0 1-.2 .3l-.1-.2zM113.8 93.5l-.6 .8M113.9 92.3l-.5 .8M114 93.6v.6M114 99.9l-.5 .8M114.1 92.3v.6M114.3 93.6h.2l.1 .1-.4 .5h.4"/>
<path d="M114.3 99.9v.5l.1 .1 .2-.1v-.5M114.4 92.3h.3l.1 .2-.4 .4h.4M114.7 97.3l-.6 .9M114.9 87.5h.3v-.2l-.3-.1v.6M115.1 88.8h.3v-.3h-.3v.6M115.2 97.4h-.3v.2a.25 .25 0 0 1 .2 .1 .25 .25 0 0 1 0 .3h-.3M115.2 93.6h-.3v.2a.25 .25 0 0 1 .2 .1 .25 .25 0 0 1 .1 .3h-.3M115.4 92.3h-.3l-.1 .2a.25 .25 0 0 1 .3 .1 .25 .25 0 0 1 0 .3h-.3M115.9 87.3a.28 .28 0 0 0-.4 .2 .28 .28 0 0 0 .4 .3M116.1 88.5a.28 .28 0 0 0-.4 .3 .28 .28 0 0 0 .4 .2M116.1 87.3l.2-.1 .2 .2-.4 .4h.4M116.3 88.5h.4l-.2 .2 .1 .1v.3l-.3-.1"/>
<path d="M116.7 95.2l.3-.1v-.2l-.3-.1v.7M117.2 87.2l-.6 .8M117.4 88.4l-.5 .9M117.7 94.9a.28 .28 0 0 0-.4 .2 .28 .28 0 0 0 .4 .3M117.7 87.2h-.3v.2a.25 .25 0 0 1 .3 .1 .25 .25 0 0 1 0 .3h-.3M118 95.1l-.1-.1v-.1l.3-.1 .1 .2h-.1l-.3 .2 .1 .3 .3-.2-.1-.2M119 94.8l-.5 .8M119.1 94.8h.4M119.3 94.8v.7M126.3 90.1h.3l.1-.3-.4-.1v.7M126.3 91.3h.3l.1-.2-.4-.1v.7M127 80.2h.4"/>
<path d="M127.3 89.8a.28 .28 0 0 0-.4 .3 .28 .28 0 0 0 .4 .2M127.3 91.1a.28 .28 0 0 0-.4 .2 .28 .28 0 0 0 .4 .3M131.6 81.2h.3v-.3h-.3v.6M132.2 80.9a.32 .32 0 0 1 .4 .3 .32 .32 0 0 1-.4 .3zM132.8 81l.2-.1v.6M132.8 81.5h.4M133.2 85h.4v-.3h-.4v.6M136.9 86.3l.3-.1v-.2l-.3-.1v.7M68.3 103.7l.2 .7 .2-.7M68.9 104h.3M69.2 103.7h-.3v.7h.3M69.9 103.7v.7l-.4-.7v.7"/>
<path d="M70.1 103.7h.3M70.3 103.7v.7M70.7 103.8l.1-.1 .2 .1 .1 .3-.1 .2h-.3zM71.3 103.7v.5l.2 .2 .2-.2v-.5M71.9 103.7h.4M72.1 103.7v.7M75.5 102.4l-.5 .8M75.7 102.8h.3M76 102.4h-.3v.7h.3M76.2 102.4l.2 .7 .2-.7M76.9 102.8h.2M77.2 102.4h-.3v.7h.3"/>
<path d="M77.8 102.4v.7l-.4-.7v.7M78 102.4h.4M78.2 102.4v.7M78.6 102.5l.1-.1 .2 .1 .1 .4-.1 .2-.3-.1zM79.2 102.4v.6l.2 .1 .2-.1v-.6M79.8 102.4h.4M80 102.4v.7M83.9 101.1l-.5 .9M84.2 101.5h.2M84.5 101.2h-.3v.6h.3M84.6 101.2l.2 .6 .3-.6M85.3 101.5h.2"/>
<path d="M85.6 101.2h-.3v.6h.3M86.2 101.2v.6l-.4-.6v.6M86.4 101.2h.4M86.6 101.2v.6M87 101.3l.1-.1 .3 .1v.3l-.2 .2-.2-.1zM87.7 101.2v.5l.1 .1 .2-.1v-.5M88.2 101.2h.4M88.4 101.2v.6M95 100.2h.2M96.1 100.2h.2M111.1 100.2h.4v-.2l-.4-.1v.6M112.4 100.1l.1-.2v.6"/>
<path d="M112.4 100.5h.3M135.6 104h.3v-.2l-.3-.1v.7M136.4 102.8h.3l.1-.3-.4-.1v.7M136.6 103.8a.28 .28 0 0 0-.4 .2 .28 .28 0 0 0 .4 .3M137.4 102.5a.28 .28 0 0 0-.4 .3 .28 .28 0 0 0 .4 .2M141.7 101.5h.3v-.3h-.3v.6M86.6 128.8h.4M48.2 148.4h.7M48.5 148.4l-.1 .1 .2 .2 .2-.1v-.2M50.6 148.8a.32 .32 0 0 1 .3 .3 .32 .32 0 0 1-.3 .3zM51.2 149.2h.5M75.3 147.5a.32 .32 0 0 1 .4 .3 .32 .32 0 0 1-.4 .4z"/>
<path d="M76 147.9h.5M142.3 159h.4v-.3h-.4v.7M151.5 158.6l-.2 .6h.5M151.6 158.9v.5M97.6 161.5a.32 .32 0 0 1 .4 .3 .32 .32 0 0 1-.4 .3zM140.4 174.1l.1-.2v.6M140.4 173.2h.3M140.4 174.5h.3M141 174.1l.1-.2v.6M141 174.5h.3M141 172.7l.1-.1a.31 .31 0 0 1 .2 .3 .31 .31 0 0 1-.2 .3l-.1-.2zM141.9 176.5l.2-.1 .1 .2-.4 .5h.4"/>
<path d="M144.3 166.6h.4v-.3h-.4v.6M144.8 165.3h.3l.1-.2-.4-.1v.6M144.9 177.7h.4l-.2 .2 .2 .1v.3h-.4M145.3 166.3a.28 .28 0 0 0-.3 .3 .28 .28 0 0 0 .4 .2v-.2h-.2M145.8 165a.28 .28 0 0 0-.4 .3 .28 .28 0 0 0 .4 .3v-.2h-.1M148.9 179.6l.3-.6 .2 .6M149 179.4h.3M149.9 179v.6l-.3-.6v.6M150.2 175.5l.4-.1v-.2h-.4v.6M150.8 174.2h.3v-.3h-.3v.6M156.8 178h.4v-.2l-.4-.1v.6M157 178l.2 .3"/>
<path d="M158.8 176.5a.28 .28 0 0 0-.4 .2 .28 .28 0 0 0 .4 .3M133.7 194.6h.3l-.1-.2h-.1l-.1 .1v.3h.2M137.2 181.8l-.1-.2 .3-.1 .1 .1v.1l-.4 .2 .1 .2 .3-.1-.1-.2M137.5 180.5l-.1 .1h-.2v-.3l.2-.1 .1 .2v.3l-.1 .1-.2 .1M137.7 185.3h.4l-.3 .3h.2v.3h-.3M139.9 187.8l-.2 .5h.4M140 188.1v.4M140.7 184.1l.3-.1 .1 .2-.4 .5h.4M144.1 189.1l-.2 .4h.4M144.2 189.3v.5M144.6 180.9l.2-.7 .2 .7M144.7 180.7h.3"/>
<path d="M145.6 180.2v.7l-.4-.7v.7M147.7 182.1l.2-.6 .2 .6M147.7 182h.3M155.8 188.5l.2-.6 .2 .6M155.8 188.3h.3M156.4 187.2l.2-.6 .2 .6M156.4 187h.3M157 184.7l.2-.7 .2 .7M157 185.9l.2-.6 .2 .6M157 184.5h.4M157 185.8h.4M158.8 192h.3v-.3h-.3v.6"/>
<path d="M158.8 193.3l.3-.1v-.2l-.3-.1v.7M158.8 189.5l.3-.1v-.2l-.3-.1v.7M158.8 190.7h.3v-.2l-.3-.1v.6M158.8 194.5h.3v-.2l-.3-.1v.6M158.8 195.8h.3v-.3h-.3v.6M158.9 192l.2 .3M158.9 193.3l.2 .3M158.9 189.5l.2 .3M158.9 190.7l.2 .3M158.9 194.5l.2 .3M158.9 195.8l.2 .3M181.3 195.7h.6v.2h-.4v-.2"/>
<path d="M183.6 196.1a.32 .32 0 0 1 .4 .3 .32 .32 0 0 1-.4 .3zM184.2 196.5h.5M195.1 192.3a.28 .28 0 0 0-.3 .3 .28 .28 0 0 0 .4 .3v-.2h-.1M200.4 193.2h-.2l-.1 .1 .1 .3h.2M200.4 193v.6"/>
</g>
<path d="M77.7 113.7h.4l.1-.3-.5-.1v.8M78.5 113.6h.3v.5M78.8 113.8l-.3 .1 .1 .2h.2M100.9 113.6h.3v.5M101.2 113.7l.1-.1h.2l.1 .5M101.9 113.6h.3v.5M101.9 113.6v.5M102.2 113.7l.2-.1h.1l.1 .5" fill="none" stroke="#840084" stroke-width=".13"/>
<path d="M12.8 37.7h1.1v2.6h-1.1z" fill="none" stroke="#840000" stroke-width=".15"/>
<g fill="none" stroke="#008400" stroke-width=".13">
<path d="M23.8 11v13.4M33.7 11v4.5M37.8 14.5h4.7M37.8 10.7h4.7M53 10.7h-3.2v5.1M56.8 10.7h3.2v5.1h8.6v.6M61.3 18.3h-1.3v2.6M74.9 12.6v4.5M80 10.7v5.1M83.8 17.4v.9h11.4v-.9M83.8 12.6v1M95.2 12.6v1"/>
<path d="M107 17.1h2.5M108.3 14.5h1.2M118.4 18.3h5.4M118.4 10.7v2.6M133 13.3h-1.2v2.5M136.8 15.8h1.6M151.4 12.3h2.6M153.4 11h.6M171.8 14.9h4.1M181 11h-12.4v7.7h12.4M194.9 14.9h1.3M194.9 11v1.9h5.8v5.8h-5.1"/>
<path d="M205.7 10.1h-1.9v10.2h1.9M207 10.1h2.5v10.2M217.8 10.7h1M228.9 13.3h1.3M229.6 13.3v2.5M234 15.8v2.5h-1.6M234 10.7h-10.2v3.8M248.6 10.4h2.5v1.3h2.6M248.6 16.1h2.5v1.3h2.6M253.7 12.9h-2.6v1.3h-2.5M253.7 18.7h-2.6v1.2h-2.5M263.2 11.7v1.2h1.9"/>
<path d="M263.2 17.4v1.3h1.9M10.8 39h.6M15.2 39h.7M31.7 28.5h7M31.7 26h1.6M31.7 24.7h1M31.7 29.8h7M31.7 27.2h7M61.6 33.6h44.4M68.6 21.5v.7M74.9 20.9v1.3h-13.6M110.5 30.1h35.5"/>
<path d="M110.5 26.3h35.5M197.8 25.3v13.4M207 20.3h4.5M208.3 25.3v4.5M221.6 30.1h1.6v7.9h.6M223.2 25.3v1M223.2 33.9h2.2M228.9 39.3h.7M230.5 33.9h8.6M233.4 30.1v6.7M248.6 39h2.5v1.3h2.6M248.6 21.8h2.5v1.3h2.6"/>
<path d="M248.6 27.6h2.5v1.2h2.6M248.6 33.3h2.5v1.2h2.6M253.7 30.1h-2.6v1.3h-2.5M253.7 35.8h-2.6v1.3h-2.5M253.7 24.4h-2.6v1.2h-2.5M9.8 50.1h1v3.8h.6M11.1 42.8h4.5M15.9 50.1v3.8h-.7M168.3 52h7.6M171.8 55.8h4.4M179.1 44.1h-3.2v5.4M182.9 44.1h3.2v5.4h10.7"/>
<path d="M192.4 50.7h-6.3v1.3M203.2 49.5h.6M203.5 46.3v3.8M203.5 53.9v.6M208.9 53.3v1.2M214 53.3v1.2M219.1 53.3v1.2h-31.8M233.4 41.8v1.3M239.1 41.5v1.6h-9.9M251.1 51h15.9M252.1 54.9h14.9M253.7 41.5h-2.6v1.3h-2.5"/>
<path d="M186.4 72h7.9M194.3 66.9h-7.9v1.3M194.3 74.5v1.3M205.7 74.5h2.9M205.7 72h1.6v.6h8.6v1.3M205.7 69.5h2.9M205.7 66.9h1.6M207.3 63.4v4.2M215.9 71.4h-.6v3.1h-2.9M215.9 68.8h-.6v.7h-2.9M229.9 66.3v5.1M229.9 72.6v2.6"/>
<path d="M238.4 72.6h8M246.4 75.2v1.2M246.4 67.6h-8v1.2M257.8 72.6h1.6v.7h8.6v1.2M257.8 75.2h2.9M257.8 70.1h2.9M257.8 67.6h1.6M259.4 64.1v4.1M268 69.5h-.7v.6h-2.8M268 72h-.7v3.2h-2.8M281.9 66.9v5.1M281.9 73.3v2.5"/>
<path d="M186.1 91.7h8.2M194.3 94.2v1.3M194.3 86.6h-8.2v1.3M205.7 91.7h1.6v.6h8.6v1.3M205.7 94.2h2.9M205.7 89.1h2.9M205.7 86.6h1.6M207.3 83.1v4.1M215.9 88.5h-.6v.6h-2.9M215.9 91.1h-.6v3.1h-2.9M229.9 86v5.1M229.9 92.3v2.6"/>
<path d="M238.1 92.3h8.3M246.4 94.9v1.2M246.4 87.2h-8.3v1.3M257.8 92.3h1.6v.7h8.6v1.2M257.8 87.2h1.6M257.8 89.8h2.9M257.8 94.9h2.9M259.4 83.8v4.1M268 89.1h-.7v.7h-2.8M268 91.7h-.7v3.2h-2.8M281.9 86.6v5.1M281.9 93v2.5"/>
<path d="M10.8 119v3.5h4.4M21.3 119v3.5h4.4M49.2 118.7v1.2h5.7M54.3 118.7h.6M85.1 109.8v3.8h22.8M87.6 109.8v3.8M90.2 109.8v3.8M92.7 109.8v3.8M95.2 109.8v3.8M131.4 119.9v.7M136.5 119.9v.7M142.2 119.9v.7"/>
<path d="M148 119.9v.7M186.4 113.6h7.9M194.3 116.1v1.3M194.3 108.5h-7.9v1.3M205.7 113.6h1.6v.6h8.6v1.3M205.7 111.1h2.9M205.7 108.5h1.6M205.7 116.1h2.9M207.3 105v4.2M215.9 110.4h-.6v.7h-2.9M215.9 113h-.6v3.1h-2.9M229.9 107.9v5.1"/>
<path d="M229.9 114.2v2.6M238.4 114.2h8M246.4 116.8v1.2M246.4 109.2h-8v1.2M257.8 114.2h1.6v.7h8.6v1.2M257.8 111.7h2.9M257.8 116.8h2.9M257.8 109.2h1.6M259.4 105.7v4.1M268 113.6h-.7v3.2h-2.8M268 111.1h-.7v.6h-2.8M281.9 108.5v5.1"/>
<path d="M281.9 114.9v2.5M14 125h1.2M14.6 121.2h.6M24.4 125h1.3M25.1 121.2h.6M69.8 126.6h11.8M69.8 127.9h11.8M73.7 120.3v3.8M76.5 120.3v8.9h5.1M76.5 124.1h5.1M77.2 124.1v1.2M77.8 120.3h-7.3v2.5"/>
<path d="M77.8 121.5v1.3h3.8M81 125.3h.6M119.1 121.5v2.6M131.4 120.3h.4M136.5 120.3h.3M142.2 120.3h.4M148 120.3h.3M186.1 133.3h8.2M194.3 135.8v1.3M194.3 128.2h-8.2v1.3M205.7 133.3h1.6v.6h8.6v1.3M205.7 130.7h2.9"/>
<path d="M205.7 135.8h2.9M205.7 128.2h1.6M207.3 124.7v4.1M215.9 130.1h-.6v.6h-2.9M215.9 132.6h-.6v3.2h-2.9M229.9 127.6v5M229.9 133.9v2.6M238.1 133.9h8.3M246.4 136.5v1.2M246.4 128.8h-8.3v1.3M257.8 133.9h1.6v.7h8.6v1.2M257.8 128.8h1.6"/>
<path d="M257.8 136.5h2.9M257.8 131.4h2.9M259.4 125.3v4.2M268 130.7h-.7v.7h-2.8M268 133.3h-.7v3.2h-2.8M281.9 128.2v5.1M281.9 134.6v2.5M13 140.6v3.8h6.4M33.3 149.5v1.2h4.5M36.2 153.3h1.6M36.2 152h1.6M37.1 149.5h.7"/>
<path d="M60.6 148.8h3.9M68.3 146h-7.7v5.7M79.7 148.8h4.1M79.7 146h2.2M94 149.2h.9M109.9 149.2h.9M119.7 157.4h8.9M125.7 149.2h1M141.6 149.2h1M186.4 155.2h7.9M194.3 157.7v1.3M194.3 150.1h-7.9v1.3"/>
<path d="M205.7 155.2h1.6v.6h8.6v1.3M205.7 150.1h1.6M205.7 152.6h2.9M205.7 157.7h2.9M207.3 146.6v4.1M215.9 152h-.6v.6h-2.9M215.9 154.6h-.6v3.1h-2.9M229.9 149.5v5.1M229.9 155.8v2.6M238.4 155.8h8M246.4 158.4v1.2M246.4 150.7h-8v1.3"/>
<path d="M257.8 153.3h2.9M257.8 155.8h1.6v.7h8.6v1.2M257.8 150.7h1.6M257.8 158.4h2.9M259.4 147.3v4.1M268 152.6h-.7v.7h-2.8M268 155.2h-.7v3.2h-2.8M281.9 150.1v5.1M281.9 156.5v2.5M23.5 177.4h-1.3v15.9M27.3 177.4h1.3v15.9M52.7 180v14.6"/>
<path d="M79.1 172h12.3M91.4 170.7h-.9v2.9M118.7 165.3v2.6h4.5M119.7 161.2h8.9M122.6 165.3h.6M122.9 164.4v.9M134.6 160.3h2.6M186.1 174.9h8.2M194.3 177.4v1.3M194.3 169.8h-8.2v1.3M205.7 174.9h1.6v.6h8.6v1.3M205.7 177.4h2.9"/>
<path d="M205.7 172.3h2.9M205.7 169.8h1.6M207.3 166.3v4.1M215.9 171.7h-.6v.6h-2.9M215.9 174.2h-.6v3.2h-2.9M229.9 169.2v5M229.9 175.5v2.5M238.1 175.5h8.3M246.4 178v1.3M246.4 170.4h-8.3v1.3M257.8 175.5h1.6v.6h8.6v1.3M257.8 170.4h1.6"/>
<path d="M257.8 173h2.9M257.8 178h2.9M259.4 166.9v4.2M268 172.3h-.7v.7h-2.8M268 174.9h-.7v3.1h-2.8M281.9 169.8v5.1M281.9 176.1v2.6M52.1 181.2h1.9M57.8 181.2h1.3v13.4M65.7 198.4h14.6M65.7 185.7h14.6M68.6 197.1h11.7"/>
<path d="M68.6 180.6h-2.9v1.3M68.6 193.3h-2.9v1.3M68.6 184.4h11.7M69.2 189.5h3.8M72.4 188.2h.6M75.9 181.9v1.2h4.4M75.9 194.6v1.2h4.4M79.7 194.6h.6M79.7 181.9h.6M90.2 198.4h14.6M90.2 185.7h14.6M93 197.1h11.8"/>
<path d="M93 193.3h-2.8v1.3M93 184.4h11.8M93 180.6h-2.8v1.3M93.7 189.5h3.8M96.8 188.2h.7M100.3 181.9v1.2h4.5M100.3 194.6v1.2h4.5M104.1 194.6h.7M104.1 181.9h.7M119.4 194.6v1.2h3.8M178.4 180.6v1.3M186.7 192.7h1.6"/>
<path d="M69.2 202.2h3.8M72.4 200.9h.6M93.7 202.2h3.8M96.8 200.9h.7M134.6 200.9h2.6"/>
</g>
<g fill="none" stroke="#000" stroke-width=".13">
<path d="M47.5 13.7v.6l.1 .1M49.6 9.9h.3M49.7 9.9v.7M158.1 58.2h.3M160.3 51.8h.4M160.7 45.1h.2v.4M160.7 52.7h.2v.4M160.7 56.5h.2v.4h-.2v-.2l.2-.1M160.8 46.4h.2v.4M160.8 55.3h.2v.3M160.8 50.2l.2-.1v.1v.4h-.2l-.1-.1 .1-.2h.2M160.9 45.2l-.3 .1 .1 .2h.2"/>
<path d="M160.9 52.8l-.3 .2 .1 .1h.2M161 46.5l-.3 .1 .1 .2 .2-.1M161 55.4l-.3 .1 .1 .1h.2M161.2 44.9v.5l.1 .1M161.2 52.5v.5l.1 .1M161.2 56.3v.5l.1 .1M161.4 46.1v.6v.1M161.4 55v.6M161.4 49.9v.6v.1M19.4 64.2h.3l.1-.2-.4-.1v.6M19.4 65.5h.3l.1-.3h-.4v.6M159.6 65.8h.3"/>
<path d="M160.7 76.8l.2-.2v.6M160.7 77.9h.2l.1 .1-.3 .5h.3M160.7 77.2h.3M210.7 71.2v.6h.3M233.3 71.8v.7h.3M262.8 71.8v.7h.3M285.4 72.5v.6h.3M15.6 94.7h.4v-.3h-.4v.6M17.4 96h.3l.1-.3h-.4v.6M19.3 84.6l.3-.1 .1-.2-.4-.1v.7M19.3 85.8h.3l.1-.2-.4-.1v.6M19.4 80.7h.3v-.2l-.3-.1v.6"/>
<path d="M19.9 88.4l.3-.1v-.2l-.3-.1v.7M19.9 89.6h.3v-.2l-.3-.1v.6M19.9 90.9h.3v-.3h-.3v.6M20 92.2l.4-.1v-.2l-.4-.1v.7M26.2 95.9h.2l.1 .4M158.5 97l.2-.1 .2 .2-.4 .5h.4M158.5 98.8h.4M158.6 99.5h.1a.31 .31 0 0 1 .2 .3 .31 .31 0 0 1-.3 .3l-.1-.2zM160.7 95.9h.2v.4M160.7 93.4h.2v.3M160.8 94.6h.2v.4M160.8 92.1h.2v.4h-.2l-.1-.1 .1-.1 .2-.1"/>
<path d="M160.9 96l-.3 .1 .1 .2h.2M160.9 93.5l-.3 .1 .1 .1h.2M161 94.7l-.3 .2 .1 .1h.2M161.2 88h.4l-.2 .3h.2v.3h-.4M161.2 95.7v.5l.1 .1M161.2 93.1v.6h.1M161.3 85.7l.1-.2v.6M161.3 86.8h.2l.1 .1-.4 .5h.4M161.3 86.1h.3M161.3 84.3l.1-.1a.31 .31 0 0 1 .2 .4 .31 .31 0 0 1-.2 .2l-.1-.2zM161.4 94.4v.5v.1M161.4 91.8v.6v.1"/>
<path d="M161.4 89.3l-.1 .4h.4M161.6 89.5v.4M161.6 90.6h-.3v.3h.3v.2h-.3M210.7 91.2h.3l.1-.2-.4-.1v.6M233.3 91.9l.3-.1v-.2l-.3-.1v.7M233.4 91.9l.3 .3M262.8 91.9l.3-.1v-.2l-.3-.1v.7M285.4 92.5h.3v-.3h-.3v.6M285.5 92.5l.2 .3M18.9 102.3l.3-.1v.4M18.9 102.2v.4M19.1 103.6l.2-.1v.4"/>
<path d="M19.1 103.5v.4M19.2 102.3l.3-.1v.4M19.3 103.6l.3-.1v.4M26.4 102v.5l.1 .1M26.4 103.3v.5l.1 .1M154.5 118.8h.3v.3M154.5 118.7v.4M154.6 116.9l.3-.1v.4M154.6 116.8v.4M154.8 118.8h.2l.1 .3M154.9 116.9l.3-.1v.4M162 118.5v.6h.1"/>
<path d="M162 116.6v.6h.1M210.7 112.8v.6h.3M233.3 113.4v.7h.3M262.8 113.4v.7h.3M285.4 114.1v.6h.3M40.1 125.8h.3v-.2l-.3-.1v.6M63.2 127.4h.4v-.3h-.4v.6M141.2 120.1h.4M154.5 122.6h.3v.4M154.5 126.4h.3v.4M154.5 122.5v.5M154.5 126.3v.5"/>
<path d="M154.6 120.7h.3v.4M154.6 124.5h.3v.4M154.6 120.6v.5M154.6 124.4v.5M154.8 122.6h.2l.1 .4M154.8 126.4h.2l.1 .4M154.9 120.7h.3v.4M154.9 124.5h.3v.4M162 122.3v.6l.1 .1M162 120.4v.6l.1 .1M162 124.2v.6l.1 .1M162 126.1v.6l.1 .1"/>
<path d="M210.7 132.8h.3l.1-.3h-.4v.6M233.3 133.4h.3v-.2l-.3-.1v.7M233.4 133.4l.3 .4M262.8 133.4h.3v-.2l-.3-.1v.7M285.4 134.1h.3v-.3h-.3v.6M285.5 134.1l.2 .3M54.5 148.7h.5M79.9 147.1a.32 .32 0 0 1 .3 .3 .32 .32 0 0 1-.3 .3zM80.5 147.5h.5M154.5 145.5l.3-.1v.4M154.5 149.3l.3-.1v.4M154.5 153.1l.3-.1v.4"/>
<path d="M154.5 145.4v.4M154.5 149.2v.4M154.5 153v.4M154.6 143.6l.3-.1v.4M154.6 147.4l.3-.1v.4M154.6 151.2l.3-.1v.4M154.6 143.5v.4M154.6 147.3v.4M154.6 151.1v.4M154.8 145.5l.2-.1 .1 .4M154.8 149.3l.2-.1 .1 .4M154.8 153.1l.2-.1 .1 .4"/>
<path d="M154.9 143.6l.3-.1v.4M154.9 147.4l.3-.1v.4M154.9 151.2l.3-.1v.4M162 143.3v.5l.1 .1M162 145.2v.5l.1 .1M162 147.1v.5l.1 .1M162 149v.5l.1 .1M162 150.9v.5l.1 .1M162 152.8v.5l.1 .1M210.7 154.4v.6h.3M233.3 155v.7h.3M262.8 155v.7h.3"/>
<path d="M285.4 155.7v.6h.3M69.8 171.5h.4v-.2l-.4-.1v.7M70.5 162.3h.4l-.2 .3h.2l-.1 .3h-.3M70.5 166.2l.3-.1 .1 .2-.4 .5h.4M78.6 171.5h.2l.1 .4M118.5 173.4v.6l.1 .1 .2-.1v-.6M210.7 174.4h.3l.1-.3h-.4v.6M233.3 175h.3v-.2l-.3-.1v.6M233.4 175l.3 .3M262.8 175h.3v-.2l-.3-.1v.6M285.4 175.7l.3-.1v-.2l-.3-.1v.7M285.5 175.7l.2 .3"/>
<path d="M8.3 185.2h.3v-.3h-.3v.6M8.3 181.4h.3v-.3h-.3v.6M8.3 182.7l.3-.1v-.2l-.3-.1v.7M8.3 183.9h.3v-.2l-.3-.1v.6M8.3 189h.3v-.3h-.3v.6M8.3 190.3h.3v-.3l-.3-.1v.7M8.9 192.8h.3v-.2l-.3-.1v.6M8.9 191.5h.3v-.2l-.3-.1v.7M9 186.5l.3-.1v-.2l-.3-.1v.7M9 187.7h.3v-.2l-.3-.1v.6M79.3 189.3h.4M103.9 187.5l.2-.1 .1 .2-.3 .4h.3"/>
<path d="M104.4 188.9l.2-.2v.6M104.4 189.3h.4M190.9 196.1h.5M79.4 200.2l.3-.1 .1 .2-.4 .4h.4M79.4 201.6l.2-.2v.6M79.4 202h.4M104.5 201.6l.2-.2v.6M104.5 200.2l.2-.1 .2 .2-.4 .4h.4M104.5 202h.4"/>
</g>
<g fill="#008400" stroke="#008400" stroke-width=".13">
<circle cx="83.8" cy="12.6" r=".25"/>
<circle cx="233.4" cy="43.1" r=".25"/>
<circle cx="22.2" cy="190.7" r=".25"/>
<circle cx="249.9" cy="37.1" r=".25"/>
<circle cx="22.2" cy="189.5" r=".25"/>
<circle cx="79.7" cy="172" r=".25"/>
<circle cx="95.2" cy="12.6" r=".25"/>
<circle cx="22.2" cy="192" r=".25"/>
<circle cx="249.9" cy="31.4" r=".25"/>
<circle cx="41.9" cy="14.5" r=".25"/>
<circle cx="65.7" cy="180.6" r=".25"/>
<circle cx="192.1" cy="54.5" r=".25"/>
<circle cx="207.3" cy="169.8" r=".25"/>
<circle cx="207.3" cy="108.5" r=".25"/>
<circle cx="41.9" cy="10.7" r=".25"/>
<circle cx="249.9" cy="27.6" r=".25"/>
<circle cx="14.9" cy="121.2" r=".25"/>
<circle cx="252.1" cy="51" r=".25"/>
<circle cx="249.9" cy="42.8" r=".25"/>
<circle cx="80" cy="181.9" r=".25"/>
<circle cx="68.6" cy="22.2" r=".25"/>
<circle cx="22.2" cy="185.7" r=".25"/>
<circle cx="22.2" cy="183.1" r=".25"/>
<circle cx="141.6" cy="26.3" r=".25"/>
<circle cx="22.2" cy="184.4" r=".25"/>
<circle cx="28.6" cy="192" r=".25"/>
<circle cx="137.2" cy="26.3" r=".25"/>
<circle cx="148" cy="120.3" r=".25"/>
<circle cx="132.7" cy="26.3" r=".25"/>
<circle cx="28.6" cy="190.7" r=".25"/>
<circle cx="28.6" cy="189.5" r=".25"/>
<circle cx="72.4" cy="184.4" r=".25"/>
<circle cx="69.2" cy="185.7" r=".25"/>
<circle cx="28.6" cy="188.2" r=".25"/>
<circle cx="142.2" cy="120.3" r=".25"/>
<circle cx="22.2" cy="188.2" r=".25"/>
<circle cx="28.6" cy="186.9" r=".25"/>
<circle cx="28.6" cy="185.7" r=".25"/>
<circle cx="249.9" cy="33.3" r=".25"/>
<circle cx="249.9" cy="39" r=".25"/>
<circle cx="22.2" cy="186.9" r=".25"/>
<circle cx="28.6" cy="184.4" r=".25"/>
<circle cx="28.6" cy="183.1" r=".25"/>
<circle cx="207.3" cy="155.2" r=".25"/>
<circle cx="28.6" cy="181.9" r=".25"/>
<circle cx="28.6" cy="193.3" r=".25"/>
<circle cx="22.2" cy="181.9" r=".25"/>
<circle cx="136.5" cy="120.3" r=".25"/>
<circle cx="93.7" cy="185.7" r=".25"/>
<circle cx="114.9" cy="30.1" r=".25"/>
<circle cx="137.2" cy="30.1" r=".25"/>
<circle cx="146" cy="30.1" r=".25"/>
<circle cx="90.2" cy="180.6" r=".25"/>
<circle cx="141.6" cy="30.1" r=".25"/>
<circle cx="93.7" cy="198.4" r=".25"/>
<circle cx="136.8" cy="15.8" r=".25"/>
<circle cx="281.9" cy="173.6" r=".25"/>
<circle cx="96.8" cy="197.1" r=".25"/>
<circle cx="110.5" cy="26.3" r=".25"/>
<circle cx="114.9" cy="26.3" r=".25"/>
<circle cx="90.2" cy="193.3" r=".25"/>
<circle cx="81.3" cy="125.3" r=".25"/>
<circle cx="131.4" cy="120.3" r=".25"/>
<circle cx="96.8" cy="184.4" r=".25"/>
<circle cx="186.1" cy="49.5" r=".25"/>
<circle cx="186.1" cy="50.7" r=".25"/>
<circle cx="128.3" cy="30.1" r=".25"/>
<circle cx="104.5" cy="194.6" r=".25"/>
<circle cx="132.7" cy="30.1" r=".25"/>
<circle cx="13" cy="141.9" r=".25"/>
<circle cx="19.4" cy="144.4" r=".25"/>
<circle cx="60.6" cy="146" r=".25"/>
<circle cx="60.6" cy="146.9" r=".25"/>
<circle cx="123.8" cy="30.1" r=".25"/>
<circle cx="119.4" cy="26.3" r=".25"/>
<circle cx="60.6" cy="147.9" r=".25"/>
<circle cx="119.4" cy="30.1" r=".25"/>
<circle cx="207.3" cy="133.3" r=".25"/>
<circle cx="171.8" cy="52" r=".25"/>
<circle cx="60.6" cy="148.8" r=".25"/>
<circle cx="175.9" cy="55.8" r=".25"/>
<circle cx="72.4" cy="197.1" r=".25"/>
<circle cx="249.9" cy="19.9" r=".25"/>
<circle cx="73.7" cy="120.3" r=".25"/>
<circle cx="65.7" cy="193.3" r=".25"/>
<circle cx="70.5" cy="120.3" r=".25"/>
<circle cx="60" cy="15.8" r=".25"/>
<circle cx="249.9" cy="16.1" r=".25"/>
<circle cx="69.2" cy="198.4" r=".25"/>
<circle cx="68.6" cy="15.8" r=".25"/>
<circle cx="207.3" cy="113.6" r=".25"/>
<circle cx="123.8" cy="26.3" r=".25"/>
<circle cx="54.9" cy="119.9" r=".25"/>
<circle cx="128.3" cy="26.3" r=".25"/>
<circle cx="249.9" cy="25.6" r=".25"/>
<circle cx="74.9" cy="15.8" r=".25"/>
<circle cx="80" cy="194.6" r=".25"/>
<circle cx="74.9" cy="22.2" r=".25"/>
<circle cx="249.9" cy="21.8" r=".25"/>
<circle cx="207.3" cy="150.1" r=".25"/>
<circle cx="196.8" cy="49.5" r=".25"/>
<circle cx="131.8" cy="15.8" r=".25"/>
<circle cx="175.9" cy="52" r=".25"/>
<circle cx="249.9" cy="14.2" r=".25"/>
<circle cx="61.3" cy="18.3" r=".25"/>
<circle cx="77.2" cy="124.1" r=".25"/>
<circle cx="60" cy="18.3" r=".25"/>
<circle cx="76.5" cy="124.1" r=".25"/>
<circle cx="25.4" cy="121.2" r=".25"/>
<circle cx="207.3" cy="128.2" r=".25"/>
<circle cx="73.7" cy="127.9" r=".25"/>
<circle cx="192.1" cy="50.7" r=".25"/>
<circle cx="70.5" cy="126.6" r=".25"/>
<circle cx="249.9" cy="10.4" r=".25"/>
<circle cx="104.5" cy="181.9" r=".25"/>
<circle cx="257.2" cy="54.9" r=".25"/>
<circle cx="76.5" cy="120.3" r=".25"/>
<circle cx="262.3" cy="51" r=".25"/>
<circle cx="186.1" cy="128.2" r=".25"/>
<circle cx="186.4" cy="150.1" r=".25"/>
<circle cx="238.1" cy="87.2" r=".25"/>
<circle cx="186.1" cy="169.8" r=".25"/>
<circle cx="259.4" cy="150.7" r=".25"/>
<circle cx="215.9" cy="72.6" r=".25"/>
<circle cx="238.4" cy="67.6" r=".25"/>
<circle cx="37.5" cy="149.5" r=".25"/>
<circle cx="229.9" cy="73.9" r=".25"/>
<circle cx="229.9" cy="67.6" r=".25"/>
<circle cx="229.9" cy="68.8" r=".25"/>
<circle cx="229.9" cy="70.1" r=".25"/>
<circle cx="215.9" cy="92.3" r=".25"/>
<circle cx="238.4" cy="109.2" r=".25"/>
<circle cx="257.2" cy="51" r=".25"/>
<circle cx="229.9" cy="87.2" r=".25"/>
<circle cx="119.1" cy="122.8" r=".25"/>
<circle cx="262.3" cy="54.9" r=".25"/>
<circle cx="267" cy="54.9" r=".25"/>
<circle cx="119.1" cy="124.1" r=".25"/>
<circle cx="229.9" cy="88.5" r=".25"/>
<circle cx="229.9" cy="89.8" r=".25"/>
<circle cx="229.9" cy="93.6" r=".25"/>
<circle cx="23.8" cy="24.4" r=".25"/>
<circle cx="10.8" cy="121.2" r=".25"/>
<circle cx="215.9" cy="114.2" r=".25"/>
<circle cx="75.9" cy="194.6" r=".25"/>
<circle cx="207.3" cy="86.6" r=".25"/>
<circle cx="203.8" cy="10.1" r=".25"/>
<circle cx="89.5" cy="18.3" r=".25"/>
<circle cx="259.4" cy="87.2" r=".25"/>
<circle cx="209.5" cy="10.1" r=".25"/>
<circle cx="208.9" cy="49.5" r=".25"/>
<circle cx="219.1" cy="49.5" r=".25"/>
<circle cx="52.7" cy="181.2" r=".25"/>
<circle cx="259.4" cy="170.4" r=".25"/>
<circle cx="214" cy="54.5" r=".25"/>
<circle cx="208.9" cy="54.5" r=".25"/>
<circle cx="100.3" cy="181.9" r=".25"/>
<circle cx="100.3" cy="194.6" r=".25"/>
<circle cx="21.3" cy="121.2" r=".25"/>
<circle cx="75.9" cy="181.9" r=".25"/>
<circle cx="186.4" cy="66.9" r=".25"/>
<circle cx="238.1" cy="170.4" r=".25"/>
<circle cx="195.6" cy="14.9" r=".25"/>
<circle cx="238.4" cy="150.7" r=".25"/>
<circle cx="259.4" cy="155.8" r=".25"/>
<circle cx="208.3" cy="29.8" r=".25"/>
<circle cx="259.4" cy="92.3" r=".25"/>
<circle cx="207.3" cy="91.7" r=".25"/>
<circle cx="238.1" cy="128.8" r=".25"/>
<circle cx="186.1" cy="86.6" r=".25"/>
<circle cx="186.4" cy="108.5" r=".25"/>
<circle cx="268" cy="134.6" r=".25"/>
<circle cx="281.9" cy="111.1" r=".25"/>
<circle cx="229.9" cy="153.3" r=".25"/>
<circle cx="281.9" cy="109.8" r=".25"/>
<circle cx="229.9" cy="157.1" r=".25"/>
<circle cx="268" cy="114.9" r=".25"/>
<circle cx="281.9" cy="135.8" r=".25"/>
<circle cx="259.4" cy="114.2" r=".25"/>
<circle cx="215.9" cy="175.5" r=".25"/>
<circle cx="281.9" cy="132" r=".25"/>
<circle cx="281.9" cy="130.7" r=".25"/>
<circle cx="229.9" cy="170.4" r=".25"/>
<circle cx="281.9" cy="129.5" r=".25"/>
<circle cx="229.9" cy="171.7" r=".25"/>
<circle cx="281.9" cy="112.3" r=".25"/>
<circle cx="229.9" cy="173" r=".25"/>
<circle cx="281.9" cy="157.7" r=".25"/>
<circle cx="259.4" cy="128.8" r=".25"/>
<circle cx="281.9" cy="153.9" r=".25"/>
<circle cx="281.9" cy="152.6" r=".25"/>
<circle cx="229.9" cy="176.8" r=".25"/>
<circle cx="281.9" cy="151.4" r=".25"/>
<circle cx="268" cy="156.5" r=".25"/>
<circle cx="268" cy="176.1" r=".25"/>
<circle cx="281.9" cy="177.4" r=".25"/>
<circle cx="281.9" cy="171.1" r=".25"/>
<circle cx="281.9" cy="172.3" r=".25"/>
<circle cx="268" cy="73.3" r=".25"/>
<circle cx="229.9" cy="109.2" r=".25"/>
<circle cx="259.4" cy="109.2" r=".25"/>
<circle cx="229.9" cy="110.4" r=".25"/>
<circle cx="229.9" cy="111.7" r=".25"/>
<circle cx="194.9" cy="12.9" r=".25"/>
<circle cx="229.9" cy="115.5" r=".25"/>
<circle cx="281.9" cy="74.5" r=".25"/>
<circle cx="215.9" cy="133.9" r=".25"/>
<circle cx="229.9" cy="128.8" r=".25"/>
<circle cx="281.9" cy="70.7" r=".25"/>
<circle cx="281.9" cy="69.5" r=".25"/>
<circle cx="281.9" cy="68.2" r=".25"/>
<circle cx="229.9" cy="130.1" r=".25"/>
<circle cx="209.5" cy="20.3" r=".25"/>
<circle cx="281.9" cy="94.2" r=".25"/>
<circle cx="229.9" cy="131.4" r=".25"/>
<circle cx="259.4" cy="133.9" r=".25"/>
<circle cx="281.9" cy="90.4" r=".25"/>
<circle cx="281.9" cy="89.1" r=".25"/>
<circle cx="229.9" cy="135.2" r=".25"/>
<circle cx="281.9" cy="87.9" r=".25"/>
<circle cx="268" cy="93" r=".25"/>
<circle cx="215.9" cy="155.8" r=".25"/>
<circle cx="281.9" cy="116.1" r=".25"/>
<circle cx="229.9" cy="150.7" r=".25"/>
<circle cx="229.9" cy="152" r=".25"/>
<circle cx="52.7" cy="186.9" r=".25"/>
<circle cx="59.1" cy="186.9" r=".25"/>
<circle cx="59.1" cy="188.2" r=".25"/>
<circle cx="59.1" cy="189.5" r=".25"/>
<circle cx="59.1" cy="190.7" r=".25"/>
<circle cx="59.1" cy="192" r=".25"/>
<circle cx="123.2" cy="195.8" r=".25"/>
<circle cx="59.1" cy="193.3" r=".25"/>
<circle cx="23.8" cy="19.9" r=".25"/>
<circle cx="52.7" cy="185.7" r=".25"/>
<circle cx="59.1" cy="185.7" r=".25"/>
<circle cx="23.8" cy="15.5" r=".25"/>
<circle cx="135.9" cy="160.3" r=".25"/>
<circle cx="134.6" cy="160.3" r=".25"/>
<circle cx="52.7" cy="188.2" r=".25"/>
<circle cx="52.7" cy="189.5" r=".25"/>
<circle cx="135.9" cy="200.9" r=".25"/>
<circle cx="137.2" cy="200.9" r=".25"/>
<circle cx="52.7" cy="190.7" r=".25"/>
<circle cx="207.3" cy="66.9" r=".25"/>
<circle cx="119.7" cy="157.4" r=".25"/>
<circle cx="84.5" cy="33.6" r=".25"/>
<circle cx="178.4" cy="180.6" r=".25"/>
<circle cx="88.3" cy="33.6" r=".25"/>
<circle cx="92.1" cy="33.6" r=".25"/>
<circle cx="95.9" cy="33.6" r=".25"/>
<circle cx="99.7" cy="33.6" r=".25"/>
<circle cx="124.1" cy="161.2" r=".25"/>
<circle cx="128.6" cy="161.2" r=".25"/>
<circle cx="124.1" cy="157.4" r=".25"/>
<circle cx="13.3" cy="42.8" r=".25"/>
<circle cx="207.3" cy="174.9" r=".25"/>
<circle cx="196.8" cy="54.5" r=".25"/>
<circle cx="101.6" cy="113.6" r=".25"/>
<circle cx="118.7" cy="165.3" r=".25"/>
<circle cx="15.9" cy="53.9" r=".25"/>
<circle cx="10.8" cy="50.1" r=".25"/>
<circle cx="59.1" cy="194.6" r=".25"/>
<circle cx="122.9" cy="165.3" r=".25"/>
<circle cx="67.9" cy="33.6" r=".25"/>
<circle cx="200.7" cy="18.7" r=".25"/>
<circle cx="181" cy="14.9" r=".25"/>
<circle cx="181" cy="18.7" r=".25"/>
<circle cx="175.9" cy="14.9" r=".25"/>
<circle cx="11.1" cy="39" r=".25"/>
<circle cx="33.3" cy="149.5" r=".25"/>
<circle cx="22.2" cy="177.4" r=".25"/>
<circle cx="197.8" cy="34.2" r=".25"/>
<circle cx="197.8" cy="38.7" r=".25"/>
<circle cx="15.6" cy="39" r=".25"/>
<circle cx="259.4" cy="67.6" r=".25"/>
<circle cx="61.6" cy="33.6" r=".25"/>
<circle cx="229.2" cy="39.3" r=".25"/>
<circle cx="229.6" cy="13.3" r=".25"/>
<circle cx="54.6" cy="118.7" r=".25"/>
<circle cx="207.3" cy="72" r=".25"/>
<circle cx="187.3" cy="50.7" r=".25"/>
<circle cx="259.4" cy="175.5" r=".25"/>
<circle cx="223.2" cy="33.9" r=".25"/>
<circle cx="259.4" cy="72.6" r=".25"/>
<circle cx="203.5" cy="54.5" r=".25"/>
<circle cx="80.6" cy="33.6" r=".25"/>
<circle cx="233.4" cy="33.9" r=".25"/>
<circle cx="107.9" cy="113.6" r=".25"/>
<circle cx="52.7" cy="192" r=".25"/>
<circle cx="52.7" cy="193.3" r=".25"/>
<circle cx="223.2" cy="30.1" r=".25"/>
<circle cx="203.5" cy="49.5" r=".25"/>
<circle cx="239.1" cy="43.1" r=".25"/>
<circle cx="223.8" cy="10.7" r=".25"/>
<circle cx="33.7" cy="15.5" r=".25"/>
</g>
<g fill="none" stroke="#000084" stroke-width=".13">
<path d="M180.7 12.6l.6 .7M181.3 12.6l-.6 .7M228.6 15.5l.6 .6M229.2 15.5l-.6 .6M233.1 26l.6 .6M233.7 26l-.6 .6M223.5 40.3l.6 .6M224.1 40.3l-.6 .6M81.3 118.7l.6 .6M81.9 118.7l-.6 .6M48.3 152.7l.6 .6M48.9 152.7l-.6 .6"/>
<path d="M53.4 150.1l.6 .6M54 150.1l-.6 .6M79.4 151.4l.6 .6M79.4 150.4l.6 .6M79.4 149.5l.6 .6M80 151.4l-.6 .6M80 150.4l-.6 .6M80 149.5l-.6 .6M99.7 147.6l.6 .6M100.3 147.6l-.6 .6M115.6 147.6l.6 .6M116.2 147.6l-.6 .6"/>
<path d="M131.5 147.6l.6 .6M132.1 147.6l-.6 .6M147.3 147.6l.6 .6M147.9 147.6l-.6 .6M91.1 160.3l.6 .6M91.7 160.3l-.6 .6M112.7 171.7l.6 .6M113.3 171.7l-.6 .6M122.9 176.5l.6 .6M122.9 177.7l.6 .7M123.5 176.5l-.6 .6M123.5 177.7l-.6 .7"/>
<path d="M170.5 170.1l.6 .6M170.5 168.9l.6 .6M170.5 171.4l.6 .6M170.5 167.6l.6 .6M170.5 166.3l.6 .6M170.5 165l.6 .7M170.5 176.5l.6 .6M170.5 177.7l.6 .7M171.1 170.1l-.6 .6M171.1 168.9l-.6 .6M171.1 171.4l-.6 .6M171.1 167.6l-.6 .6"/>
<path d="M171.1 166.3l-.6 .6M171.1 165l-.6 .7M171.1 176.5l-.6 .6M171.1 177.7l-.6 .7M122.9 180.3l.6 .6M122.9 181.6l.6 .6M122.9 184.1l.6 .6M122.9 185.4l.6 .6M122.9 187.9l.6 .6M122.9 189.2l.6 .6M123.5 180.3l-.6 .6M123.5 181.6l-.6 .6"/>
<path d="M123.5 184.1l-.6 .6M123.5 185.4l-.6 .6M123.5 187.9l-.6 .6M123.5 189.2l-.6 .6M170.5 195.5l.6 .6M170.5 189.2l.6 .6M170.5 190.4l.6 .7M170.5 194.3l.6 .6M170.5 186.6l.6 .6M170.5 187.9l.6 .6M170.5 184.1l.6 .6M170.5 185.4l.6 .6"/>
<path d="M171.1 195.5l-.6 .6M171.1 189.2l-.6 .6M171.1 190.4l-.6 .7M171.1 194.3l-.6 .6M171.1 186.6l-.6 .6M171.1 187.9l-.6 .6M171.1 184.1l-.6 .6M171.1 185.4l-.6 .6M181.3 200l.6 .6M181.9 200l-.6 .6M199.1 190.1l.6 .6M199.7 190.1l-.6 .6"/>
</g>
<use href="#words"/>
</svg>
